VERSION 5.8 ;
BUSBITCHARS "[]" ;
DIVIDERCHAR "/" ;
MANUFACTURINGGRID 0.05 ;

UNITS
    DATABASE MICRONS 1000 ;
END UNITS

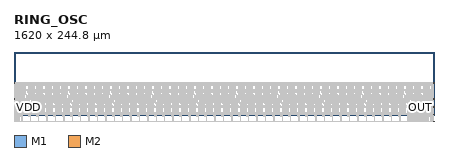
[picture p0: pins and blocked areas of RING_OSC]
MACRO RING_OSC
    CLASS BLOCK ;
    FOREIGN RING_OSC 0.0 0.0 ;
    ORIGIN 0.0 0.0 ;
    SIZE 1620.000 BY 244.800 ;

    PIN OUT
        DIRECTION OUTPUT ;
        USE SIGNAL ;
        PORT
            LAYER M1 ;
                RECT 1616.600 28.000 1620.000 31.400 ;
        END
    END OUT

    PIN OUTD
        DIRECTION OUTPUT ;
        USE SIGNAL ;
        PORT
            LAYER M1 ;
                RECT 1616.600 -26.600 1620.000 -23.200 ;
        END
    END OUTD

    PIN ENB
        DIRECTION INPUT ;
        USE SIGNAL ;
        PORT
            LAYER M2 ;
                RECT 11.800 -118.900 15.200 -115.500 ;
        END
    END ENB

    PIN VDD
        DIRECTION INOUT ;
        USE POWER ;
        PORT
            LAYER M1 ;
                RECT 0.000 -58.900 2.600 -56.300 ;
            LAYER M1 ;
                RECT 1617.400 -58.900 1620.000 -56.300 ;
            LAYER M1 ;
                RECT 0.000 61.100 2.600 63.700 ;
            LAYER M1 ;
                RECT 1617.400 61.100 1620.000 63.700 ;
        END
    END VDD

    PIN VSS
        DIRECTION INOUT ;
        USE GROUND ;
        PORT
            LAYER M1 ;
                RECT 0.000 -118.900 2.600 -116.300 ;
            LAYER M1 ;
                RECT 1617.400 -118.900 1620.000 -116.300 ;
            LAYER M1 ;
                RECT 0.000 1.100 2.600 3.700 ;
            LAYER M1 ;
                RECT 1617.400 1.100 1620.000 3.700 ;
            LAYER M1 ;
                RECT 0.000 121.100 2.600 123.700 ;
            LAYER M1 ;
                RECT 1617.400 121.100 1620.000 123.700 ;
        END
    END VSS

    OBS
        LAYER M1 ;
            POLYGON 2.600 -118.900  2.600 -116.300  1.000 -116.300  1.000 -113.700  4.400 -113.700  4.400 -116.300  11.800 -116.300  11.800 -100.900  14.400 -100.900  14.400 -116.300  18.000 -116.300  18.000 -83.900  20.600 -83.900  20.600 -116.300  49.300 -116.300  49.300 -110.100  51.900 -110.100  51.900 -116.300  81.700 -116.300  81.700 -110.100  84.300 -110.100  84.300 -116.300  114.100 -116.300  114.100 -110.100  116.700 -110.100  116.700 -116.300  146.500 -116.300  146.500 -110.100  149.100 -110.100  149.100 -116.300  178.900 -116.300  178.900 -110.100  181.500 -110.100  181.500 -116.300  211.300 -116.300  211.300 -110.100  213.900 -110.100  213.900 -116.300  243.700 -116.300  243.700 -110.100  246.300 -110.100  246.300 -116.300  276.100 -116.300  276.100 -110.100  278.700 -110.100  278.700 -116.300  308.500 -116.300  308.500 -110.100  311.100 -110.100  311.100 -116.300  340.900 -116.300  340.900 -110.100  343.500 -110.100  343.500 -116.300  373.300 -116.300  373.300 -110.100  375.900 -110.100  375.900 -116.300  405.700 -116.300  405.700 -110.100  408.300 -110.100  408.300 -116.300  438.100 -116.300  438.100 -110.100  440.700 -110.100  440.700 -116.300  470.500 -116.300  470.500 -110.100  473.100 -110.100  473.100 -116.300  502.900 -116.300  502.900 -110.100  505.500 -110.100  505.500 -116.300  535.300 -116.300  535.300 -110.100  537.900 -110.100  537.900 -116.300  567.700 -116.300  567.700 -110.100  570.300 -110.100  570.300 -116.300  600.100 -116.300  600.100 -110.100  602.700 -110.100  602.700 -116.300  632.500 -116.300  632.500 -110.100  635.100 -110.100  635.100 -116.300  664.900 -116.300  664.900 -110.100  667.500 -110.100  667.500 -116.300  697.300 -116.300  697.300 -110.100  699.900 -110.100  699.900 -116.300  729.700 -116.300  729.700 -110.100  732.300 -110.100  732.300 -116.300  762.100 -116.300  762.100 -110.100  764.700 -110.100  764.700 -116.300  794.500 -116.300  794.500 -110.100  797.100 -110.100  797.100 -116.300  826.900 -116.300  826.900 -110.100  829.500 -110.100  829.500 -116.300  859.300 -116.300  859.300 -110.100  861.900 -110.100  861.900 -116.300  891.700 -116.300  891.700 -110.100  894.300 -110.100  894.300 -116.300  924.100 -116.300  924.100 -110.100  926.700 -110.100  926.700 -116.300  956.500 -116.300  956.500 -110.100  959.100 -110.100  959.100 -116.300  988.900 -116.300  988.900 -110.100  991.500 -110.100  991.500 -116.300  1021.300 -116.300  1021.300 -110.100  1023.900 -110.100  1023.900 -116.300  1053.700 -116.300  1053.700 -110.100  1056.300 -110.100  1056.300 -116.300  1086.100 -116.300  1086.100 -110.100  1088.700 -110.100  1088.700 -116.300  1118.500 -116.300  1118.500 -110.100  1121.100 -110.100  1121.100 -116.300  1150.900 -116.300  1150.900 -110.100  1153.500 -110.100  1153.500 -116.300  1183.300 -116.300  1183.300 -110.100  1185.900 -110.100  1185.900 -116.300  1215.700 -116.300  1215.700 -110.100  1218.300 -110.100  1218.300 -116.300  1248.100 -116.300  1248.100 -110.100  1250.700 -110.100  1250.700 -116.300  1280.500 -116.300  1280.500 -110.100  1283.100 -110.100  1283.100 -116.300  1312.900 -116.300  1312.900 -110.100  1315.500 -110.100  1315.500 -116.300  1345.300 -116.300  1345.300 -110.100  1347.900 -110.100  1347.900 -116.300  1377.700 -116.300  1377.700 -110.100  1380.300 -110.100  1380.300 -116.300  1410.100 -116.300  1410.100 -110.100  1412.700 -110.100  1412.700 -116.300  1442.500 -116.300  1442.500 -110.100  1445.100 -110.100  1445.100 -116.300  1474.900 -116.300  1474.900 -110.100  1477.500 -110.100  1477.500 -116.300  1507.300 -116.300  1507.300 -110.100  1509.900 -110.100  1509.900 -116.300  1539.700 -116.300  1539.700 -110.100  1542.300 -110.100  1542.300 -116.300  1572.100 -116.300  1572.100 -110.100  1574.700 -110.100  1574.700 -116.300  1604.500 -116.300  1604.500 -110.100  1607.100 -110.100  1607.100 -116.300  1610.200 -116.300  1610.200 -113.700  1613.600 -113.700  1613.600 -116.300  1617.400 -116.300  1617.400 -118.900 ;
            POLYGON 11.800 -99.300  11.800 -58.900  9.800 -58.900  9.800 -61.500  6.400 -61.500  6.400 -58.900  2.600 -58.900  2.600 -56.300  6.400 -56.300  6.400 -53.700  9.800 -53.700  9.800 -56.300  11.800 -56.300  11.800 -32.900  14.400 -32.900  14.400 -56.300  18.000 -56.300  18.000 -15.900  20.600 -15.900  20.600 -56.300  22.300 -56.300  22.300 -43.300  24.900 -43.300  24.900 -56.300  54.700 -56.300  54.700 -43.300  57.300 -43.300  57.300 -56.300  87.100 -56.300  87.100 -43.300  89.700 -43.300  89.700 -56.300  119.500 -56.300  119.500 -43.300  122.100 -43.300  122.100 -56.300  151.900 -56.300  151.900 -43.300  154.500 -43.300  154.500 -56.300  184.300 -56.300  184.300 -43.300  186.900 -43.300  186.900 -56.300  216.700 -56.300  216.700 -43.300  219.300 -43.300  219.300 -56.300  249.100 -56.300  249.100 -43.300  251.700 -43.300  251.700 -56.300  281.500 -56.300  281.500 -43.300  284.100 -43.300  284.100 -56.300  313.900 -56.300  313.900 -43.300  316.500 -43.300  316.500 -56.300  346.300 -56.300  346.300 -43.300  348.900 -43.300  348.900 -56.300  378.700 -56.300  378.700 -43.300  381.300 -43.300  381.300 -56.300  411.100 -56.300  411.100 -43.300  413.700 -43.300  413.700 -56.300  443.500 -56.300  443.500 -43.300  446.100 -43.300  446.100 -56.300  475.900 -56.300  475.900 -43.300  478.500 -43.300  478.500 -56.300  508.300 -56.300  508.300 -43.300  510.900 -43.300  510.900 -56.300  540.700 -56.300  540.700 -43.300  543.300 -43.300  543.300 -56.300  573.100 -56.300  573.100 -43.300  575.700 -43.300  575.700 -56.300  605.500 -56.300  605.500 -43.300  608.100 -43.300  608.100 -56.300  637.900 -56.300  637.900 -43.300  640.500 -43.300  640.500 -56.300  670.300 -56.300  670.300 -43.300  672.900 -43.300  672.900 -56.300  702.700 -56.300  702.700 -43.300  705.300 -43.300  705.300 -56.300  735.100 -56.300  735.100 -43.300  737.700 -43.300  737.700 -56.300  767.500 -56.300  767.500 -43.300  770.100 -43.300  770.100 -56.300  799.900 -56.300  799.900 -43.300  802.500 -43.300  802.500 -56.300  832.300 -56.300  832.300 -43.300  834.900 -43.300  834.900 -56.300  864.700 -56.300  864.700 -43.300  867.300 -43.300  867.300 -56.300  897.100 -56.300  897.100 -43.300  899.700 -43.300  899.700 -56.300  929.500 -56.300  929.500 -43.300  932.100 -43.300  932.100 -56.300  961.900 -56.300  961.900 -43.300  964.500 -43.300  964.500 -56.300  994.300 -56.300  994.300 -43.300  996.900 -43.300  996.900 -56.300  1026.700 -56.300  1026.700 -43.300  1029.300 -43.300  1029.300 -56.300  1059.100 -56.300  1059.100 -43.300  1061.700 -43.300  1061.700 -56.300  1091.500 -56.300  1091.500 -43.300  1094.100 -43.300  1094.100 -56.300  1123.900 -56.300  1123.900 -43.300  1126.500 -43.300  1126.500 -56.300  1156.300 -56.300  1156.300 -43.300  1158.900 -43.300  1158.900 -56.300  1188.700 -56.300  1188.700 -43.300  1191.300 -43.300  1191.300 -56.300  1221.100 -56.300  1221.100 -43.300  1223.700 -43.300  1223.700 -56.300  1253.500 -56.300  1253.500 -43.300  1256.100 -43.300  1256.100 -56.300  1285.900 -56.300  1285.900 -43.300  1288.500 -43.300  1288.500 -56.300  1318.300 -56.300  1318.300 -43.300  1320.900 -43.300  1320.900 -56.300  1350.700 -56.300  1350.700 -43.300  1353.300 -43.300  1353.300 -56.300  1383.100 -56.300  1383.100 -43.300  1385.700 -43.300  1385.700 -56.300  1415.500 -56.300  1415.500 -43.300  1418.100 -43.300  1418.100 -56.300  1447.900 -56.300  1447.900 -43.300  1450.500 -43.300  1450.500 -56.300  1480.300 -56.300  1480.300 -43.300  1482.900 -43.300  1482.900 -56.300  1512.700 -56.300  1512.700 -43.300  1515.300 -43.300  1515.300 -56.300  1520.700 -56.300  1520.700 -43.300  1523.300 -43.300  1523.300 -56.300  1534.600 -56.300  1534.600 -32.900  1537.200 -32.900  1537.200 -56.300  1540.800 -56.300  1540.800 -15.900  1543.400 -15.900  1543.400 -56.300  1545.400 -56.300  1545.400 -32.900  1548.000 -32.900  1548.000 -56.300  1551.600 -56.300  1551.600 -15.900  1554.200 -15.900  1554.200 -56.300  1556.200 -56.300  1556.200 -32.900  1558.800 -32.900  1558.800 -56.300  1562.400 -56.300  1562.400 -15.900  1565.000 -15.900  1565.000 -56.300  1567.000 -56.300  1567.000 -32.900  1569.600 -32.900  1569.600 -56.300  1573.200 -56.300  1573.200 -15.900  1575.800 -15.900  1575.800 -56.300  1577.800 -56.300  1577.800 -32.900  1580.400 -32.900  1580.400 -56.300  1584.000 -56.300  1584.000 -15.900  1586.600 -15.900  1586.600 -56.300  1588.600 -56.300  1588.600 -32.900  1591.200 -32.900  1591.200 -56.300  1594.800 -56.300  1594.800 -15.900  1597.400 -15.900  1597.400 -56.300  1599.100 -56.300  1599.100 -43.300  1601.700 -43.300  1601.700 -56.300  1615.600 -56.300  1615.600 -53.700  1619.000 -53.700  1619.000 -56.300  1617.400 -56.300  1617.400 -58.900  1619.000 -58.900  1619.000 -61.500  1615.600 -61.500  1615.600 -58.900  1608.500 -58.900  1608.500 -71.900  1605.900 -71.900  1605.900 -58.900  1576.100 -58.900  1576.100 -71.900  1573.500 -71.900  1573.500 -58.900  1543.700 -58.900  1543.700 -71.900  1541.100 -71.900  1541.100 -58.900  1511.300 -58.900  1511.300 -71.900  1508.700 -71.900  1508.700 -58.900  1478.900 -58.900  1478.900 -71.900  1476.300 -71.900  1476.300 -58.900  1446.500 -58.900  1446.500 -71.900  1443.900 -71.900  1443.900 -58.900  1414.100 -58.900  1414.100 -71.900  1411.500 -71.900  1411.500 -58.900  1381.700 -58.900  1381.700 -71.900  1379.100 -71.900  1379.100 -58.900  1349.300 -58.900  1349.300 -71.900  1346.700 -71.900  1346.700 -58.900  1316.900 -58.900  1316.900 -71.900  1314.300 -71.900  1314.300 -58.900  1284.500 -58.900  1284.500 -71.900  1281.900 -71.900  1281.900 -58.900  1252.100 -58.900  1252.100 -71.900  1249.500 -71.900  1249.500 -58.900  1219.700 -58.900  1219.700 -71.900  1217.100 -71.900  1217.100 -58.900  1187.300 -58.900  1187.300 -71.900  1184.700 -71.900  1184.700 -58.900  1154.900 -58.900  1154.900 -71.900  1152.300 -71.900  1152.300 -58.900  1122.500 -58.900  1122.500 -71.900  1119.900 -71.900  1119.900 -58.900  1090.100 -58.900  1090.100 -71.900  1087.500 -71.900  1087.500 -58.900  1057.700 -58.900  1057.700 -71.900  1055.100 -71.900  1055.100 -58.900  1025.300 -58.900  1025.300 -71.900  1022.700 -71.900  1022.700 -58.900  992.900 -58.900  992.900 -71.900  990.300 -71.900  990.300 -58.900  960.500 -58.900  960.500 -71.900  957.900 -71.900  957.900 -58.900  928.100 -58.900  928.100 -71.900  925.500 -71.900  925.500 -58.900  895.700 -58.900  895.700 -71.900  893.100 -71.900  893.100 -58.900  863.300 -58.900  863.300 -71.900  860.700 -71.900  860.700 -58.900  830.900 -58.900  830.900 -71.900  828.300 -71.900  828.300 -58.900  798.500 -58.900  798.500 -71.900  795.900 -71.900  795.900 -58.900  766.100 -58.900  766.100 -71.900  763.500 -71.900  763.500 -58.900  733.700 -58.900  733.700 -71.900  731.100 -71.900  731.100 -58.900  701.300 -58.900  701.300 -71.900  698.700 -71.900  698.700 -58.900  668.900 -58.900  668.900 -71.900  666.300 -71.900  666.300 -58.900  636.500 -58.900  636.500 -71.900  633.900 -71.900  633.900 -58.900  604.100 -58.900  604.100 -71.900  601.500 -71.900  601.500 -58.900  571.700 -58.900  571.700 -71.900  569.100 -71.900  569.100 -58.900  539.300 -58.900  539.300 -71.900  536.700 -71.900  536.700 -58.900  506.900 -58.900  506.900 -71.900  504.300 -71.900  504.300 -58.900  474.500 -58.900  474.500 -71.900  471.900 -71.900  471.900 -58.900  442.100 -58.900  442.100 -71.900  439.500 -71.900  439.500 -58.900  409.700 -58.900  409.700 -71.900  407.100 -71.900  407.100 -58.900  377.300 -58.900  377.300 -71.900  374.700 -71.900  374.700 -58.900  344.900 -58.900  344.900 -71.900  342.300 -71.900  342.300 -58.900  312.500 -58.900  312.500 -71.900  309.900 -71.900  309.900 -58.900  280.100 -58.900  280.100 -71.900  277.500 -71.900  277.500 -58.900  247.700 -58.900  247.700 -71.900  245.100 -71.900  245.100 -58.900  215.300 -58.900  215.300 -71.900  212.700 -71.900  212.700 -58.900  182.900 -58.900  182.900 -71.900  180.300 -71.900  180.300 -58.900  150.500 -58.900  150.500 -71.900  147.900 -71.900  147.900 -58.900  118.100 -58.900  118.100 -71.900  115.500 -71.900  115.500 -58.900  85.700 -58.900  85.700 -71.900  83.100 -71.900  83.100 -58.900  53.300 -58.900  53.300 -71.900  50.700 -71.900  50.700 -58.900  20.600 -58.900  20.600 -82.300  18.000 -82.300  18.000 -58.900  14.400 -58.900  14.400 -99.300 ;
            POLYGON 11.800 -31.300  11.800 1.100  4.400 1.100  4.400 -1.500  1.000 -1.500  1.000 1.100  2.600 1.100  2.600 3.700  1.000 3.700  1.000 6.300  4.400 6.300  4.400 3.700  11.800 3.700  11.800 36.100  14.400 36.100  14.400 3.700  18.000 3.700  18.000 19.100  20.600 19.100  20.600 3.700  23.700 3.700  23.700 9.900  26.300 9.900  26.300 3.700  33.400 3.700  33.400 36.100  36.000 36.100  36.000 3.700  39.600 3.700  39.600 19.100  42.200 19.100  42.200 3.700  44.200 3.700  44.200 36.100  46.800 36.100  46.800 3.700  50.400 3.700  50.400 19.100  53.000 19.100  53.000 3.700  56.100 3.700  56.100 9.900  58.700 9.900  58.700 3.700  65.800 3.700  65.800 36.100  68.400 36.100  68.400 3.700  72.000 3.700  72.000 19.100  74.600 19.100  74.600 3.700  76.600 3.700  76.600 36.100  79.200 36.100  79.200 3.700  82.800 3.700  82.800 19.100  85.400 19.100  85.400 3.700  88.500 3.700  88.500 9.900  91.100 9.900  91.100 3.700  98.200 3.700  98.200 36.100  100.800 36.100  100.800 3.700  104.400 3.700  104.400 19.100  107.000 19.100  107.000 3.700  109.000 3.700  109.000 36.100  111.600 36.100  111.600 3.700  115.200 3.700  115.200 19.100  117.800 19.100  117.800 3.700  120.900 3.700  120.900 9.900  123.500 9.900  123.500 3.700  130.600 3.700  130.600 36.100  133.200 36.100  133.200 3.700  136.800 3.700  136.800 19.100  139.400 19.100  139.400 3.700  141.400 3.700  141.400 36.100  144.000 36.100  144.000 3.700  147.600 3.700  147.600 19.100  150.200 19.100  150.200 3.700  153.300 3.700  153.300 9.900  155.900 9.900  155.900 3.700  163.000 3.700  163.000 36.100  165.600 36.100  165.600 3.700  169.200 3.700  169.200 19.100  171.800 19.100  171.800 3.700  173.800 3.700  173.800 36.100  176.400 36.100  176.400 3.700  180.000 3.700  180.000 19.100  182.600 19.100  182.600 3.700  185.700 3.700  185.700 9.900  188.300 9.900  188.300 3.700  195.400 3.700  195.400 36.100  198.000 36.100  198.000 3.700  201.600 3.700  201.600 19.100  204.200 19.100  204.200 3.700  206.200 3.700  206.200 36.100  208.800 36.100  208.800 3.700  212.400 3.700  212.400 19.100  215.000 19.100  215.000 3.700  218.100 3.700  218.100 9.900  220.700 9.900  220.700 3.700  227.800 3.700  227.800 36.100  230.400 36.100  230.400 3.700  234.000 3.700  234.000 19.100  236.600 19.100  236.600 3.700  238.600 3.700  238.600 36.100  241.200 36.100  241.200 3.700  244.800 3.700  244.800 19.100  247.400 19.100  247.400 3.700  250.500 3.700  250.500 9.900  253.100 9.900  253.100 3.700  260.200 3.700  260.200 36.100  262.800 36.100  262.800 3.700  266.400 3.700  266.400 19.100  269.000 19.100  269.000 3.700  271.000 3.700  271.000 36.100  273.600 36.100  273.600 3.700  277.200 3.700  277.200 19.100  279.800 19.100  279.800 3.700  282.900 3.700  282.900 9.900  285.500 9.900  285.500 3.700  292.600 3.700  292.600 36.100  295.200 36.100  295.200 3.700  298.800 3.700  298.800 19.100  301.400 19.100  301.400 3.700  303.400 3.700  303.400 36.100  306.000 36.100  306.000 3.700  309.600 3.700  309.600 19.100  312.200 19.100  312.200 3.700  315.300 3.700  315.300 9.900  317.900 9.900  317.900 3.700  325.000 3.700  325.000 36.100  327.600 36.100  327.600 3.700  331.200 3.700  331.200 19.100  333.800 19.100  333.800 3.700  335.800 3.700  335.800 36.100  338.400 36.100  338.400 3.700  342.000 3.700  342.000 19.100  344.600 19.100  344.600 3.700  347.700 3.700  347.700 9.900  350.300 9.900  350.300 3.700  357.400 3.700  357.400 36.100  360.000 36.100  360.000 3.700  363.600 3.700  363.600 19.100  366.200 19.100  366.200 3.700  368.200 3.700  368.200 36.100  370.800 36.100  370.800 3.700  374.400 3.700  374.400 19.100  377.000 19.100  377.000 3.700  380.100 3.700  380.100 9.900  382.700 9.900  382.700 3.700  389.800 3.700  389.800 36.100  392.400 36.100  392.400 3.700  396.000 3.700  396.000 19.100  398.600 19.100  398.600 3.700  400.600 3.700  400.600 36.100  403.200 36.100  403.200 3.700  406.800 3.700  406.800 19.100  409.400 19.100  409.400 3.700  412.500 3.700  412.500 9.900  415.100 9.900  415.100 3.700  422.200 3.700  422.200 36.100  424.800 36.100  424.800 3.700  428.400 3.700  428.400 19.100  431.000 19.100  431.000 3.700  433.000 3.700  433.000 36.100  435.600 36.100  435.600 3.700  439.200 3.700  439.200 19.100  441.800 19.100  441.800 3.700  444.900 3.700  444.900 9.900  447.500 9.900  447.500 3.700  454.600 3.700  454.600 36.100  457.200 36.100  457.200 3.700  460.800 3.700  460.800 19.100  463.400 19.100  463.400 3.700  465.400 3.700  465.400 36.100  468.000 36.100  468.000 3.700  471.600 3.700  471.600 19.100  474.200 19.100  474.200 3.700  477.300 3.700  477.300 9.900  479.900 9.900  479.900 3.700  487.000 3.700  487.000 36.100  489.600 36.100  489.600 3.700  493.200 3.700  493.200 19.100  495.800 19.100  495.800 3.700  497.800 3.700  497.800 36.100  500.400 36.100  500.400 3.700  504.000 3.700  504.000 19.100  506.600 19.100  506.600 3.700  509.700 3.700  509.700 9.900  512.300 9.900  512.300 3.700  519.400 3.700  519.400 36.100  522.000 36.100  522.000 3.700  525.600 3.700  525.600 19.100  528.200 19.100  528.200 3.700  530.200 3.700  530.200 36.100  532.800 36.100  532.800 3.700  536.400 3.700  536.400 19.100  539.000 19.100  539.000 3.700  542.100 3.700  542.100 9.900  544.700 9.900  544.700 3.700  551.800 3.700  551.800 36.100  554.400 36.100  554.400 3.700  558.000 3.700  558.000 19.100  560.600 19.100  560.600 3.700  562.600 3.700  562.600 36.100  565.200 36.100  565.200 3.700  568.800 3.700  568.800 19.100  571.400 19.100  571.400 3.700  574.500 3.700  574.500 9.900  577.100 9.900  577.100 3.700  584.200 3.700  584.200 36.100  586.800 36.100  586.800 3.700  590.400 3.700  590.400 19.100  593.000 19.100  593.000 3.700  595.000 3.700  595.000 36.100  597.600 36.100  597.600 3.700  601.200 3.700  601.200 19.100  603.800 19.100  603.800 3.700  606.900 3.700  606.900 9.900  609.500 9.900  609.500 3.700  616.600 3.700  616.600 36.100  619.200 36.100  619.200 3.700  622.800 3.700  622.800 19.100  625.400 19.100  625.400 3.700  627.400 3.700  627.400 36.100  630.000 36.100  630.000 3.700  633.600 3.700  633.600 19.100  636.200 19.100  636.200 3.700  639.300 3.700  639.300 9.900  641.900 9.900  641.900 3.700  649.000 3.700  649.000 36.100  651.600 36.100  651.600 3.700  655.200 3.700  655.200 19.100  657.800 19.100  657.800 3.700  659.800 3.700  659.800 36.100  662.400 36.100  662.400 3.700  666.000 3.700  666.000 19.100  668.600 19.100  668.600 3.700  671.700 3.700  671.700 9.900  674.300 9.900  674.300 3.700  681.400 3.700  681.400 36.100  684.000 36.100  684.000 3.700  687.600 3.700  687.600 19.100  690.200 19.100  690.200 3.700  692.200 3.700  692.200 36.100  694.800 36.100  694.800 3.700  698.400 3.700  698.400 19.100  701.000 19.100  701.000 3.700  704.100 3.700  704.100 9.900  706.700 9.900  706.700 3.700  713.800 3.700  713.800 36.100  716.400 36.100  716.400 3.700  720.000 3.700  720.000 19.100  722.600 19.100  722.600 3.700  724.600 3.700  724.600 36.100  727.200 36.100  727.200 3.700  730.800 3.700  730.800 19.100  733.400 19.100  733.400 3.700  736.500 3.700  736.500 9.900  739.100 9.900  739.100 3.700  746.200 3.700  746.200 36.100  748.800 36.100  748.800 3.700  752.400 3.700  752.400 19.100  755.000 19.100  755.000 3.700  757.000 3.700  757.000 36.100  759.600 36.100  759.600 3.700  763.200 3.700  763.200 19.100  765.800 19.100  765.800 3.700  768.900 3.700  768.900 9.900  771.500 9.900  771.500 3.700  778.600 3.700  778.600 36.100  781.200 36.100  781.200 3.700  784.800 3.700  784.800 19.100  787.400 19.100  787.400 3.700  789.400 3.700  789.400 36.100  792.000 36.100  792.000 3.700  795.600 3.700  795.600 19.100  798.200 19.100  798.200 3.700  801.300 3.700  801.300 9.900  803.900 9.900  803.900 3.700  811.000 3.700  811.000 36.100  813.600 36.100  813.600 3.700  817.200 3.700  817.200 19.100  819.800 19.100  819.800 3.700  821.800 3.700  821.800 36.100  824.400 36.100  824.400 3.700  828.000 3.700  828.000 19.100  830.600 19.100  830.600 3.700  833.700 3.700  833.700 9.900  836.300 9.900  836.300 3.700  843.400 3.700  843.400 36.100  846.000 36.100  846.000 3.700  849.600 3.700  849.600 19.100  852.200 19.100  852.200 3.700  854.200 3.700  854.200 36.100  856.800 36.100  856.800 3.700  860.400 3.700  860.400 19.100  863.000 19.100  863.000 3.700  866.100 3.700  866.100 9.900  868.700 9.900  868.700 3.700  875.800 3.700  875.800 36.100  878.400 36.100  878.400 3.700  882.000 3.700  882.000 19.100  884.600 19.100  884.600 3.700  886.600 3.700  886.600 36.100  889.200 36.100  889.200 3.700  892.800 3.700  892.800 19.100  895.400 19.100  895.400 3.700  898.500 3.700  898.500 9.900  901.100 9.900  901.100 3.700  908.200 3.700  908.200 36.100  910.800 36.100  910.800 3.700  914.400 3.700  914.400 19.100  917.000 19.100  917.000 3.700  919.000 3.700  919.000 36.100  921.600 36.100  921.600 3.700  925.200 3.700  925.200 19.100  927.800 19.100  927.800 3.700  930.900 3.700  930.900 9.900  933.500 9.900  933.500 3.700  940.600 3.700  940.600 36.100  943.200 36.100  943.200 3.700  946.800 3.700  946.800 19.100  949.400 19.100  949.400 3.700  951.400 3.700  951.400 36.100  954.000 36.100  954.000 3.700  957.600 3.700  957.600 19.100  960.200 19.100  960.200 3.700  963.300 3.700  963.300 9.900  965.900 9.900  965.900 3.700  973.000 3.700  973.000 36.100  975.600 36.100  975.600 3.700  979.200 3.700  979.200 19.100  981.800 19.100  981.800 3.700  983.800 3.700  983.800 36.100  986.400 36.100  986.400 3.700  990.000 3.700  990.000 19.100  992.600 19.100  992.600 3.700  995.700 3.700  995.700 9.900  998.300 9.900  998.300 3.700  1005.400 3.700  1005.400 36.100  1008.000 36.100  1008.000 3.700  1011.600 3.700  1011.600 19.100  1014.200 19.100  1014.200 3.700  1016.200 3.700  1016.200 36.100  1018.800 36.100  1018.800 3.700  1022.400 3.700  1022.400 19.100  1025.000 19.100  1025.000 3.700  1028.100 3.700  1028.100 9.900  1030.700 9.900  1030.700 3.700  1037.800 3.700  1037.800 36.100  1040.400 36.100  1040.400 3.700  1044.000 3.700  1044.000 19.100  1046.600 19.100  1046.600 3.700  1048.600 3.700  1048.600 36.100  1051.200 36.100  1051.200 3.700  1054.800 3.700  1054.800 19.100  1057.400 19.100  1057.400 3.700  1060.500 3.700  1060.500 9.900  1063.100 9.900  1063.100 3.700  1070.200 3.700  1070.200 36.100  1072.800 36.100  1072.800 3.700  1076.400 3.700  1076.400 19.100  1079.000 19.100  1079.000 3.700  1081.000 3.700  1081.000 36.100  1083.600 36.100  1083.600 3.700  1087.200 3.700  1087.200 19.100  1089.800 19.100  1089.800 3.700  1092.900 3.700  1092.900 9.900  1095.500 9.900  1095.500 3.700  1102.600 3.700  1102.600 36.100  1105.200 36.100  1105.200 3.700  1108.800 3.700  1108.800 19.100  1111.400 19.100  1111.400 3.700  1113.400 3.700  1113.400 36.100  1116.000 36.100  1116.000 3.700  1119.600 3.700  1119.600 19.100  1122.200 19.100  1122.200 3.700  1125.300 3.700  1125.300 9.900  1127.900 9.900  1127.900 3.700  1135.000 3.700  1135.000 36.100  1137.600 36.100  1137.600 3.700  1141.200 3.700  1141.200 19.100  1143.800 19.100  1143.800 3.700  1145.800 3.700  1145.800 36.100  1148.400 36.100  1148.400 3.700  1152.000 3.700  1152.000 19.100  1154.600 19.100  1154.600 3.700  1157.700 3.700  1157.700 9.900  1160.300 9.900  1160.300 3.700  1167.400 3.700  1167.400 36.100  1170.000 36.100  1170.000 3.700  1173.600 3.700  1173.600 19.100  1176.200 19.100  1176.200 3.700  1178.200 3.700  1178.200 36.100  1180.800 36.100  1180.800 3.700  1184.400 3.700  1184.400 19.100  1187.000 19.100  1187.000 3.700  1190.100 3.700  1190.100 9.900  1192.700 9.900  1192.700 3.700  1199.800 3.700  1199.800 36.100  1202.400 36.100  1202.400 3.700  1206.000 3.700  1206.000 19.100  1208.600 19.100  1208.600 3.700  1210.600 3.700  1210.600 36.100  1213.200 36.100  1213.200 3.700  1216.800 3.700  1216.800 19.100  1219.400 19.100  1219.400 3.700  1222.500 3.700  1222.500 9.900  1225.100 9.900  1225.100 3.700  1232.200 3.700  1232.200 36.100  1234.800 36.100  1234.800 3.700  1238.400 3.700  1238.400 19.100  1241.000 19.100  1241.000 3.700  1243.000 3.700  1243.000 36.100  1245.600 36.100  1245.600 3.700  1249.200 3.700  1249.200 19.100  1251.800 19.100  1251.800 3.700  1254.900 3.700  1254.900 9.900  1257.500 9.900  1257.500 3.700  1264.600 3.700  1264.600 36.100  1267.200 36.100  1267.200 3.700  1270.800 3.700  1270.800 19.100  1273.400 19.100  1273.400 3.700  1275.400 3.700  1275.400 36.100  1278.000 36.100  1278.000 3.700  1281.600 3.700  1281.600 19.100  1284.200 19.100  1284.200 3.700  1287.300 3.700  1287.300 9.900  1289.900 9.900  1289.900 3.700  1297.000 3.700  1297.000 36.100  1299.600 36.100  1299.600 3.700  1303.200 3.700  1303.200 19.100  1305.800 19.100  1305.800 3.700  1307.800 3.700  1307.800 36.100  1310.400 36.100  1310.400 3.700  1314.000 3.700  1314.000 19.100  1316.600 19.100  1316.600 3.700  1319.700 3.700  1319.700 9.900  1322.300 9.900  1322.300 3.700  1329.400 3.700  1329.400 36.100  1332.000 36.100  1332.000 3.700  1335.600 3.700  1335.600 19.100  1338.200 19.100  1338.200 3.700  1340.200 3.700  1340.200 36.100  1342.800 36.100  1342.800 3.700  1346.400 3.700  1346.400 19.100  1349.000 19.100  1349.000 3.700  1352.100 3.700  1352.100 9.900  1354.700 9.900  1354.700 3.700  1361.800 3.700  1361.800 36.100  1364.400 36.100  1364.400 3.700  1368.000 3.700  1368.000 19.100  1370.600 19.100  1370.600 3.700  1372.600 3.700  1372.600 36.100  1375.200 36.100  1375.200 3.700  1378.800 3.700  1378.800 19.100  1381.400 19.100  1381.400 3.700  1384.500 3.700  1384.500 9.900  1387.100 9.900  1387.100 3.700  1394.200 3.700  1394.200 36.100  1396.800 36.100  1396.800 3.700  1400.400 3.700  1400.400 19.100  1403.000 19.100  1403.000 3.700  1405.000 3.700  1405.000 36.100  1407.600 36.100  1407.600 3.700  1411.200 3.700  1411.200 19.100  1413.800 19.100  1413.800 3.700  1416.900 3.700  1416.900 9.900  1419.500 9.900  1419.500 3.700  1426.600 3.700  1426.600 36.100  1429.200 36.100  1429.200 3.700  1432.800 3.700  1432.800 19.100  1435.400 19.100  1435.400 3.700  1437.400 3.700  1437.400 36.100  1440.000 36.100  1440.000 3.700  1443.600 3.700  1443.600 19.100  1446.200 19.100  1446.200 3.700  1449.300 3.700  1449.300 9.900  1451.900 9.900  1451.900 3.700  1459.000 3.700  1459.000 36.100  1461.600 36.100  1461.600 3.700  1465.200 3.700  1465.200 19.100  1467.800 19.100  1467.800 3.700  1469.800 3.700  1469.800 36.100  1472.400 36.100  1472.400 3.700  1476.000 3.700  1476.000 19.100  1478.600 19.100  1478.600 3.700  1481.700 3.700  1481.700 9.900  1484.300 9.900  1484.300 3.700  1491.400 3.700  1491.400 36.100  1494.000 36.100  1494.000 3.700  1497.600 3.700  1497.600 19.100  1500.200 19.100  1500.200 3.700  1502.200 3.700  1502.200 36.100  1504.800 36.100  1504.800 3.700  1508.400 3.700  1508.400 19.100  1511.000 19.100  1511.000 3.700  1517.300 3.700  1517.300 19.600  1519.900 19.600  1519.900 11.100  1527.500 11.100  1527.500 7.700  1519.900 7.700  1519.900 3.700  1534.600 3.700  1534.600 36.100  1537.200 36.100  1537.200 3.700  1540.800 3.700  1540.800 19.100  1543.400 19.100  1543.400 3.700  1545.400 3.700  1545.400 36.100  1548.000 36.100  1548.000 3.700  1551.600 3.700  1551.600 19.100  1554.200 19.100  1554.200 3.700  1556.200 3.700  1556.200 36.100  1558.800 36.100  1558.800 3.700  1562.400 3.700  1562.400 19.100  1565.000 19.100  1565.000 3.700  1567.000 3.700  1567.000 36.100  1569.600 36.100  1569.600 3.700  1573.200 3.700  1573.200 19.100  1575.800 19.100  1575.800 3.700  1577.800 3.700  1577.800 36.100  1580.400 36.100  1580.400 3.700  1584.000 3.700  1584.000 19.100  1586.600 19.100  1586.600 3.700  1588.600 3.700  1588.600 36.100  1591.200 36.100  1591.200 3.700  1594.800 3.700  1594.800 19.100  1597.400 19.100  1597.400 3.700  1600.500 3.700  1600.500 9.900  1603.100 9.900  1603.100 3.700  1610.200 3.700  1610.200 6.300  1613.600 6.300  1613.600 3.700  1617.400 3.700  1617.400 1.100  1613.600 1.100  1613.600 -1.500  1610.200 -1.500  1610.200 1.100  1603.100 1.100  1603.100 -5.100  1600.500 -5.100  1600.500 1.100  1597.400 1.100  1597.400 -14.300  1594.800 -14.300  1594.800 1.100  1591.200 1.100  1591.200 -31.300  1588.600 -31.300  1588.600 1.100  1586.600 1.100  1586.600 -14.300  1584.000 -14.300  1584.000 1.100  1580.400 1.100  1580.400 -31.300  1577.800 -31.300  1577.800 1.100  1575.800 1.100  1575.800 -14.300  1573.200 -14.300  1573.200 1.100  1569.600 1.100  1569.600 -31.300  1567.000 -31.300  1567.000 1.100  1565.000 1.100  1565.000 -14.300  1562.400 -14.300  1562.400 1.100  1558.800 1.100  1558.800 -31.300  1556.200 -31.300  1556.200 1.100  1554.200 1.100  1554.200 -14.300  1551.600 -14.300  1551.600 1.100  1548.000 1.100  1548.000 -31.300  1545.400 -31.300  1545.400 1.100  1543.400 1.100  1543.400 -14.300  1540.800 -14.300  1540.800 1.100  1537.200 1.100  1537.200 -31.300  1534.600 -31.300  1534.600 1.100  1519.900 1.100  1519.900 -2.900  1527.500 -2.900  1527.500 -6.300  1519.900 -6.300  1519.900 -14.800  1517.300 -14.800  1517.300 1.100  1484.300 1.100  1484.300 -5.100  1481.700 -5.100  1481.700 1.100  1451.900 1.100  1451.900 -5.100  1449.300 -5.100  1449.300 1.100  1419.500 1.100  1419.500 -5.100  1416.900 -5.100  1416.900 1.100  1387.100 1.100  1387.100 -5.100  1384.500 -5.100  1384.500 1.100  1354.700 1.100  1354.700 -5.100  1352.100 -5.100  1352.100 1.100  1322.300 1.100  1322.300 -5.100  1319.700 -5.100  1319.700 1.100  1289.900 1.100  1289.900 -5.100  1287.300 -5.100  1287.300 1.100  1257.500 1.100  1257.500 -5.100  1254.900 -5.100  1254.900 1.100  1225.100 1.100  1225.100 -5.100  1222.500 -5.100  1222.500 1.100  1192.700 1.100  1192.700 -5.100  1190.100 -5.100  1190.100 1.100  1160.300 1.100  1160.300 -5.100  1157.700 -5.100  1157.700 1.100  1127.900 1.100  1127.900 -5.100  1125.300 -5.100  1125.300 1.100  1095.500 1.100  1095.500 -5.100  1092.900 -5.100  1092.900 1.100  1063.100 1.100  1063.100 -5.100  1060.500 -5.100  1060.500 1.100  1030.700 1.100  1030.700 -5.100  1028.100 -5.100  1028.100 1.100  998.300 1.100  998.300 -5.100  995.700 -5.100  995.700 1.100  965.900 1.100  965.900 -5.100  963.300 -5.100  963.300 1.100  933.500 1.100  933.500 -5.100  930.900 -5.100  930.900 1.100  901.100 1.100  901.100 -5.100  898.500 -5.100  898.500 1.100  868.700 1.100  868.700 -5.100  866.100 -5.100  866.100 1.100  836.300 1.100  836.300 -5.100  833.700 -5.100  833.700 1.100  803.900 1.100  803.900 -5.100  801.300 -5.100  801.300 1.100  771.500 1.100  771.500 -5.100  768.900 -5.100  768.900 1.100  739.100 1.100  739.100 -5.100  736.500 -5.100  736.500 1.100  706.700 1.100  706.700 -5.100  704.100 -5.100  704.100 1.100  674.300 1.100  674.300 -5.100  671.700 -5.100  671.700 1.100  641.900 1.100  641.900 -5.100  639.300 -5.100  639.300 1.100  609.500 1.100  609.500 -5.100  606.900 -5.100  606.900 1.100  577.100 1.100  577.100 -5.100  574.500 -5.100  574.500 1.100  544.700 1.100  544.700 -5.100  542.100 -5.100  542.100 1.100  512.300 1.100  512.300 -5.100  509.700 -5.100  509.700 1.100  479.900 1.100  479.900 -5.100  477.300 -5.100  477.300 1.100  447.500 1.100  447.500 -5.100  444.900 -5.100  444.900 1.100  415.100 1.100  415.100 -5.100  412.500 -5.100  412.500 1.100  382.700 1.100  382.700 -5.100  380.100 -5.100  380.100 1.100  350.300 1.100  350.300 -5.100  347.700 -5.100  347.700 1.100  317.900 1.100  317.900 -5.100  315.300 -5.100  315.300 1.100  285.500 1.100  285.500 -5.100  282.900 -5.100  282.900 1.100  253.100 1.100  253.100 -5.100  250.500 -5.100  250.500 1.100  220.700 1.100  220.700 -5.100  218.100 -5.100  218.100 1.100  188.300 1.100  188.300 -5.100  185.700 -5.100  185.700 1.100  155.900 1.100  155.900 -5.100  153.300 -5.100  153.300 1.100  123.500 1.100  123.500 -5.100  120.900 -5.100  120.900 1.100  91.100 1.100  91.100 -5.100  88.500 -5.100  88.500 1.100  58.700 1.100  58.700 -5.100  56.100 -5.100  56.100 1.100  26.300 1.100  26.300 -5.100  23.700 -5.100  23.700 1.100  20.600 1.100  20.600 -14.300  18.000 -14.300  18.000 1.100  14.400 1.100  14.400 -31.300 ;
            POLYGON 18.000 20.700  18.000 61.100  14.400 61.100  14.400 37.700  11.800 37.700  11.800 61.100  9.800 61.100  9.800 58.500  6.400 58.500  6.400 61.100  2.600 61.100  2.600 63.700  6.400 63.700  6.400 66.300  9.800 66.300  9.800 63.700  11.800 63.700  11.800 104.100  14.400 104.100  14.400 63.700  18.000 63.700  18.000 87.100  20.600 87.100  20.600 63.700  22.600 63.700  22.600 104.100  25.200 104.100  25.200 63.700  28.800 63.700  28.800 87.100  31.400 87.100  31.400 63.700  33.400 63.700  33.400 104.100  36.000 104.100  36.000 63.700  39.600 63.700  39.600 87.100  42.200 87.100  42.200 63.700  50.700 63.700  50.700 76.700  53.300 76.700  53.300 63.700  55.000 63.700  55.000 104.100  57.600 104.100  57.600 63.700  61.200 63.700  61.200 87.100  63.800 87.100  63.800 63.700  65.800 63.700  65.800 104.100  68.400 104.100  68.400 63.700  72.000 63.700  72.000 87.100  74.600 87.100  74.600 63.700  83.100 63.700  83.100 76.700  85.700 76.700  85.700 63.700  87.400 63.700  87.400 104.100  90.000 104.100  90.000 63.700  93.600 63.700  93.600 87.100  96.200 87.100  96.200 63.700  98.200 63.700  98.200 104.100  100.800 104.100  100.800 63.700  104.400 63.700  104.400 87.100  107.000 87.100  107.000 63.700  115.500 63.700  115.500 76.700  118.100 76.700  118.100 63.700  119.800 63.700  119.800 104.100  122.400 104.100  122.400 63.700  126.000 63.700  126.000 87.100  128.600 87.100  128.600 63.700  130.600 63.700  130.600 104.100  133.200 104.100  133.200 63.700  136.800 63.700  136.800 87.100  139.400 87.100  139.400 63.700  147.900 63.700  147.900 76.700  150.500 76.700  150.500 63.700  152.200 63.700  152.200 104.100  154.800 104.100  154.800 63.700  158.400 63.700  158.400 87.100  161.000 87.100  161.000 63.700  163.000 63.700  163.000 104.100  165.600 104.100  165.600 63.700  169.200 63.700  169.200 87.100  171.800 87.100  171.800 63.700  180.300 63.700  180.300 76.700  182.900 76.700  182.900 63.700  184.600 63.700  184.600 104.100  187.200 104.100  187.200 63.700  190.800 63.700  190.800 87.100  193.400 87.100  193.400 63.700  195.400 63.700  195.400 104.100  198.000 104.100  198.000 63.700  201.600 63.700  201.600 87.100  204.200 87.100  204.200 63.700  212.700 63.700  212.700 76.700  215.300 76.700  215.300 63.700  217.000 63.700  217.000 104.100  219.600 104.100  219.600 63.700  223.200 63.700  223.200 87.100  225.800 87.100  225.800 63.700  227.800 63.700  227.800 104.100  230.400 104.100  230.400 63.700  234.000 63.700  234.000 87.100  236.600 87.100  236.600 63.700  245.100 63.700  245.100 76.700  247.700 76.700  247.700 63.700  249.400 63.700  249.400 104.100  252.000 104.100  252.000 63.700  255.600 63.700  255.600 87.100  258.200 87.100  258.200 63.700  260.200 63.700  260.200 104.100  262.800 104.100  262.800 63.700  266.400 63.700  266.400 87.100  269.000 87.100  269.000 63.700  277.500 63.700  277.500 76.700  280.100 76.700  280.100 63.700  281.800 63.700  281.800 104.100  284.400 104.100  284.400 63.700  288.000 63.700  288.000 87.100  290.600 87.100  290.600 63.700  292.600 63.700  292.600 104.100  295.200 104.100  295.200 63.700  298.800 63.700  298.800 87.100  301.400 87.100  301.400 63.700  309.900 63.700  309.900 76.700  312.500 76.700  312.500 63.700  314.200 63.700  314.200 104.100  316.800 104.100  316.800 63.700  320.400 63.700  320.400 87.100  323.000 87.100  323.000 63.700  325.000 63.700  325.000 104.100  327.600 104.100  327.600 63.700  331.200 63.700  331.200 87.100  333.800 87.100  333.800 63.700  342.300 63.700  342.300 76.700  344.900 76.700  344.900 63.700  346.600 63.700  346.600 104.100  349.200 104.100  349.200 63.700  352.800 63.700  352.800 87.100  355.400 87.100  355.400 63.700  357.400 63.700  357.400 104.100  360.000 104.100  360.000 63.700  363.600 63.700  363.600 87.100  366.200 87.100  366.200 63.700  374.700 63.700  374.700 76.700  377.300 76.700  377.300 63.700  379.000 63.700  379.000 104.100  381.600 104.100  381.600 63.700  385.200 63.700  385.200 87.100  387.800 87.100  387.800 63.700  389.800 63.700  389.800 104.100  392.400 104.100  392.400 63.700  396.000 63.700  396.000 87.100  398.600 87.100  398.600 63.700  407.100 63.700  407.100 76.700  409.700 76.700  409.700 63.700  411.400 63.700  411.400 104.100  414.000 104.100  414.000 63.700  417.600 63.700  417.600 87.100  420.200 87.100  420.200 63.700  422.200 63.700  422.200 104.100  424.800 104.100  424.800 63.700  428.400 63.700  428.400 87.100  431.000 87.100  431.000 63.700  439.500 63.700  439.500 76.700  442.100 76.700  442.100 63.700  443.800 63.700  443.800 104.100  446.400 104.100  446.400 63.700  450.000 63.700  450.000 87.100  452.600 87.100  452.600 63.700  454.600 63.700  454.600 104.100  457.200 104.100  457.200 63.700  460.800 63.700  460.800 87.100  463.400 87.100  463.400 63.700  471.900 63.700  471.900 76.700  474.500 76.700  474.500 63.700  476.200 63.700  476.200 104.100  478.800 104.100  478.800 63.700  482.400 63.700  482.400 87.100  485.000 87.100  485.000 63.700  487.000 63.700  487.000 104.100  489.600 104.100  489.600 63.700  493.200 63.700  493.200 87.100  495.800 87.100  495.800 63.700  504.300 63.700  504.300 76.700  506.900 76.700  506.900 63.700  508.600 63.700  508.600 104.100  511.200 104.100  511.200 63.700  514.800 63.700  514.800 87.100  517.400 87.100  517.400 63.700  519.400 63.700  519.400 104.100  522.000 104.100  522.000 63.700  525.600 63.700  525.600 87.100  528.200 87.100  528.200 63.700  536.700 63.700  536.700 76.700  539.300 76.700  539.300 63.700  541.000 63.700  541.000 104.100  543.600 104.100  543.600 63.700  547.200 63.700  547.200 87.100  549.800 87.100  549.800 63.700  551.800 63.700  551.800 104.100  554.400 104.100  554.400 63.700  558.000 63.700  558.000 87.100  560.600 87.100  560.600 63.700  569.100 63.700  569.100 76.700  571.700 76.700  571.700 63.700  573.400 63.700  573.400 104.100  576.000 104.100  576.000 63.700  579.600 63.700  579.600 87.100  582.200 87.100  582.200 63.700  584.200 63.700  584.200 104.100  586.800 104.100  586.800 63.700  590.400 63.700  590.400 87.100  593.000 87.100  593.000 63.700  601.500 63.700  601.500 76.700  604.100 76.700  604.100 63.700  605.800 63.700  605.800 104.100  608.400 104.100  608.400 63.700  612.000 63.700  612.000 87.100  614.600 87.100  614.600 63.700  616.600 63.700  616.600 104.100  619.200 104.100  619.200 63.700  622.800 63.700  622.800 87.100  625.400 87.100  625.400 63.700  633.900 63.700  633.900 76.700  636.500 76.700  636.500 63.700  638.200 63.700  638.200 104.100  640.800 104.100  640.800 63.700  644.400 63.700  644.400 87.100  647.000 87.100  647.000 63.700  649.000 63.700  649.000 104.100  651.600 104.100  651.600 63.700  655.200 63.700  655.200 87.100  657.800 87.100  657.800 63.700  666.300 63.700  666.300 76.700  668.900 76.700  668.900 63.700  670.600 63.700  670.600 104.100  673.200 104.100  673.200 63.700  676.800 63.700  676.800 87.100  679.400 87.100  679.400 63.700  681.400 63.700  681.400 104.100  684.000 104.100  684.000 63.700  687.600 63.700  687.600 87.100  690.200 87.100  690.200 63.700  698.700 63.700  698.700 76.700  701.300 76.700  701.300 63.700  703.000 63.700  703.000 104.100  705.600 104.100  705.600 63.700  709.200 63.700  709.200 87.100  711.800 87.100  711.800 63.700  713.800 63.700  713.800 104.100  716.400 104.100  716.400 63.700  720.000 63.700  720.000 87.100  722.600 87.100  722.600 63.700  731.100 63.700  731.100 76.700  733.700 76.700  733.700 63.700  735.400 63.700  735.400 104.100  738.000 104.100  738.000 63.700  741.600 63.700  741.600 87.100  744.200 87.100  744.200 63.700  746.200 63.700  746.200 104.100  748.800 104.100  748.800 63.700  752.400 63.700  752.400 87.100  755.000 87.100  755.000 63.700  763.500 63.700  763.500 76.700  766.100 76.700  766.100 63.700  767.800 63.700  767.800 104.100  770.400 104.100  770.400 63.700  774.000 63.700  774.000 87.100  776.600 87.100  776.600 63.700  778.600 63.700  778.600 104.100  781.200 104.100  781.200 63.700  784.800 63.700  784.800 87.100  787.400 87.100  787.400 63.700  795.900 63.700  795.900 76.700  798.500 76.700  798.500 63.700  800.200 63.700  800.200 104.100  802.800 104.100  802.800 63.700  806.400 63.700  806.400 87.100  809.000 87.100  809.000 63.700  811.000 63.700  811.000 104.100  813.600 104.100  813.600 63.700  817.200 63.700  817.200 87.100  819.800 87.100  819.800 63.700  828.300 63.700  828.300 76.700  830.900 76.700  830.900 63.700  832.600 63.700  832.600 104.100  835.200 104.100  835.200 63.700  838.800 63.700  838.800 87.100  841.400 87.100  841.400 63.700  843.400 63.700  843.400 104.100  846.000 104.100  846.000 63.700  849.600 63.700  849.600 87.100  852.200 87.100  852.200 63.700  860.700 63.700  860.700 76.700  863.300 76.700  863.300 63.700  865.000 63.700  865.000 104.100  867.600 104.100  867.600 63.700  871.200 63.700  871.200 87.100  873.800 87.100  873.800 63.700  875.800 63.700  875.800 104.100  878.400 104.100  878.400 63.700  882.000 63.700  882.000 87.100  884.600 87.100  884.600 63.700  893.100 63.700  893.100 76.700  895.700 76.700  895.700 63.700  897.400 63.700  897.400 104.100  900.000 104.100  900.000 63.700  903.600 63.700  903.600 87.100  906.200 87.100  906.200 63.700  908.200 63.700  908.200 104.100  910.800 104.100  910.800 63.700  914.400 63.700  914.400 87.100  917.000 87.100  917.000 63.700  925.500 63.700  925.500 76.700  928.100 76.700  928.100 63.700  929.800 63.700  929.800 104.100  932.400 104.100  932.400 63.700  936.000 63.700  936.000 87.100  938.600 87.100  938.600 63.700  940.600 63.700  940.600 104.100  943.200 104.100  943.200 63.700  946.800 63.700  946.800 87.100  949.400 87.100  949.400 63.700  957.900 63.700  957.900 76.700  960.500 76.700  960.500 63.700  962.200 63.700  962.200 104.100  964.800 104.100  964.800 63.700  968.400 63.700  968.400 87.100  971.000 87.100  971.000 63.700  973.000 63.700  973.000 104.100  975.600 104.100  975.600 63.700  979.200 63.700  979.200 87.100  981.800 87.100  981.800 63.700  990.300 63.700  990.300 76.700  992.900 76.700  992.900 63.700  994.600 63.700  994.600 104.100  997.200 104.100  997.200 63.700  1000.800 63.700  1000.800 87.100  1003.400 87.100  1003.400 63.700  1005.400 63.700  1005.400 104.100  1008.000 104.100  1008.000 63.700  1011.600 63.700  1011.600 87.100  1014.200 87.100  1014.200 63.700  1022.700 63.700  1022.700 76.700  1025.300 76.700  1025.300 63.700  1027.000 63.700  1027.000 104.100  1029.600 104.100  1029.600 63.700  1033.200 63.700  1033.200 87.100  1035.800 87.100  1035.800 63.700  1037.800 63.700  1037.800 104.100  1040.400 104.100  1040.400 63.700  1044.000 63.700  1044.000 87.100  1046.600 87.100  1046.600 63.700  1055.100 63.700  1055.100 76.700  1057.700 76.700  1057.700 63.700  1059.400 63.700  1059.400 104.100  1062.000 104.100  1062.000 63.700  1065.600 63.700  1065.600 87.100  1068.200 87.100  1068.200 63.700  1070.200 63.700  1070.200 104.100  1072.800 104.100  1072.800 63.700  1076.400 63.700  1076.400 87.100  1079.000 87.100  1079.000 63.700  1087.500 63.700  1087.500 76.700  1090.100 76.700  1090.100 63.700  1091.800 63.700  1091.800 104.100  1094.400 104.100  1094.400 63.700  1098.000 63.700  1098.000 87.100  1100.600 87.100  1100.600 63.700  1102.600 63.700  1102.600 104.100  1105.200 104.100  1105.200 63.700  1108.800 63.700  1108.800 87.100  1111.400 87.100  1111.400 63.700  1119.900 63.700  1119.900 76.700  1122.500 76.700  1122.500 63.700  1124.200 63.700  1124.200 104.100  1126.800 104.100  1126.800 63.700  1130.400 63.700  1130.400 87.100  1133.000 87.100  1133.000 63.700  1135.000 63.700  1135.000 104.100  1137.600 104.100  1137.600 63.700  1141.200 63.700  1141.200 87.100  1143.800 87.100  1143.800 63.700  1152.300 63.700  1152.300 76.700  1154.900 76.700  1154.900 63.700  1156.600 63.700  1156.600 104.100  1159.200 104.100  1159.200 63.700  1162.800 63.700  1162.800 87.100  1165.400 87.100  1165.400 63.700  1167.400 63.700  1167.400 104.100  1170.000 104.100  1170.000 63.700  1173.600 63.700  1173.600 87.100  1176.200 87.100  1176.200 63.700  1184.700 63.700  1184.700 76.700  1187.300 76.700  1187.300 63.700  1189.000 63.700  1189.000 104.100  1191.600 104.100  1191.600 63.700  1195.200 63.700  1195.200 87.100  1197.800 87.100  1197.800 63.700  1199.800 63.700  1199.800 104.100  1202.400 104.100  1202.400 63.700  1206.000 63.700  1206.000 87.100  1208.600 87.100  1208.600 63.700  1217.100 63.700  1217.100 76.700  1219.700 76.700  1219.700 63.700  1221.400 63.700  1221.400 104.100  1224.000 104.100  1224.000 63.700  1227.600 63.700  1227.600 87.100  1230.200 87.100  1230.200 63.700  1232.200 63.700  1232.200 104.100  1234.800 104.100  1234.800 63.700  1238.400 63.700  1238.400 87.100  1241.000 87.100  1241.000 63.700  1249.500 63.700  1249.500 76.700  1252.100 76.700  1252.100 63.700  1253.800 63.700  1253.800 104.100  1256.400 104.100  1256.400 63.700  1260.000 63.700  1260.000 87.100  1262.600 87.100  1262.600 63.700  1264.600 63.700  1264.600 104.100  1267.200 104.100  1267.200 63.700  1270.800 63.700  1270.800 87.100  1273.400 87.100  1273.400 63.700  1281.900 63.700  1281.900 76.700  1284.500 76.700  1284.500 63.700  1286.200 63.700  1286.200 104.100  1288.800 104.100  1288.800 63.700  1292.400 63.700  1292.400 87.100  1295.000 87.100  1295.000 63.700  1297.000 63.700  1297.000 104.100  1299.600 104.100  1299.600 63.700  1303.200 63.700  1303.200 87.100  1305.800 87.100  1305.800 63.700  1314.300 63.700  1314.300 76.700  1316.900 76.700  1316.900 63.700  1318.600 63.700  1318.600 104.100  1321.200 104.100  1321.200 63.700  1324.800 63.700  1324.800 87.100  1327.400 87.100  1327.400 63.700  1329.400 63.700  1329.400 104.100  1332.000 104.100  1332.000 63.700  1335.600 63.700  1335.600 87.100  1338.200 87.100  1338.200 63.700  1346.700 63.700  1346.700 76.700  1349.300 76.700  1349.300 63.700  1351.000 63.700  1351.000 104.100  1353.600 104.100  1353.600 63.700  1357.200 63.700  1357.200 87.100  1359.800 87.100  1359.800 63.700  1361.800 63.700  1361.800 104.100  1364.400 104.100  1364.400 63.700  1368.000 63.700  1368.000 87.100  1370.600 87.100  1370.600 63.700  1379.100 63.700  1379.100 76.700  1381.700 76.700  1381.700 63.700  1383.400 63.700  1383.400 104.100  1386.000 104.100  1386.000 63.700  1389.600 63.700  1389.600 87.100  1392.200 87.100  1392.200 63.700  1394.200 63.700  1394.200 104.100  1396.800 104.100  1396.800 63.700  1400.400 63.700  1400.400 87.100  1403.000 87.100  1403.000 63.700  1411.500 63.700  1411.500 76.700  1414.100 76.700  1414.100 63.700  1415.800 63.700  1415.800 104.100  1418.400 104.100  1418.400 63.700  1422.000 63.700  1422.000 87.100  1424.600 87.100  1424.600 63.700  1426.600 63.700  1426.600 104.100  1429.200 104.100  1429.200 63.700  1432.800 63.700  1432.800 87.100  1435.400 87.100  1435.400 63.700  1443.900 63.700  1443.900 76.700  1446.500 76.700  1446.500 63.700  1448.200 63.700  1448.200 104.100  1450.800 104.100  1450.800 63.700  1454.400 63.700  1454.400 87.100  1457.000 87.100  1457.000 63.700  1459.000 63.700  1459.000 104.100  1461.600 104.100  1461.600 63.700  1465.200 63.700  1465.200 87.100  1467.800 87.100  1467.800 63.700  1476.300 63.700  1476.300 76.700  1478.900 76.700  1478.900 63.700  1480.600 63.700  1480.600 104.100  1483.200 104.100  1483.200 63.700  1486.800 63.700  1486.800 87.100  1489.400 87.100  1489.400 63.700  1491.400 63.700  1491.400 104.100  1494.000 104.100  1494.000 63.700  1497.600 63.700  1497.600 87.100  1500.200 87.100  1500.200 63.700  1508.700 63.700  1508.700 76.700  1511.300 76.700  1511.300 63.700  1513.000 63.700  1513.000 104.100  1515.600 104.100  1515.600 63.700  1519.200 63.700  1519.200 87.100  1521.800 87.100  1521.800 63.700  1523.800 63.700  1523.800 104.100  1526.400 104.100  1526.400 63.700  1530.000 63.700  1530.000 87.100  1532.600 87.100  1532.600 63.700  1541.100 63.700  1541.100 76.700  1543.700 76.700  1543.700 63.700  1545.400 63.700  1545.400 104.100  1548.000 104.100  1548.000 63.700  1551.600 63.700  1551.600 87.100  1554.200 87.100  1554.200 63.700  1556.200 63.700  1556.200 104.100  1558.800 104.100  1558.800 63.700  1562.400 63.700  1562.400 87.100  1565.000 87.100  1565.000 63.700  1573.500 63.700  1573.500 76.700  1576.100 76.700  1576.100 63.700  1577.800 63.700  1577.800 104.100  1580.400 104.100  1580.400 63.700  1584.000 63.700  1584.000 87.100  1586.600 87.100  1586.600 63.700  1588.600 63.700  1588.600 104.100  1591.200 104.100  1591.200 63.700  1594.800 63.700  1594.800 87.100  1597.400 87.100  1597.400 63.700  1605.900 63.700  1605.900 76.700  1608.500 76.700  1608.500 63.700  1615.600 63.700  1615.600 66.300  1619.000 66.300  1619.000 63.700  1617.400 63.700  1617.400 61.100  1619.000 61.100  1619.000 58.500  1615.600 58.500  1615.600 61.100  1601.700 61.100  1601.700 48.100  1599.100 48.100  1599.100 61.100  1597.400 61.100  1597.400 20.700  1594.800 20.700  1594.800 61.100  1591.200 61.100  1591.200 37.700  1588.600 37.700  1588.600 61.100  1586.600 61.100  1586.600 20.700  1584.000 20.700  1584.000 61.100  1580.400 61.100  1580.400 37.700  1577.800 37.700  1577.800 61.100  1575.800 61.100  1575.800 20.700  1573.200 20.700  1573.200 61.100  1569.600 61.100  1569.600 37.700  1567.000 37.700  1567.000 61.100  1565.000 61.100  1565.000 20.700  1562.400 20.700  1562.400 61.100  1558.800 61.100  1558.800 37.700  1556.200 37.700  1556.200 61.100  1554.200 61.100  1554.200 20.700  1551.600 20.700  1551.600 61.100  1548.000 61.100  1548.000 37.700  1545.400 37.700  1545.400 61.100  1543.400 61.100  1543.400 20.700  1540.800 20.700  1540.800 61.100  1537.200 61.100  1537.200 37.700  1534.600 37.700  1534.600 61.100  1523.300 61.100  1523.300 48.100  1520.700 48.100  1520.700 61.100  1515.300 61.100  1515.300 48.100  1512.700 48.100  1512.700 61.100  1511.000 61.100  1511.000 20.700  1508.400 20.700  1508.400 61.100  1504.800 61.100  1504.800 37.700  1502.200 37.700  1502.200 61.100  1500.200 61.100  1500.200 20.700  1497.600 20.700  1497.600 61.100  1494.000 61.100  1494.000 37.700  1491.400 37.700  1491.400 61.100  1482.900 61.100  1482.900 48.100  1480.300 48.100  1480.300 61.100  1478.600 61.100  1478.600 20.700  1476.000 20.700  1476.000 61.100  1472.400 61.100  1472.400 37.700  1469.800 37.700  1469.800 61.100  1467.800 61.100  1467.800 20.700  1465.200 20.700  1465.200 61.100  1461.600 61.100  1461.600 37.700  1459.000 37.700  1459.000 61.100  1450.500 61.100  1450.500 48.100  1447.900 48.100  1447.900 61.100  1446.200 61.100  1446.200 20.700  1443.600 20.700  1443.600 61.100  1440.000 61.100  1440.000 37.700  1437.400 37.700  1437.400 61.100  1435.400 61.100  1435.400 20.700  1432.800 20.700  1432.800 61.100  1429.200 61.100  1429.200 37.700  1426.600 37.700  1426.600 61.100  1418.100 61.100  1418.100 48.100  1415.500 48.100  1415.500 61.100  1413.800 61.100  1413.800 20.700  1411.200 20.700  1411.200 61.100  1407.600 61.100  1407.600 37.700  1405.000 37.700  1405.000 61.100  1403.000 61.100  1403.000 20.700  1400.400 20.700  1400.400 61.100  1396.800 61.100  1396.800 37.700  1394.200 37.700  1394.200 61.100  1385.700 61.100  1385.700 48.100  1383.100 48.100  1383.100 61.100  1381.400 61.100  1381.400 20.700  1378.800 20.700  1378.800 61.100  1375.200 61.100  1375.200 37.700  1372.600 37.700  1372.600 61.100  1370.600 61.100  1370.600 20.700  1368.000 20.700  1368.000 61.100  1364.400 61.100  1364.400 37.700  1361.800 37.700  1361.800 61.100  1353.300 61.100  1353.300 48.100  1350.700 48.100  1350.700 61.100  1349.000 61.100  1349.000 20.700  1346.400 20.700  1346.400 61.100  1342.800 61.100  1342.800 37.700  1340.200 37.700  1340.200 61.100  1338.200 61.100  1338.200 20.700  1335.600 20.700  1335.600 61.100  1332.000 61.100  1332.000 37.700  1329.400 37.700  1329.400 61.100  1320.900 61.100  1320.900 48.100  1318.300 48.100  1318.300 61.100  1316.600 61.100  1316.600 20.700  1314.000 20.700  1314.000 61.100  1310.400 61.100  1310.400 37.700  1307.800 37.700  1307.800 61.100  1305.800 61.100  1305.800 20.700  1303.200 20.700  1303.200 61.100  1299.600 61.100  1299.600 37.700  1297.000 37.700  1297.000 61.100  1288.500 61.100  1288.500 48.100  1285.900 48.100  1285.900 61.100  1284.200 61.100  1284.200 20.700  1281.600 20.700  1281.600 61.100  1278.000 61.100  1278.000 37.700  1275.400 37.700  1275.400 61.100  1273.400 61.100  1273.400 20.700  1270.800 20.700  1270.800 61.100  1267.200 61.100  1267.200 37.700  1264.600 37.700  1264.600 61.100  1256.100 61.100  1256.100 48.100  1253.500 48.100  1253.500 61.100  1251.800 61.100  1251.800 20.700  1249.200 20.700  1249.200 61.100  1245.600 61.100  1245.600 37.700  1243.000 37.700  1243.000 61.100  1241.000 61.100  1241.000 20.700  1238.400 20.700  1238.400 61.100  1234.800 61.100  1234.800 37.700  1232.200 37.700  1232.200 61.100  1223.700 61.100  1223.700 48.100  1221.100 48.100  1221.100 61.100  1219.400 61.100  1219.400 20.700  1216.800 20.700  1216.800 61.100  1213.200 61.100  1213.200 37.700  1210.600 37.700  1210.600 61.100  1208.600 61.100  1208.600 20.700  1206.000 20.700  1206.000 61.100  1202.400 61.100  1202.400 37.700  1199.800 37.700  1199.800 61.100  1191.300 61.100  1191.300 48.100  1188.700 48.100  1188.700 61.100  1187.000 61.100  1187.000 20.700  1184.400 20.700  1184.400 61.100  1180.800 61.100  1180.800 37.700  1178.200 37.700  1178.200 61.100  1176.200 61.100  1176.200 20.700  1173.600 20.700  1173.600 61.100  1170.000 61.100  1170.000 37.700  1167.400 37.700  1167.400 61.100  1158.900 61.100  1158.900 48.100  1156.300 48.100  1156.300 61.100  1154.600 61.100  1154.600 20.700  1152.000 20.700  1152.000 61.100  1148.400 61.100  1148.400 37.700  1145.800 37.700  1145.800 61.100  1143.800 61.100  1143.800 20.700  1141.200 20.700  1141.200 61.100  1137.600 61.100  1137.600 37.700  1135.000 37.700  1135.000 61.100  1126.500 61.100  1126.500 48.100  1123.900 48.100  1123.900 61.100  1122.200 61.100  1122.200 20.700  1119.600 20.700  1119.600 61.100  1116.000 61.100  1116.000 37.700  1113.400 37.700  1113.400 61.100  1111.400 61.100  1111.400 20.700  1108.800 20.700  1108.800 61.100  1105.200 61.100  1105.200 37.700  1102.600 37.700  1102.600 61.100  1094.100 61.100  1094.100 48.100  1091.500 48.100  1091.500 61.100  1089.800 61.100  1089.800 20.700  1087.200 20.700  1087.200 61.100  1083.600 61.100  1083.600 37.700  1081.000 37.700  1081.000 61.100  1079.000 61.100  1079.000 20.700  1076.400 20.700  1076.400 61.100  1072.800 61.100  1072.800 37.700  1070.200 37.700  1070.200 61.100  1061.700 61.100  1061.700 48.100  1059.100 48.100  1059.100 61.100  1057.400 61.100  1057.400 20.700  1054.800 20.700  1054.800 61.100  1051.200 61.100  1051.200 37.700  1048.600 37.700  1048.600 61.100  1046.600 61.100  1046.600 20.700  1044.000 20.700  1044.000 61.100  1040.400 61.100  1040.400 37.700  1037.800 37.700  1037.800 61.100  1029.300 61.100  1029.300 48.100  1026.700 48.100  1026.700 61.100  1025.000 61.100  1025.000 20.700  1022.400 20.700  1022.400 61.100  1018.800 61.100  1018.800 37.700  1016.200 37.700  1016.200 61.100  1014.200 61.100  1014.200 20.700  1011.600 20.700  1011.600 61.100  1008.000 61.100  1008.000 37.700  1005.400 37.700  1005.400 61.100  996.900 61.100  996.900 48.100  994.300 48.100  994.300 61.100  992.600 61.100  992.600 20.700  990.000 20.700  990.000 61.100  986.400 61.100  986.400 37.700  983.800 37.700  983.800 61.100  981.800 61.100  981.800 20.700  979.200 20.700  979.200 61.100  975.600 61.100  975.600 37.700  973.000 37.700  973.000 61.100  964.500 61.100  964.500 48.100  961.900 48.100  961.900 61.100  960.200 61.100  960.200 20.700  957.600 20.700  957.600 61.100  954.000 61.100  954.000 37.700  951.400 37.700  951.400 61.100  949.400 61.100  949.400 20.700  946.800 20.700  946.800 61.100  943.200 61.100  943.200 37.700  940.600 37.700  940.600 61.100  932.100 61.100  932.100 48.100  929.500 48.100  929.500 61.100  927.800 61.100  927.800 20.700  925.200 20.700  925.200 61.100  921.600 61.100  921.600 37.700  919.000 37.700  919.000 61.100  917.000 61.100  917.000 20.700  914.400 20.700  914.400 61.100  910.800 61.100  910.800 37.700  908.200 37.700  908.200 61.100  899.700 61.100  899.700 48.100  897.100 48.100  897.100 61.100  895.400 61.100  895.400 20.700  892.800 20.700  892.800 61.100  889.200 61.100  889.200 37.700  886.600 37.700  886.600 61.100  884.600 61.100  884.600 20.700  882.000 20.700  882.000 61.100  878.400 61.100  878.400 37.700  875.800 37.700  875.800 61.100  867.300 61.100  867.300 48.100  864.700 48.100  864.700 61.100  863.000 61.100  863.000 20.700  860.400 20.700  860.400 61.100  856.800 61.100  856.800 37.700  854.200 37.700  854.200 61.100  852.200 61.100  852.200 20.700  849.600 20.700  849.600 61.100  846.000 61.100  846.000 37.700  843.400 37.700  843.400 61.100  834.900 61.100  834.900 48.100  832.300 48.100  832.300 61.100  830.600 61.100  830.600 20.700  828.000 20.700  828.000 61.100  824.400 61.100  824.400 37.700  821.800 37.700  821.800 61.100  819.800 61.100  819.800 20.700  817.200 20.700  817.200 61.100  813.600 61.100  813.600 37.700  811.000 37.700  811.000 61.100  802.500 61.100  802.500 48.100  799.900 48.100  799.900 61.100  798.200 61.100  798.200 20.700  795.600 20.700  795.600 61.100  792.000 61.100  792.000 37.700  789.400 37.700  789.400 61.100  787.400 61.100  787.400 20.700  784.800 20.700  784.800 61.100  781.200 61.100  781.200 37.700  778.600 37.700  778.600 61.100  770.100 61.100  770.100 48.100  767.500 48.100  767.500 61.100  765.800 61.100  765.800 20.700  763.200 20.700  763.200 61.100  759.600 61.100  759.600 37.700  757.000 37.700  757.000 61.100  755.000 61.100  755.000 20.700  752.400 20.700  752.400 61.100  748.800 61.100  748.800 37.700  746.200 37.700  746.200 61.100  737.700 61.100  737.700 48.100  735.100 48.100  735.100 61.100  733.400 61.100  733.400 20.700  730.800 20.700  730.800 61.100  727.200 61.100  727.200 37.700  724.600 37.700  724.600 61.100  722.600 61.100  722.600 20.700  720.000 20.700  720.000 61.100  716.400 61.100  716.400 37.700  713.800 37.700  713.800 61.100  705.300 61.100  705.300 48.100  702.700 48.100  702.700 61.100  701.000 61.100  701.000 20.700  698.400 20.700  698.400 61.100  694.800 61.100  694.800 37.700  692.200 37.700  692.200 61.100  690.200 61.100  690.200 20.700  687.600 20.700  687.600 61.100  684.000 61.100  684.000 37.700  681.400 37.700  681.400 61.100  672.900 61.100  672.900 48.100  670.300 48.100  670.300 61.100  668.600 61.100  668.600 20.700  666.000 20.700  666.000 61.100  662.400 61.100  662.400 37.700  659.800 37.700  659.800 61.100  657.800 61.100  657.800 20.700  655.200 20.700  655.200 61.100  651.600 61.100  651.600 37.700  649.000 37.700  649.000 61.100  640.500 61.100  640.500 48.100  637.900 48.100  637.900 61.100  636.200 61.100  636.200 20.700  633.600 20.700  633.600 61.100  630.000 61.100  630.000 37.700  627.400 37.700  627.400 61.100  625.400 61.100  625.400 20.700  622.800 20.700  622.800 61.100  619.200 61.100  619.200 37.700  616.600 37.700  616.600 61.100  608.100 61.100  608.100 48.100  605.500 48.100  605.500 61.100  603.800 61.100  603.800 20.700  601.200 20.700  601.200 61.100  597.600 61.100  597.600 37.700  595.000 37.700  595.000 61.100  593.000 61.100  593.000 20.700  590.400 20.700  590.400 61.100  586.800 61.100  586.800 37.700  584.200 37.700  584.200 61.100  575.700 61.100  575.700 48.100  573.100 48.100  573.100 61.100  571.400 61.100  571.400 20.700  568.800 20.700  568.800 61.100  565.200 61.100  565.200 37.700  562.600 37.700  562.600 61.100  560.600 61.100  560.600 20.700  558.000 20.700  558.000 61.100  554.400 61.100  554.400 37.700  551.800 37.700  551.800 61.100  543.300 61.100  543.300 48.100  540.700 48.100  540.700 61.100  539.000 61.100  539.000 20.700  536.400 20.700  536.400 61.100  532.800 61.100  532.800 37.700  530.200 37.700  530.200 61.100  528.200 61.100  528.200 20.700  525.600 20.700  525.600 61.100  522.000 61.100  522.000 37.700  519.400 37.700  519.400 61.100  510.900 61.100  510.900 48.100  508.300 48.100  508.300 61.100  506.600 61.100  506.600 20.700  504.000 20.700  504.000 61.100  500.400 61.100  500.400 37.700  497.800 37.700  497.800 61.100  495.800 61.100  495.800 20.700  493.200 20.700  493.200 61.100  489.600 61.100  489.600 37.700  487.000 37.700  487.000 61.100  478.500 61.100  478.500 48.100  475.900 48.100  475.900 61.100  474.200 61.100  474.200 20.700  471.600 20.700  471.600 61.100  468.000 61.100  468.000 37.700  465.400 37.700  465.400 61.100  463.400 61.100  463.400 20.700  460.800 20.700  460.800 61.100  457.200 61.100  457.200 37.700  454.600 37.700  454.600 61.100  446.100 61.100  446.100 48.100  443.500 48.100  443.500 61.100  441.800 61.100  441.800 20.700  439.200 20.700  439.200 61.100  435.600 61.100  435.600 37.700  433.000 37.700  433.000 61.100  431.000 61.100  431.000 20.700  428.400 20.700  428.400 61.100  424.800 61.100  424.800 37.700  422.200 37.700  422.200 61.100  413.700 61.100  413.700 48.100  411.100 48.100  411.100 61.100  409.400 61.100  409.400 20.700  406.800 20.700  406.800 61.100  403.200 61.100  403.200 37.700  400.600 37.700  400.600 61.100  398.600 61.100  398.600 20.700  396.000 20.700  396.000 61.100  392.400 61.100  392.400 37.700  389.800 37.700  389.800 61.100  381.300 61.100  381.300 48.100  378.700 48.100  378.700 61.100  377.000 61.100  377.000 20.700  374.400 20.700  374.400 61.100  370.800 61.100  370.800 37.700  368.200 37.700  368.200 61.100  366.200 61.100  366.200 20.700  363.600 20.700  363.600 61.100  360.000 61.100  360.000 37.700  357.400 37.700  357.400 61.100  348.900 61.100  348.900 48.100  346.300 48.100  346.300 61.100  344.600 61.100  344.600 20.700  342.000 20.700  342.000 61.100  338.400 61.100  338.400 37.700  335.800 37.700  335.800 61.100  333.800 61.100  333.800 20.700  331.200 20.700  331.200 61.100  327.600 61.100  327.600 37.700  325.000 37.700  325.000 61.100  316.500 61.100  316.500 48.100  313.900 48.100  313.900 61.100  312.200 61.100  312.200 20.700  309.600 20.700  309.600 61.100  306.000 61.100  306.000 37.700  303.400 37.700  303.400 61.100  301.400 61.100  301.400 20.700  298.800 20.700  298.800 61.100  295.200 61.100  295.200 37.700  292.600 37.700  292.600 61.100  284.100 61.100  284.100 48.100  281.500 48.100  281.500 61.100  279.800 61.100  279.800 20.700  277.200 20.700  277.200 61.100  273.600 61.100  273.600 37.700  271.000 37.700  271.000 61.100  269.000 61.100  269.000 20.700  266.400 20.700  266.400 61.100  262.800 61.100  262.800 37.700  260.200 37.700  260.200 61.100  251.700 61.100  251.700 48.100  249.100 48.100  249.100 61.100  247.400 61.100  247.400 20.700  244.800 20.700  244.800 61.100  241.200 61.100  241.200 37.700  238.600 37.700  238.600 61.100  236.600 61.100  236.600 20.700  234.000 20.700  234.000 61.100  230.400 61.100  230.400 37.700  227.800 37.700  227.800 61.100  219.300 61.100  219.300 48.100  216.700 48.100  216.700 61.100  215.000 61.100  215.000 20.700  212.400 20.700  212.400 61.100  208.800 61.100  208.800 37.700  206.200 37.700  206.200 61.100  204.200 61.100  204.200 20.700  201.600 20.700  201.600 61.100  198.000 61.100  198.000 37.700  195.400 37.700  195.400 61.100  186.900 61.100  186.900 48.100  184.300 48.100  184.300 61.100  182.600 61.100  182.600 20.700  180.000 20.700  180.000 61.100  176.400 61.100  176.400 37.700  173.800 37.700  173.800 61.100  171.800 61.100  171.800 20.700  169.200 20.700  169.200 61.100  165.600 61.100  165.600 37.700  163.000 37.700  163.000 61.100  154.500 61.100  154.500 48.100  151.900 48.100  151.900 61.100  150.200 61.100  150.200 20.700  147.600 20.700  147.600 61.100  144.000 61.100  144.000 37.700  141.400 37.700  141.400 61.100  139.400 61.100  139.400 20.700  136.800 20.700  136.800 61.100  133.200 61.100  133.200 37.700  130.600 37.700  130.600 61.100  122.100 61.100  122.100 48.100  119.500 48.100  119.500 61.100  117.800 61.100  117.800 20.700  115.200 20.700  115.200 61.100  111.600 61.100  111.600 37.700  109.000 37.700  109.000 61.100  107.000 61.100  107.000 20.700  104.400 20.700  104.400 61.100  100.800 61.100  100.800 37.700  98.200 37.700  98.200 61.100  89.700 61.100  89.700 48.100  87.100 48.100  87.100 61.100  85.400 61.100  85.400 20.700  82.800 20.700  82.800 61.100  79.200 61.100  79.200 37.700  76.600 37.700  76.600 61.100  74.600 61.100  74.600 20.700  72.000 20.700  72.000 61.100  68.400 61.100  68.400 37.700  65.800 37.700  65.800 61.100  57.300 61.100  57.300 48.100  54.700 48.100  54.700 61.100  53.000 61.100  53.000 20.700  50.400 20.700  50.400 61.100  46.800 61.100  46.800 37.700  44.200 37.700  44.200 61.100  42.200 61.100  42.200 20.700  39.600 20.700  39.600 61.100  36.000 61.100  36.000 37.700  33.400 37.700  33.400 61.100  24.900 61.100  24.900 48.100  22.300 48.100  22.300 61.100  20.600 61.100  20.600 20.700 ;
            POLYGON 18.000 88.700  18.000 121.100  14.400 121.100  14.400 105.700  11.800 105.700  11.800 121.100  4.400 121.100  4.400 118.500  1.000 118.500  1.000 121.100  2.600 121.100  2.600 123.700  1617.400 123.700  1617.400 121.100  1613.600 121.100  1613.600 118.500  1610.200 118.500  1610.200 121.100  1607.100 121.100  1607.100 114.900  1604.500 114.900  1604.500 121.100  1597.400 121.100  1597.400 88.700  1594.800 88.700  1594.800 121.100  1591.200 121.100  1591.200 105.700  1588.600 105.700  1588.600 121.100  1586.600 121.100  1586.600 88.700  1584.000 88.700  1584.000 121.100  1580.400 121.100  1580.400 105.700  1577.800 105.700  1577.800 121.100  1574.700 121.100  1574.700 114.900  1572.100 114.900  1572.100 121.100  1565.000 121.100  1565.000 88.700  1562.400 88.700  1562.400 121.100  1558.800 121.100  1558.800 105.700  1556.200 105.700  1556.200 121.100  1554.200 121.100  1554.200 88.700  1551.600 88.700  1551.600 121.100  1548.000 121.100  1548.000 105.700  1545.400 105.700  1545.400 121.100  1542.300 121.100  1542.300 114.900  1539.700 114.900  1539.700 121.100  1532.600 121.100  1532.600 88.700  1530.000 88.700  1530.000 121.100  1526.400 121.100  1526.400 105.700  1523.800 105.700  1523.800 121.100  1521.800 121.100  1521.800 88.700  1519.200 88.700  1519.200 121.100  1515.600 121.100  1515.600 105.700  1513.000 105.700  1513.000 121.100  1509.900 121.100  1509.900 114.900  1507.300 114.900  1507.300 121.100  1500.200 121.100  1500.200 88.700  1497.600 88.700  1497.600 121.100  1494.000 121.100  1494.000 105.700  1491.400 105.700  1491.400 121.100  1489.400 121.100  1489.400 88.700  1486.800 88.700  1486.800 121.100  1483.200 121.100  1483.200 105.700  1480.600 105.700  1480.600 121.100  1477.500 121.100  1477.500 114.900  1474.900 114.900  1474.900 121.100  1467.800 121.100  1467.800 88.700  1465.200 88.700  1465.200 121.100  1461.600 121.100  1461.600 105.700  1459.000 105.700  1459.000 121.100  1457.000 121.100  1457.000 88.700  1454.400 88.700  1454.400 121.100  1450.800 121.100  1450.800 105.700  1448.200 105.700  1448.200 121.100  1445.100 121.100  1445.100 114.900  1442.500 114.900  1442.500 121.100  1435.400 121.100  1435.400 88.700  1432.800 88.700  1432.800 121.100  1429.200 121.100  1429.200 105.700  1426.600 105.700  1426.600 121.100  1424.600 121.100  1424.600 88.700  1422.000 88.700  1422.000 121.100  1418.400 121.100  1418.400 105.700  1415.800 105.700  1415.800 121.100  1412.700 121.100  1412.700 114.900  1410.100 114.900  1410.100 121.100  1403.000 121.100  1403.000 88.700  1400.400 88.700  1400.400 121.100  1396.800 121.100  1396.800 105.700  1394.200 105.700  1394.200 121.100  1392.200 121.100  1392.200 88.700  1389.600 88.700  1389.600 121.100  1386.000 121.100  1386.000 105.700  1383.400 105.700  1383.400 121.100  1380.300 121.100  1380.300 114.900  1377.700 114.900  1377.700 121.100  1370.600 121.100  1370.600 88.700  1368.000 88.700  1368.000 121.100  1364.400 121.100  1364.400 105.700  1361.800 105.700  1361.800 121.100  1359.800 121.100  1359.800 88.700  1357.200 88.700  1357.200 121.100  1353.600 121.100  1353.600 105.700  1351.000 105.700  1351.000 121.100  1347.900 121.100  1347.900 114.900  1345.300 114.900  1345.300 121.100  1338.200 121.100  1338.200 88.700  1335.600 88.700  1335.600 121.100  1332.000 121.100  1332.000 105.700  1329.400 105.700  1329.400 121.100  1327.400 121.100  1327.400 88.700  1324.800 88.700  1324.800 121.100  1321.200 121.100  1321.200 105.700  1318.600 105.700  1318.600 121.100  1315.500 121.100  1315.500 114.900  1312.900 114.900  1312.900 121.100  1305.800 121.100  1305.800 88.700  1303.200 88.700  1303.200 121.100  1299.600 121.100  1299.600 105.700  1297.000 105.700  1297.000 121.100  1295.000 121.100  1295.000 88.700  1292.400 88.700  1292.400 121.100  1288.800 121.100  1288.800 105.700  1286.200 105.700  1286.200 121.100  1283.100 121.100  1283.100 114.900  1280.500 114.900  1280.500 121.100  1273.400 121.100  1273.400 88.700  1270.800 88.700  1270.800 121.100  1267.200 121.100  1267.200 105.700  1264.600 105.700  1264.600 121.100  1262.600 121.100  1262.600 88.700  1260.000 88.700  1260.000 121.100  1256.400 121.100  1256.400 105.700  1253.800 105.700  1253.800 121.100  1250.700 121.100  1250.700 114.900  1248.100 114.900  1248.100 121.100  1241.000 121.100  1241.000 88.700  1238.400 88.700  1238.400 121.100  1234.800 121.100  1234.800 105.700  1232.200 105.700  1232.200 121.100  1230.200 121.100  1230.200 88.700  1227.600 88.700  1227.600 121.100  1224.000 121.100  1224.000 105.700  1221.400 105.700  1221.400 121.100  1218.300 121.100  1218.300 114.900  1215.700 114.900  1215.700 121.100  1208.600 121.100  1208.600 88.700  1206.000 88.700  1206.000 121.100  1202.400 121.100  1202.400 105.700  1199.800 105.700  1199.800 121.100  1197.800 121.100  1197.800 88.700  1195.200 88.700  1195.200 121.100  1191.600 121.100  1191.600 105.700  1189.000 105.700  1189.000 121.100  1185.900 121.100  1185.900 114.900  1183.300 114.900  1183.300 121.100  1176.200 121.100  1176.200 88.700  1173.600 88.700  1173.600 121.100  1170.000 121.100  1170.000 105.700  1167.400 105.700  1167.400 121.100  1165.400 121.100  1165.400 88.700  1162.800 88.700  1162.800 121.100  1159.200 121.100  1159.200 105.700  1156.600 105.700  1156.600 121.100  1153.500 121.100  1153.500 114.900  1150.900 114.900  1150.900 121.100  1143.800 121.100  1143.800 88.700  1141.200 88.700  1141.200 121.100  1137.600 121.100  1137.600 105.700  1135.000 105.700  1135.000 121.100  1133.000 121.100  1133.000 88.700  1130.400 88.700  1130.400 121.100  1126.800 121.100  1126.800 105.700  1124.200 105.700  1124.200 121.100  1121.100 121.100  1121.100 114.900  1118.500 114.900  1118.500 121.100  1111.400 121.100  1111.400 88.700  1108.800 88.700  1108.800 121.100  1105.200 121.100  1105.200 105.700  1102.600 105.700  1102.600 121.100  1100.600 121.100  1100.600 88.700  1098.000 88.700  1098.000 121.100  1094.400 121.100  1094.400 105.700  1091.800 105.700  1091.800 121.100  1088.700 121.100  1088.700 114.900  1086.100 114.900  1086.100 121.100  1079.000 121.100  1079.000 88.700  1076.400 88.700  1076.400 121.100  1072.800 121.100  1072.800 105.700  1070.200 105.700  1070.200 121.100  1068.200 121.100  1068.200 88.700  1065.600 88.700  1065.600 121.100  1062.000 121.100  1062.000 105.700  1059.400 105.700  1059.400 121.100  1056.300 121.100  1056.300 114.900  1053.700 114.900  1053.700 121.100  1046.600 121.100  1046.600 88.700  1044.000 88.700  1044.000 121.100  1040.400 121.100  1040.400 105.700  1037.800 105.700  1037.800 121.100  1035.800 121.100  1035.800 88.700  1033.200 88.700  1033.200 121.100  1029.600 121.100  1029.600 105.700  1027.000 105.700  1027.000 121.100  1023.900 121.100  1023.900 114.900  1021.300 114.900  1021.300 121.100  1014.200 121.100  1014.200 88.700  1011.600 88.700  1011.600 121.100  1008.000 121.100  1008.000 105.700  1005.400 105.700  1005.400 121.100  1003.400 121.100  1003.400 88.700  1000.800 88.700  1000.800 121.100  997.200 121.100  997.200 105.700  994.600 105.700  994.600 121.100  991.500 121.100  991.500 114.900  988.900 114.900  988.900 121.100  981.800 121.100  981.800 88.700  979.200 88.700  979.200 121.100  975.600 121.100  975.600 105.700  973.000 105.700  973.000 121.100  971.000 121.100  971.000 88.700  968.400 88.700  968.400 121.100  964.800 121.100  964.800 105.700  962.200 105.700  962.200 121.100  959.100 121.100  959.100 114.900  956.500 114.900  956.500 121.100  949.400 121.100  949.400 88.700  946.800 88.700  946.800 121.100  943.200 121.100  943.200 105.700  940.600 105.700  940.600 121.100  938.600 121.100  938.600 88.700  936.000 88.700  936.000 121.100  932.400 121.100  932.400 105.700  929.800 105.700  929.800 121.100  926.700 121.100  926.700 114.900  924.100 114.900  924.100 121.100  917.000 121.100  917.000 88.700  914.400 88.700  914.400 121.100  910.800 121.100  910.800 105.700  908.200 105.700  908.200 121.100  906.200 121.100  906.200 88.700  903.600 88.700  903.600 121.100  900.000 121.100  900.000 105.700  897.400 105.700  897.400 121.100  894.300 121.100  894.300 114.900  891.700 114.900  891.700 121.100  884.600 121.100  884.600 88.700  882.000 88.700  882.000 121.100  878.400 121.100  878.400 105.700  875.800 105.700  875.800 121.100  873.800 121.100  873.800 88.700  871.200 88.700  871.200 121.100  867.600 121.100  867.600 105.700  865.000 105.700  865.000 121.100  861.900 121.100  861.900 114.900  859.300 114.900  859.300 121.100  852.200 121.100  852.200 88.700  849.600 88.700  849.600 121.100  846.000 121.100  846.000 105.700  843.400 105.700  843.400 121.100  841.400 121.100  841.400 88.700  838.800 88.700  838.800 121.100  835.200 121.100  835.200 105.700  832.600 105.700  832.600 121.100  829.500 121.100  829.500 114.900  826.900 114.900  826.900 121.100  819.800 121.100  819.800 88.700  817.200 88.700  817.200 121.100  813.600 121.100  813.600 105.700  811.000 105.700  811.000 121.100  809.000 121.100  809.000 88.700  806.400 88.700  806.400 121.100  802.800 121.100  802.800 105.700  800.200 105.700  800.200 121.100  797.100 121.100  797.100 114.900  794.500 114.900  794.500 121.100  787.400 121.100  787.400 88.700  784.800 88.700  784.800 121.100  781.200 121.100  781.200 105.700  778.600 105.700  778.600 121.100  776.600 121.100  776.600 88.700  774.000 88.700  774.000 121.100  770.400 121.100  770.400 105.700  767.800 105.700  767.800 121.100  764.700 121.100  764.700 114.900  762.100 114.900  762.100 121.100  755.000 121.100  755.000 88.700  752.400 88.700  752.400 121.100  748.800 121.100  748.800 105.700  746.200 105.700  746.200 121.100  744.200 121.100  744.200 88.700  741.600 88.700  741.600 121.100  738.000 121.100  738.000 105.700  735.400 105.700  735.400 121.100  732.300 121.100  732.300 114.900  729.700 114.900  729.700 121.100  722.600 121.100  722.600 88.700  720.000 88.700  720.000 121.100  716.400 121.100  716.400 105.700  713.800 105.700  713.800 121.100  711.800 121.100  711.800 88.700  709.200 88.700  709.200 121.100  705.600 121.100  705.600 105.700  703.000 105.700  703.000 121.100  699.900 121.100  699.900 114.900  697.300 114.900  697.300 121.100  690.200 121.100  690.200 88.700  687.600 88.700  687.600 121.100  684.000 121.100  684.000 105.700  681.400 105.700  681.400 121.100  679.400 121.100  679.400 88.700  676.800 88.700  676.800 121.100  673.200 121.100  673.200 105.700  670.600 105.700  670.600 121.100  667.500 121.100  667.500 114.900  664.900 114.900  664.900 121.100  657.800 121.100  657.800 88.700  655.200 88.700  655.200 121.100  651.600 121.100  651.600 105.700  649.000 105.700  649.000 121.100  647.000 121.100  647.000 88.700  644.400 88.700  644.400 121.100  640.800 121.100  640.800 105.700  638.200 105.700  638.200 121.100  635.100 121.100  635.100 114.900  632.500 114.900  632.500 121.100  625.400 121.100  625.400 88.700  622.800 88.700  622.800 121.100  619.200 121.100  619.200 105.700  616.600 105.700  616.600 121.100  614.600 121.100  614.600 88.700  612.000 88.700  612.000 121.100  608.400 121.100  608.400 105.700  605.800 105.700  605.800 121.100  602.700 121.100  602.700 114.900  600.100 114.900  600.100 121.100  593.000 121.100  593.000 88.700  590.400 88.700  590.400 121.100  586.800 121.100  586.800 105.700  584.200 105.700  584.200 121.100  582.200 121.100  582.200 88.700  579.600 88.700  579.600 121.100  576.000 121.100  576.000 105.700  573.400 105.700  573.400 121.100  570.300 121.100  570.300 114.900  567.700 114.900  567.700 121.100  560.600 121.100  560.600 88.700  558.000 88.700  558.000 121.100  554.400 121.100  554.400 105.700  551.800 105.700  551.800 121.100  549.800 121.100  549.800 88.700  547.200 88.700  547.200 121.100  543.600 121.100  543.600 105.700  541.000 105.700  541.000 121.100  537.900 121.100  537.900 114.900  535.300 114.900  535.300 121.100  528.200 121.100  528.200 88.700  525.600 88.700  525.600 121.100  522.000 121.100  522.000 105.700  519.400 105.700  519.400 121.100  517.400 121.100  517.400 88.700  514.800 88.700  514.800 121.100  511.200 121.100  511.200 105.700  508.600 105.700  508.600 121.100  505.500 121.100  505.500 114.900  502.900 114.900  502.900 121.100  495.800 121.100  495.800 88.700  493.200 88.700  493.200 121.100  489.600 121.100  489.600 105.700  487.000 105.700  487.000 121.100  485.000 121.100  485.000 88.700  482.400 88.700  482.400 121.100  478.800 121.100  478.800 105.700  476.200 105.700  476.200 121.100  473.100 121.100  473.100 114.900  470.500 114.900  470.500 121.100  463.400 121.100  463.400 88.700  460.800 88.700  460.800 121.100  457.200 121.100  457.200 105.700  454.600 105.700  454.600 121.100  452.600 121.100  452.600 88.700  450.000 88.700  450.000 121.100  446.400 121.100  446.400 105.700  443.800 105.700  443.800 121.100  440.700 121.100  440.700 114.900  438.100 114.900  438.100 121.100  431.000 121.100  431.000 88.700  428.400 88.700  428.400 121.100  424.800 121.100  424.800 105.700  422.200 105.700  422.200 121.100  420.200 121.100  420.200 88.700  417.600 88.700  417.600 121.100  414.000 121.100  414.000 105.700  411.400 105.700  411.400 121.100  408.300 121.100  408.300 114.900  405.700 114.900  405.700 121.100  398.600 121.100  398.600 88.700  396.000 88.700  396.000 121.100  392.400 121.100  392.400 105.700  389.800 105.700  389.800 121.100  387.800 121.100  387.800 88.700  385.200 88.700  385.200 121.100  381.600 121.100  381.600 105.700  379.000 105.700  379.000 121.100  375.900 121.100  375.900 114.900  373.300 114.900  373.300 121.100  366.200 121.100  366.200 88.700  363.600 88.700  363.600 121.100  360.000 121.100  360.000 105.700  357.400 105.700  357.400 121.100  355.400 121.100  355.400 88.700  352.800 88.700  352.800 121.100  349.200 121.100  349.200 105.700  346.600 105.700  346.600 121.100  343.500 121.100  343.500 114.900  340.900 114.900  340.900 121.100  333.800 121.100  333.800 88.700  331.200 88.700  331.200 121.100  327.600 121.100  327.600 105.700  325.000 105.700  325.000 121.100  323.000 121.100  323.000 88.700  320.400 88.700  320.400 121.100  316.800 121.100  316.800 105.700  314.200 105.700  314.200 121.100  311.100 121.100  311.100 114.900  308.500 114.900  308.500 121.100  301.400 121.100  301.400 88.700  298.800 88.700  298.800 121.100  295.200 121.100  295.200 105.700  292.600 105.700  292.600 121.100  290.600 121.100  290.600 88.700  288.000 88.700  288.000 121.100  284.400 121.100  284.400 105.700  281.800 105.700  281.800 121.100  278.700 121.100  278.700 114.900  276.100 114.900  276.100 121.100  269.000 121.100  269.000 88.700  266.400 88.700  266.400 121.100  262.800 121.100  262.800 105.700  260.200 105.700  260.200 121.100  258.200 121.100  258.200 88.700  255.600 88.700  255.600 121.100  252.000 121.100  252.000 105.700  249.400 105.700  249.400 121.100  246.300 121.100  246.300 114.900  243.700 114.900  243.700 121.100  236.600 121.100  236.600 88.700  234.000 88.700  234.000 121.100  230.400 121.100  230.400 105.700  227.800 105.700  227.800 121.100  225.800 121.100  225.800 88.700  223.200 88.700  223.200 121.100  219.600 121.100  219.600 105.700  217.000 105.700  217.000 121.100  213.900 121.100  213.900 114.900  211.300 114.900  211.300 121.100  204.200 121.100  204.200 88.700  201.600 88.700  201.600 121.100  198.000 121.100  198.000 105.700  195.400 105.700  195.400 121.100  193.400 121.100  193.400 88.700  190.800 88.700  190.800 121.100  187.200 121.100  187.200 105.700  184.600 105.700  184.600 121.100  181.500 121.100  181.500 114.900  178.900 114.900  178.900 121.100  171.800 121.100  171.800 88.700  169.200 88.700  169.200 121.100  165.600 121.100  165.600 105.700  163.000 105.700  163.000 121.100  161.000 121.100  161.000 88.700  158.400 88.700  158.400 121.100  154.800 121.100  154.800 105.700  152.200 105.700  152.200 121.100  149.100 121.100  149.100 114.900  146.500 114.900  146.500 121.100  139.400 121.100  139.400 88.700  136.800 88.700  136.800 121.100  133.200 121.100  133.200 105.700  130.600 105.700  130.600 121.100  128.600 121.100  128.600 88.700  126.000 88.700  126.000 121.100  122.400 121.100  122.400 105.700  119.800 105.700  119.800 121.100  116.700 121.100  116.700 114.900  114.100 114.900  114.100 121.100  107.000 121.100  107.000 88.700  104.400 88.700  104.400 121.100  100.800 121.100  100.800 105.700  98.200 105.700  98.200 121.100  96.200 121.100  96.200 88.700  93.600 88.700  93.600 121.100  90.000 121.100  90.000 105.700  87.400 105.700  87.400 121.100  84.300 121.100  84.300 114.900  81.700 114.900  81.700 121.100  74.600 121.100  74.600 88.700  72.000 88.700  72.000 121.100  68.400 121.100  68.400 105.700  65.800 105.700  65.800 121.100  63.800 121.100  63.800 88.700  61.200 88.700  61.200 121.100  57.600 121.100  57.600 105.700  55.000 105.700  55.000 121.100  51.900 121.100  51.900 114.900  49.300 114.900  49.300 121.100  42.200 121.100  42.200 88.700  39.600 88.700  39.600 121.100  36.000 121.100  36.000 105.700  33.400 105.700  33.400 121.100  31.400 121.100  31.400 88.700  28.800 88.700  28.800 121.100  25.200 121.100  25.200 105.700  22.600 105.700  22.600 121.100  20.600 121.100  20.600 88.700 ;
            POLYGON 1210.600 -113.500  1210.600 -61.700  1215.700 -61.700  1215.700 -75.100  1212.400 -75.100  1212.400 -88.600  1214.000 -88.600  1214.000 -92.000  1212.400 -92.000  1212.400 -110.100  1214.300 -110.100  1214.300 -113.500 ;
            POLYGON 1213.100 66.500  1213.100 78.100  1210.600 78.100  1210.600 118.300  1214.300 118.300  1214.300 114.900  1212.400 114.900  1212.400 96.800  1214.000 96.800  1214.000 93.400  1212.400 93.400  1212.400 79.900  1215.700 79.900  1215.700 66.500 ;
            POLYGON 1253.800 28.000  1253.800 36.500  1256.400 36.500  1256.400 31.400  1257.200 31.400  1257.200 28.000 ;
            POLYGON 1286.200 28.000  1286.200 36.500  1288.800 36.500  1288.800 31.400  1289.600 31.400  1289.600 28.000 ;
            POLYGON 1318.600 28.000  1318.600 36.500  1321.200 36.500  1321.200 31.400  1322.000 31.400  1322.000 28.000 ;
            POLYGON 1351.000 28.000  1351.000 36.500  1353.600 36.500  1353.600 31.400  1354.400 31.400  1354.400 28.000 ;
            POLYGON 1383.400 28.000  1383.400 36.500  1386.000 36.500  1386.000 31.400  1386.800 31.400  1386.800 28.000 ;
            POLYGON 1415.800 28.000  1415.800 36.500  1418.400 36.500  1418.400 31.400  1419.200 31.400  1419.200 28.000 ;
            POLYGON 1448.200 28.000  1448.200 36.500  1450.800 36.500  1450.800 31.400  1451.600 31.400  1451.600 28.000 ;
            POLYGON 1480.600 28.000  1480.600 36.500  1483.200 36.500  1483.200 31.400  1484.000 31.400  1484.000 28.000 ;
            POLYGON 1513.000 28.000  1513.000 36.500  1515.600 36.500  1515.600 31.400  1516.400 31.400  1516.400 28.000 ;
            POLYGON 1518.400 28.000  1518.400 31.400  1519.500 31.400  1519.500 36.500  1522.100 36.500  1522.100 33.900  1521.800 33.900  1521.800 28.000 ;
            POLYGON 1599.400 28.000  1599.400 36.500  1602.000 36.500  1602.000 31.400  1602.800 31.400  1602.800 28.000 ;
            POLYGON 1226.500 6.500  1226.500 9.900  1228.400 9.900  1228.400 28.000  1226.800 28.000  1226.800 31.400  1228.400 31.400  1228.400 44.900  1225.100 44.900  1225.100 58.300  1227.700 58.300  1227.700 46.700  1230.200 46.700  1230.200 6.500 ;
            POLYGON 1258.900 6.500  1258.900 9.900  1260.800 9.900  1260.800 28.000  1259.200 28.000  1259.200 31.400  1260.800 31.400  1260.800 44.900  1257.500 44.900  1257.500 58.300  1260.100 58.300  1260.100 46.700  1262.600 46.700  1262.600 6.500 ;
            POLYGON 1291.300 6.500  1291.300 9.900  1293.200 9.900  1293.200 28.000  1291.600 28.000  1291.600 31.400  1293.200 31.400  1293.200 44.900  1289.900 44.900  1289.900 58.300  1292.500 58.300  1292.500 46.700  1295.000 46.700  1295.000 6.500 ;
            POLYGON 1323.700 6.500  1323.700 9.900  1325.600 9.900  1325.600 28.000  1324.000 28.000  1324.000 31.400  1325.600 31.400  1325.600 44.900  1322.300 44.900  1322.300 58.300  1324.900 58.300  1324.900 46.700  1327.400 46.700  1327.400 6.500 ;
            POLYGON 1356.100 6.500  1356.100 9.900  1358.000 9.900  1358.000 28.000  1356.400 28.000  1356.400 31.400  1358.000 31.400  1358.000 44.900  1354.700 44.900  1354.700 58.300  1357.300 58.300  1357.300 46.700  1359.800 46.700  1359.800 6.500 ;
            POLYGON 1388.500 6.500  1388.500 9.900  1390.400 9.900  1390.400 28.000  1388.800 28.000  1388.800 31.400  1390.400 31.400  1390.400 44.900  1387.100 44.900  1387.100 58.300  1389.700 58.300  1389.700 46.700  1392.200 46.700  1392.200 6.500 ;
            POLYGON 1420.900 6.500  1420.900 9.900  1422.800 9.900  1422.800 28.000  1421.200 28.000  1421.200 31.400  1422.800 31.400  1422.800 44.900  1419.500 44.900  1419.500 58.300  1422.100 58.300  1422.100 46.700  1424.600 46.700  1424.600 6.500 ;
            POLYGON 1453.300 6.500  1453.300 9.900  1455.200 9.900  1455.200 28.000  1453.600 28.000  1453.600 31.400  1455.200 31.400  1455.200 44.900  1451.900 44.900  1451.900 58.300  1454.500 58.300  1454.500 46.700  1457.000 46.700  1457.000 6.500 ;
            POLYGON 1485.700 6.500  1485.700 9.900  1487.600 9.900  1487.600 28.000  1486.000 28.000  1486.000 31.400  1487.600 31.400  1487.600 44.900  1484.300 44.900  1484.300 58.300  1486.900 58.300  1486.900 46.700  1489.400 46.700  1489.400 6.500 ;
            POLYGON 1523.500 16.200  1523.500 19.600  1525.400 19.600  1525.400 40.400  1524.600 40.400  1524.600 43.000  1525.400 43.000  1525.400 44.900  1516.700 44.900  1516.700 58.300  1519.300 58.300  1519.300 46.700  1527.200 46.700  1527.200 16.200 ;
            POLYGON 1528.900 7.700  1528.900 11.100  1530.800 11.100  1530.800 28.000  1529.200 28.000  1529.200 31.400  1530.800 31.400  1530.800 48.100  1524.700 48.100  1524.700 58.300  1527.300 58.300  1527.300 50.000  1532.600 50.000  1532.600 7.700 ;
            POLYGON 1604.500 6.500  1604.500 9.900  1606.400 9.900  1606.400 28.000  1604.800 28.000  1604.800 31.400  1606.400 31.400  1606.400 44.900  1603.100 44.900  1603.100 58.300  1605.700 58.300  1605.700 46.700  1608.200 46.700  1608.200 31.400  1616.600 31.400  1616.600 28.000  1608.200 28.000  1608.200 6.500 ;
            POLYGON 1216.800 88.300  1216.800 93.400  1216.000 93.400  1216.000 96.800  1219.400 96.800  1219.400 88.300 ;
            POLYGON 1249.200 88.300  1249.200 93.400  1248.400 93.400  1248.400 96.800  1251.800 96.800  1251.800 88.300 ;
            POLYGON 1281.600 88.300  1281.600 93.400  1280.800 93.400  1280.800 96.800  1284.200 96.800  1284.200 88.300 ;
            POLYGON 1314.000 88.300  1314.000 93.400  1313.200 93.400  1313.200 96.800  1316.600 96.800  1316.600 88.300 ;
            POLYGON 1346.400 88.300  1346.400 93.400  1345.600 93.400  1345.600 96.800  1349.000 96.800  1349.000 88.300 ;
            POLYGON 1378.800 88.300  1378.800 93.400  1378.000 93.400  1378.000 96.800  1381.400 96.800  1381.400 88.300 ;
            POLYGON 1411.200 88.300  1411.200 93.400  1410.400 93.400  1410.400 96.800  1413.800 96.800  1413.800 88.300 ;
            POLYGON 1443.600 88.300  1443.600 93.400  1442.800 93.400  1442.800 96.800  1446.200 96.800  1446.200 88.300 ;
            POLYGON 1476.000 88.300  1476.000 93.400  1475.200 93.400  1475.200 96.800  1478.600 96.800  1478.600 88.300 ;
            POLYGON 1508.400 88.300  1508.400 93.400  1507.600 93.400  1507.600 96.800  1511.000 96.800  1511.000 88.300 ;
            POLYGON 1540.800 88.300  1540.800 93.400  1540.000 93.400  1540.000 96.800  1543.400 96.800  1543.400 88.300 ;
            POLYGON 1573.200 88.300  1573.200 93.400  1572.400 93.400  1572.400 96.800  1575.800 96.800  1575.800 88.300 ;
            POLYGON 1605.600 88.300  1605.600 93.400  1604.800 93.400  1604.800 96.800  1608.200 96.800  1608.200 88.300 ;
            POLYGON 1221.400 28.000  1221.400 36.500  1224.000 36.500  1224.000 31.400  1224.800 31.400  1224.800 28.000 ;
            POLYGON 1245.500 66.500  1245.500 78.100  1243.000 78.100  1243.000 118.300  1246.700 118.300  1246.700 114.900  1244.800 114.900  1244.800 96.800  1246.400 96.800  1246.400 93.400  1244.800 93.400  1244.800 79.900  1248.100 79.900  1248.100 66.500 ;
            POLYGON 1277.900 66.500  1277.900 78.100  1275.400 78.100  1275.400 118.300  1279.100 118.300  1279.100 114.900  1277.200 114.900  1277.200 96.800  1278.800 96.800  1278.800 93.400  1277.200 93.400  1277.200 79.900  1280.500 79.900  1280.500 66.500 ;
            POLYGON 1310.300 66.500  1310.300 78.100  1307.800 78.100  1307.800 118.300  1311.500 118.300  1311.500 114.900  1309.600 114.900  1309.600 96.800  1311.200 96.800  1311.200 93.400  1309.600 93.400  1309.600 79.900  1312.900 79.900  1312.900 66.500 ;
            POLYGON 1342.700 66.500  1342.700 78.100  1340.200 78.100  1340.200 118.300  1343.900 118.300  1343.900 114.900  1342.000 114.900  1342.000 96.800  1343.600 96.800  1343.600 93.400  1342.000 93.400  1342.000 79.900  1345.300 79.900  1345.300 66.500 ;
            POLYGON 1375.100 66.500  1375.100 78.100  1372.600 78.100  1372.600 118.300  1376.300 118.300  1376.300 114.900  1374.400 114.900  1374.400 96.800  1376.000 96.800  1376.000 93.400  1374.400 93.400  1374.400 79.900  1377.700 79.900  1377.700 66.500 ;
            POLYGON 1407.500 66.500  1407.500 78.100  1405.000 78.100  1405.000 118.300  1408.700 118.300  1408.700 114.900  1406.800 114.900  1406.800 96.800  1408.400 96.800  1408.400 93.400  1406.800 93.400  1406.800 79.900  1410.100 79.900  1410.100 66.500 ;
            POLYGON 1439.900 66.500  1439.900 78.100  1437.400 78.100  1437.400 118.300  1441.100 118.300  1441.100 114.900  1439.200 114.900  1439.200 96.800  1440.800 96.800  1440.800 93.400  1439.200 93.400  1439.200 79.900  1442.500 79.900  1442.500 66.500 ;
            POLYGON 1472.300 66.500  1472.300 78.100  1469.800 78.100  1469.800 118.300  1473.500 118.300  1473.500 114.900  1471.600 114.900  1471.600 96.800  1473.200 96.800  1473.200 93.400  1471.600 93.400  1471.600 79.900  1474.900 79.900  1474.900 66.500 ;
            POLYGON 1504.700 66.500  1504.700 78.100  1502.200 78.100  1502.200 118.300  1505.900 118.300  1505.900 114.900  1504.000 114.900  1504.000 96.800  1505.600 96.800  1505.600 93.400  1504.000 93.400  1504.000 79.900  1507.300 79.900  1507.300 66.500 ;
            POLYGON 1537.100 66.500  1537.100 78.100  1534.600 78.100  1534.600 118.300  1538.300 118.300  1538.300 114.900  1536.400 114.900  1536.400 96.800  1538.000 96.800  1538.000 93.400  1536.400 93.400  1536.400 79.900  1539.700 79.900  1539.700 66.500 ;
            POLYGON 1569.500 66.500  1569.500 78.100  1567.000 78.100  1567.000 118.300  1570.700 118.300  1570.700 114.900  1568.800 114.900  1568.800 96.800  1570.400 96.800  1570.400 93.400  1568.800 93.400  1568.800 79.900  1572.100 79.900  1572.100 66.500 ;
            POLYGON 1601.900 66.500  1601.900 78.100  1599.400 78.100  1599.400 118.300  1603.100 118.300  1603.100 114.900  1601.200 114.900  1601.200 96.800  1602.800 96.800  1602.800 93.400  1601.200 93.400  1601.200 79.900  1604.500 79.900  1604.500 66.500 ;
            POLYGON 892.800 88.300  892.800 93.400  892.000 93.400  892.000 96.800  895.400 96.800  895.400 88.300 ;
            POLYGON 925.200 88.300  925.200 93.400  924.400 93.400  924.400 96.800  927.800 96.800  927.800 88.300 ;
            POLYGON 957.600 88.300  957.600 93.400  956.800 93.400  956.800 96.800  960.200 96.800  960.200 88.300 ;
            POLYGON 990.000 88.300  990.000 93.400  989.200 93.400  989.200 96.800  992.600 96.800  992.600 88.300 ;
            POLYGON 1022.400 88.300  1022.400 93.400  1021.600 93.400  1021.600 96.800  1025.000 96.800  1025.000 88.300 ;
            POLYGON 1054.800 88.300  1054.800 93.400  1054.000 93.400  1054.000 96.800  1057.400 96.800  1057.400 88.300 ;
            POLYGON 1087.200 88.300  1087.200 93.400  1086.400 93.400  1086.400 96.800  1089.800 96.800  1089.800 88.300 ;
            POLYGON 1119.600 88.300  1119.600 93.400  1118.800 93.400  1118.800 96.800  1122.200 96.800  1122.200 88.300 ;
            POLYGON 1152.000 88.300  1152.000 93.400  1151.200 93.400  1151.200 96.800  1154.600 96.800  1154.600 88.300 ;
            POLYGON 1184.400 88.300  1184.400 93.400  1183.600 93.400  1183.600 96.800  1187.000 96.800  1187.000 88.300 ;
            POLYGON 837.700 6.500  837.700 9.900  839.600 9.900  839.600 28.000  838.000 28.000  838.000 31.400  839.600 31.400  839.600 44.900  836.300 44.900  836.300 58.300  838.900 58.300  838.900 46.700  841.400 46.700  841.400 6.500 ;
            POLYGON 870.100 6.500  870.100 9.900  872.000 9.900  872.000 28.000  870.400 28.000  870.400 31.400  872.000 31.400  872.000 44.900  868.700 44.900  868.700 58.300  871.300 58.300  871.300 46.700  873.800 46.700  873.800 6.500 ;
            POLYGON 902.500 6.500  902.500 9.900  904.400 9.900  904.400 28.000  902.800 28.000  902.800 31.400  904.400 31.400  904.400 44.900  901.100 44.900  901.100 58.300  903.700 58.300  903.700 46.700  906.200 46.700  906.200 6.500 ;
            POLYGON 934.900 6.500  934.900 9.900  936.800 9.900  936.800 28.000  935.200 28.000  935.200 31.400  936.800 31.400  936.800 44.900  933.500 44.900  933.500 58.300  936.100 58.300  936.100 46.700  938.600 46.700  938.600 6.500 ;
            POLYGON 967.300 6.500  967.300 9.900  969.200 9.900  969.200 28.000  967.600 28.000  967.600 31.400  969.200 31.400  969.200 44.900  965.900 44.900  965.900 58.300  968.500 58.300  968.500 46.700  971.000 46.700  971.000 6.500 ;
            POLYGON 999.700 6.500  999.700 9.900  1001.600 9.900  1001.600 28.000  1000.000 28.000  1000.000 31.400  1001.600 31.400  1001.600 44.900  998.300 44.900  998.300 58.300  1000.900 58.300  1000.900 46.700  1003.400 46.700  1003.400 6.500 ;
            POLYGON 1032.100 6.500  1032.100 9.900  1034.000 9.900  1034.000 28.000  1032.400 28.000  1032.400 31.400  1034.000 31.400  1034.000 44.900  1030.700 44.900  1030.700 58.300  1033.300 58.300  1033.300 46.700  1035.800 46.700  1035.800 6.500 ;
            POLYGON 1064.500 6.500  1064.500 9.900  1066.400 9.900  1066.400 28.000  1064.800 28.000  1064.800 31.400  1066.400 31.400  1066.400 44.900  1063.100 44.900  1063.100 58.300  1065.700 58.300  1065.700 46.700  1068.200 46.700  1068.200 6.500 ;
            POLYGON 1096.900 6.500  1096.900 9.900  1098.800 9.900  1098.800 28.000  1097.200 28.000  1097.200 31.400  1098.800 31.400  1098.800 44.900  1095.500 44.900  1095.500 58.300  1098.100 58.300  1098.100 46.700  1100.600 46.700  1100.600 6.500 ;
            POLYGON 1129.300 6.500  1129.300 9.900  1131.200 9.900  1131.200 28.000  1129.600 28.000  1129.600 31.400  1131.200 31.400  1131.200 44.900  1127.900 44.900  1127.900 58.300  1130.500 58.300  1130.500 46.700  1133.000 46.700  1133.000 6.500 ;
            POLYGON 1161.700 6.500  1161.700 9.900  1163.600 9.900  1163.600 28.000  1162.000 28.000  1162.000 31.400  1163.600 31.400  1163.600 44.900  1160.300 44.900  1160.300 58.300  1162.900 58.300  1162.900 46.700  1165.400 46.700  1165.400 6.500 ;
            POLYGON 1194.100 6.500  1194.100 9.900  1196.000 9.900  1196.000 28.000  1194.400 28.000  1194.400 31.400  1196.000 31.400  1196.000 44.900  1192.700 44.900  1192.700 58.300  1195.300 58.300  1195.300 46.700  1197.800 46.700  1197.800 6.500 ;
            POLYGON 832.600 28.000  832.600 36.500  835.200 36.500  835.200 31.400  836.000 31.400  836.000 28.000 ;
            POLYGON 824.300 66.500  824.300 78.100  821.800 78.100  821.800 118.300  825.500 118.300  825.500 114.900  823.600 114.900  823.600 96.800  825.200 96.800  825.200 93.400  823.600 93.400  823.600 79.900  826.900 79.900  826.900 66.500 ;
            POLYGON 856.700 66.500  856.700 78.100  854.200 78.100  854.200 118.300  857.900 118.300  857.900 114.900  856.000 114.900  856.000 96.800  857.600 96.800  857.600 93.400  856.000 93.400  856.000 79.900  859.300 79.900  859.300 66.500 ;
            POLYGON 889.100 66.500  889.100 78.100  886.600 78.100  886.600 118.300  890.300 118.300  890.300 114.900  888.400 114.900  888.400 96.800  890.000 96.800  890.000 93.400  888.400 93.400  888.400 79.900  891.700 79.900  891.700 66.500 ;
            POLYGON 921.500 66.500  921.500 78.100  919.000 78.100  919.000 118.300  922.700 118.300  922.700 114.900  920.800 114.900  920.800 96.800  922.400 96.800  922.400 93.400  920.800 93.400  920.800 79.900  924.100 79.900  924.100 66.500 ;
            POLYGON 953.900 66.500  953.900 78.100  951.400 78.100  951.400 118.300  955.100 118.300  955.100 114.900  953.200 114.900  953.200 96.800  954.800 96.800  954.800 93.400  953.200 93.400  953.200 79.900  956.500 79.900  956.500 66.500 ;
            POLYGON 986.300 66.500  986.300 78.100  983.800 78.100  983.800 118.300  987.500 118.300  987.500 114.900  985.600 114.900  985.600 96.800  987.200 96.800  987.200 93.400  985.600 93.400  985.600 79.900  988.900 79.900  988.900 66.500 ;
            POLYGON 1018.700 66.500  1018.700 78.100  1016.200 78.100  1016.200 118.300  1019.900 118.300  1019.900 114.900  1018.000 114.900  1018.000 96.800  1019.600 96.800  1019.600 93.400  1018.000 93.400  1018.000 79.900  1021.300 79.900  1021.300 66.500 ;
            POLYGON 1051.100 66.500  1051.100 78.100  1048.600 78.100  1048.600 118.300  1052.300 118.300  1052.300 114.900  1050.400 114.900  1050.400 96.800  1052.000 96.800  1052.000 93.400  1050.400 93.400  1050.400 79.900  1053.700 79.900  1053.700 66.500 ;
            POLYGON 1083.500 66.500  1083.500 78.100  1081.000 78.100  1081.000 118.300  1084.700 118.300  1084.700 114.900  1082.800 114.900  1082.800 96.800  1084.400 96.800  1084.400 93.400  1082.800 93.400  1082.800 79.900  1086.100 79.900  1086.100 66.500 ;
            POLYGON 1115.900 66.500  1115.900 78.100  1113.400 78.100  1113.400 118.300  1117.100 118.300  1117.100 114.900  1115.200 114.900  1115.200 96.800  1116.800 96.800  1116.800 93.400  1115.200 93.400  1115.200 79.900  1118.500 79.900  1118.500 66.500 ;
            POLYGON 1148.300 66.500  1148.300 78.100  1145.800 78.100  1145.800 118.300  1149.500 118.300  1149.500 114.900  1147.600 114.900  1147.600 96.800  1149.200 96.800  1149.200 93.400  1147.600 93.400  1147.600 79.900  1150.900 79.900  1150.900 66.500 ;
            POLYGON 1180.700 66.500  1180.700 78.100  1178.200 78.100  1178.200 118.300  1181.900 118.300  1181.900 114.900  1180.000 114.900  1180.000 96.800  1181.600 96.800  1181.600 93.400  1180.000 93.400  1180.000 79.900  1183.300 79.900  1183.300 66.500 ;
            POLYGON 865.000 28.000  865.000 36.500  867.600 36.500  867.600 31.400  868.400 31.400  868.400 28.000 ;
            POLYGON 897.400 28.000  897.400 36.500  900.000 36.500  900.000 31.400  900.800 31.400  900.800 28.000 ;
            POLYGON 929.800 28.000  929.800 36.500  932.400 36.500  932.400 31.400  933.200 31.400  933.200 28.000 ;
            POLYGON 962.200 28.000  962.200 36.500  964.800 36.500  964.800 31.400  965.600 31.400  965.600 28.000 ;
            POLYGON 994.600 28.000  994.600 36.500  997.200 36.500  997.200 31.400  998.000 31.400  998.000 28.000 ;
            POLYGON 1027.000 28.000  1027.000 36.500  1029.600 36.500  1029.600 31.400  1030.400 31.400  1030.400 28.000 ;
            POLYGON 1059.400 28.000  1059.400 36.500  1062.000 36.500  1062.000 31.400  1062.800 31.400  1062.800 28.000 ;
            POLYGON 1091.800 28.000  1091.800 36.500  1094.400 36.500  1094.400 31.400  1095.200 31.400  1095.200 28.000 ;
            POLYGON 1124.200 28.000  1124.200 36.500  1126.800 36.500  1126.800 31.400  1127.600 31.400  1127.600 28.000 ;
            POLYGON 1156.600 28.000  1156.600 36.500  1159.200 36.500  1159.200 31.400  1160.000 31.400  1160.000 28.000 ;
            POLYGON 1189.000 28.000  1189.000 36.500  1191.600 36.500  1191.600 31.400  1192.400 31.400  1192.400 28.000 ;
            POLYGON 828.000 88.300  828.000 93.400  827.200 93.400  827.200 96.800  830.600 96.800  830.600 88.300 ;
            POLYGON 860.400 88.300  860.400 93.400  859.600 93.400  859.600 96.800  863.000 96.800  863.000 88.300 ;
            POLYGON 1183.600 -92.000  1183.600 -88.600  1184.400 -88.600  1184.400 -83.500  1187.000 -83.500  1187.000 -92.000 ;
            POLYGON 821.800 -113.500  821.800 -61.700  826.900 -61.700  826.900 -75.100  823.600 -75.100  823.600 -88.600  825.200 -88.600  825.200 -92.000  823.600 -92.000  823.600 -110.100  825.500 -110.100  825.500 -113.500 ;
            POLYGON 854.200 -113.500  854.200 -61.700  859.300 -61.700  859.300 -75.100  856.000 -75.100  856.000 -88.600  857.600 -88.600  857.600 -92.000  856.000 -92.000  856.000 -110.100  857.900 -110.100  857.900 -113.500 ;
            POLYGON 886.600 -113.500  886.600 -61.700  891.700 -61.700  891.700 -75.100  888.400 -75.100  888.400 -88.600  890.000 -88.600  890.000 -92.000  888.400 -92.000  888.400 -110.100  890.300 -110.100  890.300 -113.500 ;
            POLYGON 919.000 -113.500  919.000 -61.700  924.100 -61.700  924.100 -75.100  920.800 -75.100  920.800 -88.600  922.400 -88.600  922.400 -92.000  920.800 -92.000  920.800 -110.100  922.700 -110.100  922.700 -113.500 ;
            POLYGON 951.400 -113.500  951.400 -61.700  956.500 -61.700  956.500 -75.100  953.200 -75.100  953.200 -88.600  954.800 -88.600  954.800 -92.000  953.200 -92.000  953.200 -110.100  955.100 -110.100  955.100 -113.500 ;
            POLYGON 983.800 -113.500  983.800 -61.700  988.900 -61.700  988.900 -75.100  985.600 -75.100  985.600 -88.600  987.200 -88.600  987.200 -92.000  985.600 -92.000  985.600 -110.100  987.500 -110.100  987.500 -113.500 ;
            POLYGON 1016.200 -113.500  1016.200 -61.700  1021.300 -61.700  1021.300 -75.100  1018.000 -75.100  1018.000 -88.600  1019.600 -88.600  1019.600 -92.000  1018.000 -92.000  1018.000 -110.100  1019.900 -110.100  1019.900 -113.500 ;
            POLYGON 1048.600 -113.500  1048.600 -61.700  1053.700 -61.700  1053.700 -75.100  1050.400 -75.100  1050.400 -88.600  1052.000 -88.600  1052.000 -92.000  1050.400 -92.000  1050.400 -110.100  1052.300 -110.100  1052.300 -113.500 ;
            POLYGON 1081.000 -113.500  1081.000 -61.700  1086.100 -61.700  1086.100 -75.100  1082.800 -75.100  1082.800 -88.600  1084.400 -88.600  1084.400 -92.000  1082.800 -92.000  1082.800 -110.100  1084.700 -110.100  1084.700 -113.500 ;
            POLYGON 1113.400 -113.500  1113.400 -61.700  1118.500 -61.700  1118.500 -75.100  1115.200 -75.100  1115.200 -88.600  1116.800 -88.600  1116.800 -92.000  1115.200 -92.000  1115.200 -110.100  1117.100 -110.100  1117.100 -113.500 ;
            POLYGON 1145.800 -113.500  1145.800 -61.700  1150.900 -61.700  1150.900 -75.100  1147.600 -75.100  1147.600 -88.600  1149.200 -88.600  1149.200 -92.000  1147.600 -92.000  1147.600 -110.100  1149.500 -110.100  1149.500 -113.500 ;
            POLYGON 1178.200 -113.500  1178.200 -61.700  1183.300 -61.700  1183.300 -75.100  1180.000 -75.100  1180.000 -88.600  1181.600 -88.600  1181.600 -92.000  1180.000 -92.000  1180.000 -110.100  1181.900 -110.100  1181.900 -113.500 ;
            POLYGON 956.800 -92.000  956.800 -88.600  957.600 -88.600  957.600 -83.500  960.200 -83.500  960.200 -92.000 ;
            POLYGON 832.600 -31.700  832.600 -23.200  836.000 -23.200  836.000 -26.600  835.200 -26.600  835.200 -31.700 ;
            POLYGON 865.000 -31.700  865.000 -23.200  868.400 -23.200  868.400 -26.600  867.600 -26.600  867.600 -31.700 ;
            POLYGON 897.400 -31.700  897.400 -23.200  900.800 -23.200  900.800 -26.600  900.000 -26.600  900.000 -31.700 ;
            POLYGON 929.800 -31.700  929.800 -23.200  933.200 -23.200  933.200 -26.600  932.400 -26.600  932.400 -31.700 ;
            POLYGON 962.200 -31.700  962.200 -23.200  965.600 -23.200  965.600 -26.600  964.800 -26.600  964.800 -31.700 ;
            POLYGON 994.600 -31.700  994.600 -23.200  998.000 -23.200  998.000 -26.600  997.200 -26.600  997.200 -31.700 ;
            POLYGON 1027.000 -31.700  1027.000 -23.200  1030.400 -23.200  1030.400 -26.600  1029.600 -26.600  1029.600 -31.700 ;
            POLYGON 892.000 -92.000  892.000 -88.600  892.800 -88.600  892.800 -83.500  895.400 -83.500  895.400 -92.000 ;
            POLYGON 1059.400 -31.700  1059.400 -23.200  1062.800 -23.200  1062.800 -26.600  1062.000 -26.600  1062.000 -31.700 ;
            POLYGON 1091.800 -31.700  1091.800 -23.200  1095.200 -23.200  1095.200 -26.600  1094.400 -26.600  1094.400 -31.700 ;
            POLYGON 1124.200 -31.700  1124.200 -23.200  1127.600 -23.200  1127.600 -26.600  1126.800 -26.600  1126.800 -31.700 ;
            POLYGON 1156.600 -31.700  1156.600 -23.200  1160.000 -23.200  1160.000 -26.600  1159.200 -26.600  1159.200 -31.700 ;
            POLYGON 1189.000 -31.700  1189.000 -23.200  1192.400 -23.200  1192.400 -26.600  1191.600 -26.600  1191.600 -31.700 ;
            POLYGON 827.200 -92.000  827.200 -88.600  828.000 -88.600  828.000 -83.500  830.600 -83.500  830.600 -92.000 ;
            POLYGON 836.300 -53.500  836.300 -40.100  839.600 -40.100  839.600 -26.600  838.000 -26.600  838.000 -23.200  839.600 -23.200  839.600 -5.100  837.700 -5.100  837.700 -1.700  841.400 -1.700  841.400 -53.500 ;
            POLYGON 868.700 -53.500  868.700 -40.100  872.000 -40.100  872.000 -26.600  870.400 -26.600  870.400 -23.200  872.000 -23.200  872.000 -5.100  870.100 -5.100  870.100 -1.700  873.800 -1.700  873.800 -53.500 ;
            POLYGON 901.100 -53.500  901.100 -40.100  904.400 -40.100  904.400 -26.600  902.800 -26.600  902.800 -23.200  904.400 -23.200  904.400 -5.100  902.500 -5.100  902.500 -1.700  906.200 -1.700  906.200 -53.500 ;
            POLYGON 933.500 -53.500  933.500 -40.100  936.800 -40.100  936.800 -26.600  935.200 -26.600  935.200 -23.200  936.800 -23.200  936.800 -5.100  934.900 -5.100  934.900 -1.700  938.600 -1.700  938.600 -53.500 ;
            POLYGON 965.900 -53.500  965.900 -40.100  969.200 -40.100  969.200 -26.600  967.600 -26.600  967.600 -23.200  969.200 -23.200  969.200 -5.100  967.300 -5.100  967.300 -1.700  971.000 -1.700  971.000 -53.500 ;
            POLYGON 998.300 -53.500  998.300 -40.100  1001.600 -40.100  1001.600 -26.600  1000.000 -26.600  1000.000 -23.200  1001.600 -23.200  1001.600 -5.100  999.700 -5.100  999.700 -1.700  1003.400 -1.700  1003.400 -53.500 ;
            POLYGON 1030.700 -53.500  1030.700 -40.100  1034.000 -40.100  1034.000 -26.600  1032.400 -26.600  1032.400 -23.200  1034.000 -23.200  1034.000 -5.100  1032.100 -5.100  1032.100 -1.700  1035.800 -1.700  1035.800 -53.500 ;
            POLYGON 1063.100 -53.500  1063.100 -40.100  1066.400 -40.100  1066.400 -26.600  1064.800 -26.600  1064.800 -23.200  1066.400 -23.200  1066.400 -5.100  1064.500 -5.100  1064.500 -1.700  1068.200 -1.700  1068.200 -53.500 ;
            POLYGON 1095.500 -53.500  1095.500 -40.100  1098.800 -40.100  1098.800 -26.600  1097.200 -26.600  1097.200 -23.200  1098.800 -23.200  1098.800 -5.100  1096.900 -5.100  1096.900 -1.700  1100.600 -1.700  1100.600 -53.500 ;
            POLYGON 1127.900 -53.500  1127.900 -40.100  1131.200 -40.100  1131.200 -26.600  1129.600 -26.600  1129.600 -23.200  1131.200 -23.200  1131.200 -5.100  1129.300 -5.100  1129.300 -1.700  1133.000 -1.700  1133.000 -53.500 ;
            POLYGON 1160.300 -53.500  1160.300 -40.100  1163.600 -40.100  1163.600 -26.600  1162.000 -26.600  1162.000 -23.200  1163.600 -23.200  1163.600 -5.100  1161.700 -5.100  1161.700 -1.700  1165.400 -1.700  1165.400 -53.500 ;
            POLYGON 1192.700 -53.500  1192.700 -40.100  1196.000 -40.100  1196.000 -26.600  1194.400 -26.600  1194.400 -23.200  1196.000 -23.200  1196.000 -5.100  1194.100 -5.100  1194.100 -1.700  1197.800 -1.700  1197.800 -53.500 ;
            POLYGON 859.600 -92.000  859.600 -88.600  860.400 -88.600  860.400 -83.500  863.000 -83.500  863.000 -92.000 ;
            POLYGON 989.200 -92.000  989.200 -88.600  990.000 -88.600  990.000 -83.500  992.600 -83.500  992.600 -92.000 ;
            POLYGON 1021.600 -92.000  1021.600 -88.600  1022.400 -88.600  1022.400 -83.500  1025.000 -83.500  1025.000 -92.000 ;
            POLYGON 1054.000 -92.000  1054.000 -88.600  1054.800 -88.600  1054.800 -83.500  1057.400 -83.500  1057.400 -92.000 ;
            POLYGON 1086.400 -92.000  1086.400 -88.600  1087.200 -88.600  1087.200 -83.500  1089.800 -83.500  1089.800 -92.000 ;
            POLYGON 1118.800 -92.000  1118.800 -88.600  1119.600 -88.600  1119.600 -83.500  1122.200 -83.500  1122.200 -92.000 ;
            POLYGON 1151.200 -92.000  1151.200 -88.600  1152.000 -88.600  1152.000 -83.500  1154.600 -83.500  1154.600 -92.000 ;
            POLYGON 924.400 -92.000  924.400 -88.600  925.200 -88.600  925.200 -83.500  927.800 -83.500  927.800 -92.000 ;
            POLYGON 1313.200 -92.000  1313.200 -88.600  1314.000 -88.600  1314.000 -83.500  1316.600 -83.500  1316.600 -92.000 ;
            POLYGON 1345.600 -92.000  1345.600 -88.600  1346.400 -88.600  1346.400 -83.500  1349.000 -83.500  1349.000 -92.000 ;
            POLYGON 1378.000 -92.000  1378.000 -88.600  1378.800 -88.600  1378.800 -83.500  1381.400 -83.500  1381.400 -92.000 ;
            POLYGON 1410.400 -92.000  1410.400 -88.600  1411.200 -88.600  1411.200 -83.500  1413.800 -83.500  1413.800 -92.000 ;
            POLYGON 1442.800 -92.000  1442.800 -88.600  1443.600 -88.600  1443.600 -83.500  1446.200 -83.500  1446.200 -92.000 ;
            POLYGON 1475.200 -92.000  1475.200 -88.600  1476.000 -88.600  1476.000 -83.500  1478.600 -83.500  1478.600 -92.000 ;
            POLYGON 1507.600 -92.000  1507.600 -88.600  1508.400 -88.600  1508.400 -83.500  1511.000 -83.500  1511.000 -92.000 ;
            POLYGON 1540.000 -92.000  1540.000 -88.600  1540.800 -88.600  1540.800 -83.500  1543.400 -83.500  1543.400 -92.000 ;
            POLYGON 1572.400 -92.000  1572.400 -88.600  1573.200 -88.600  1573.200 -83.500  1575.800 -83.500  1575.800 -92.000 ;
            POLYGON 1221.400 -31.700  1221.400 -23.200  1224.800 -23.200  1224.800 -26.600  1224.000 -26.600  1224.000 -31.700 ;
            POLYGON 1253.800 -31.700  1253.800 -23.200  1257.200 -23.200  1257.200 -26.600  1256.400 -26.600  1256.400 -31.700 ;
            POLYGON 1286.200 -31.700  1286.200 -23.200  1289.600 -23.200  1289.600 -26.600  1288.800 -26.600  1288.800 -31.700 ;
            POLYGON 1318.600 -31.700  1318.600 -23.200  1322.000 -23.200  1322.000 -26.600  1321.200 -26.600  1321.200 -31.700 ;
            POLYGON 1351.000 -31.700  1351.000 -23.200  1354.400 -23.200  1354.400 -26.600  1353.600 -26.600  1353.600 -31.700 ;
            POLYGON 1383.400 -31.700  1383.400 -23.200  1386.800 -23.200  1386.800 -26.600  1386.000 -26.600  1386.000 -31.700 ;
            POLYGON 1415.800 -31.700  1415.800 -23.200  1419.200 -23.200  1419.200 -26.600  1418.400 -26.600  1418.400 -31.700 ;
            POLYGON 1448.200 -31.700  1448.200 -23.200  1451.600 -23.200  1451.600 -26.600  1450.800 -26.600  1450.800 -31.700 ;
            POLYGON 1480.600 -31.700  1480.600 -23.200  1484.000 -23.200  1484.000 -26.600  1483.200 -26.600  1483.200 -31.700 ;
            POLYGON 1513.000 -31.700  1513.000 -23.200  1516.400 -23.200  1516.400 -26.600  1515.600 -26.600  1515.600 -31.700 ;
            POLYGON 1519.500 -31.700  1519.500 -26.600  1518.400 -26.600  1518.400 -23.200  1521.800 -23.200  1521.800 -29.100  1522.100 -29.100  1522.100 -31.700 ;
            POLYGON 1599.400 -31.700  1599.400 -23.200  1602.800 -23.200  1602.800 -26.600  1602.000 -26.600  1602.000 -31.700 ;
            POLYGON 1604.800 -92.000  1604.800 -88.600  1605.600 -88.600  1605.600 -83.500  1608.200 -83.500  1608.200 -92.000 ;
            POLYGON 1516.700 -53.500  1516.700 -40.100  1525.400 -40.100  1525.400 -38.200  1524.600 -38.200  1524.600 -35.600  1525.400 -35.600  1525.400 -14.800  1523.500 -14.800  1523.500 -11.400  1527.200 -11.400  1527.200 -41.900  1519.300 -41.900  1519.300 -53.500 ;
            POLYGON 1524.700 -53.500  1524.700 -43.300  1530.800 -43.300  1530.800 -26.600  1529.200 -26.600  1529.200 -23.200  1530.800 -23.200  1530.800 -6.300  1528.900 -6.300  1528.900 -2.900  1532.600 -2.900  1532.600 -45.200  1527.300 -45.200  1527.300 -53.500 ;
            POLYGON 1243.000 -113.500  1243.000 -61.700  1248.100 -61.700  1248.100 -75.100  1244.800 -75.100  1244.800 -88.600  1246.400 -88.600  1246.400 -92.000  1244.800 -92.000  1244.800 -110.100  1246.700 -110.100  1246.700 -113.500 ;
            POLYGON 1275.400 -113.500  1275.400 -61.700  1280.500 -61.700  1280.500 -75.100  1277.200 -75.100  1277.200 -88.600  1278.800 -88.600  1278.800 -92.000  1277.200 -92.000  1277.200 -110.100  1279.100 -110.100  1279.100 -113.500 ;
            POLYGON 1307.800 -113.500  1307.800 -61.700  1312.900 -61.700  1312.900 -75.100  1309.600 -75.100  1309.600 -88.600  1311.200 -88.600  1311.200 -92.000  1309.600 -92.000  1309.600 -110.100  1311.500 -110.100  1311.500 -113.500 ;
            POLYGON 1340.200 -113.500  1340.200 -61.700  1345.300 -61.700  1345.300 -75.100  1342.000 -75.100  1342.000 -88.600  1343.600 -88.600  1343.600 -92.000  1342.000 -92.000  1342.000 -110.100  1343.900 -110.100  1343.900 -113.500 ;
            POLYGON 1372.600 -113.500  1372.600 -61.700  1377.700 -61.700  1377.700 -75.100  1374.400 -75.100  1374.400 -88.600  1376.000 -88.600  1376.000 -92.000  1374.400 -92.000  1374.400 -110.100  1376.300 -110.100  1376.300 -113.500 ;
            POLYGON 1405.000 -113.500  1405.000 -61.700  1410.100 -61.700  1410.100 -75.100  1406.800 -75.100  1406.800 -88.600  1408.400 -88.600  1408.400 -92.000  1406.800 -92.000  1406.800 -110.100  1408.700 -110.100  1408.700 -113.500 ;
            POLYGON 1437.400 -113.500  1437.400 -61.700  1442.500 -61.700  1442.500 -75.100  1439.200 -75.100  1439.200 -88.600  1440.800 -88.600  1440.800 -92.000  1439.200 -92.000  1439.200 -110.100  1441.100 -110.100  1441.100 -113.500 ;
            POLYGON 1469.800 -113.500  1469.800 -61.700  1474.900 -61.700  1474.900 -75.100  1471.600 -75.100  1471.600 -88.600  1473.200 -88.600  1473.200 -92.000  1471.600 -92.000  1471.600 -110.100  1473.500 -110.100  1473.500 -113.500 ;
            POLYGON 1502.200 -113.500  1502.200 -61.700  1507.300 -61.700  1507.300 -75.100  1504.000 -75.100  1504.000 -88.600  1505.600 -88.600  1505.600 -92.000  1504.000 -92.000  1504.000 -110.100  1505.900 -110.100  1505.900 -113.500 ;
            POLYGON 1534.600 -113.500  1534.600 -61.700  1539.700 -61.700  1539.700 -75.100  1536.400 -75.100  1536.400 -88.600  1538.000 -88.600  1538.000 -92.000  1536.400 -92.000  1536.400 -110.100  1538.300 -110.100  1538.300 -113.500 ;
            POLYGON 1567.000 -113.500  1567.000 -61.700  1572.100 -61.700  1572.100 -75.100  1568.800 -75.100  1568.800 -88.600  1570.400 -88.600  1570.400 -92.000  1568.800 -92.000  1568.800 -110.100  1570.700 -110.100  1570.700 -113.500 ;
            POLYGON 1599.400 -113.500  1599.400 -61.700  1604.500 -61.700  1604.500 -75.100  1601.200 -75.100  1601.200 -88.600  1602.800 -88.600  1602.800 -92.000  1601.200 -92.000  1601.200 -110.100  1603.100 -110.100  1603.100 -113.500 ;
            POLYGON 1225.100 -53.500  1225.100 -40.100  1228.400 -40.100  1228.400 -26.600  1226.800 -26.600  1226.800 -23.200  1228.400 -23.200  1228.400 -5.100  1226.500 -5.100  1226.500 -1.700  1230.200 -1.700  1230.200 -53.500 ;
            POLYGON 1257.500 -53.500  1257.500 -40.100  1260.800 -40.100  1260.800 -26.600  1259.200 -26.600  1259.200 -23.200  1260.800 -23.200  1260.800 -5.100  1258.900 -5.100  1258.900 -1.700  1262.600 -1.700  1262.600 -53.500 ;
            POLYGON 1289.900 -53.500  1289.900 -40.100  1293.200 -40.100  1293.200 -26.600  1291.600 -26.600  1291.600 -23.200  1293.200 -23.200  1293.200 -5.100  1291.300 -5.100  1291.300 -1.700  1295.000 -1.700  1295.000 -53.500 ;
            POLYGON 1322.300 -53.500  1322.300 -40.100  1325.600 -40.100  1325.600 -26.600  1324.000 -26.600  1324.000 -23.200  1325.600 -23.200  1325.600 -5.100  1323.700 -5.100  1323.700 -1.700  1327.400 -1.700  1327.400 -53.500 ;
            POLYGON 1354.700 -53.500  1354.700 -40.100  1358.000 -40.100  1358.000 -26.600  1356.400 -26.600  1356.400 -23.200  1358.000 -23.200  1358.000 -5.100  1356.100 -5.100  1356.100 -1.700  1359.800 -1.700  1359.800 -53.500 ;
            POLYGON 1387.100 -53.500  1387.100 -40.100  1390.400 -40.100  1390.400 -26.600  1388.800 -26.600  1388.800 -23.200  1390.400 -23.200  1390.400 -5.100  1388.500 -5.100  1388.500 -1.700  1392.200 -1.700  1392.200 -53.500 ;
            POLYGON 1419.500 -53.500  1419.500 -40.100  1422.800 -40.100  1422.800 -26.600  1421.200 -26.600  1421.200 -23.200  1422.800 -23.200  1422.800 -5.100  1420.900 -5.100  1420.900 -1.700  1424.600 -1.700  1424.600 -53.500 ;
            POLYGON 1451.900 -53.500  1451.900 -40.100  1455.200 -40.100  1455.200 -26.600  1453.600 -26.600  1453.600 -23.200  1455.200 -23.200  1455.200 -5.100  1453.300 -5.100  1453.300 -1.700  1457.000 -1.700  1457.000 -53.500 ;
            POLYGON 1484.300 -53.500  1484.300 -40.100  1487.600 -40.100  1487.600 -26.600  1486.000 -26.600  1486.000 -23.200  1487.600 -23.200  1487.600 -5.100  1485.700 -5.100  1485.700 -1.700  1489.400 -1.700  1489.400 -53.500 ;
            POLYGON 1603.100 -53.500  1603.100 -40.100  1606.400 -40.100  1606.400 -26.600  1604.800 -26.600  1604.800 -23.200  1606.400 -23.200  1606.400 -5.100  1604.500 -5.100  1604.500 -1.700  1608.200 -1.700  1608.200 -23.200  1616.600 -23.200  1616.600 -26.600  1608.200 -26.600  1608.200 -41.900  1605.700 -41.900  1605.700 -53.500 ;
            POLYGON 1216.000 -92.000  1216.000 -88.600  1216.800 -88.600  1216.800 -83.500  1219.400 -83.500  1219.400 -92.000 ;
            POLYGON 1248.400 -92.000  1248.400 -88.600  1249.200 -88.600  1249.200 -83.500  1251.800 -83.500  1251.800 -92.000 ;
            POLYGON 1280.800 -92.000  1280.800 -88.600  1281.600 -88.600  1281.600 -83.500  1284.200 -83.500  1284.200 -92.000 ;
            POLYGON 400.600 -113.500  400.600 -61.700  405.700 -61.700  405.700 -75.100  402.400 -75.100  402.400 -88.600  404.000 -88.600  404.000 -92.000  402.400 -92.000  402.400 -110.100  404.300 -110.100  404.300 -113.500 ;
            POLYGON 403.100 66.500  403.100 78.100  400.600 78.100  400.600 118.300  404.300 118.300  404.300 114.900  402.400 114.900  402.400 96.800  404.000 96.800  404.000 93.400  402.400 93.400  402.400 79.900  405.700 79.900  405.700 66.500 ;
            POLYGON 476.200 28.000  476.200 36.500  478.800 36.500  478.800 31.400  479.600 31.400  479.600 28.000 ;
            POLYGON 508.600 28.000  508.600 36.500  511.200 36.500  511.200 31.400  512.000 31.400  512.000 28.000 ;
            POLYGON 541.000 28.000  541.000 36.500  543.600 36.500  543.600 31.400  544.400 31.400  544.400 28.000 ;
            POLYGON 573.400 28.000  573.400 36.500  576.000 36.500  576.000 31.400  576.800 31.400  576.800 28.000 ;
            POLYGON 605.800 28.000  605.800 36.500  608.400 36.500  608.400 31.400  609.200 31.400  609.200 28.000 ;
            POLYGON 638.200 28.000  638.200 36.500  640.800 36.500  640.800 31.400  641.600 31.400  641.600 28.000 ;
            POLYGON 670.600 28.000  670.600 36.500  673.200 36.500  673.200 31.400  674.000 31.400  674.000 28.000 ;
            POLYGON 703.000 28.000  703.000 36.500  705.600 36.500  705.600 31.400  706.400 31.400  706.400 28.000 ;
            POLYGON 735.400 28.000  735.400 36.500  738.000 36.500  738.000 31.400  738.800 31.400  738.800 28.000 ;
            POLYGON 767.800 28.000  767.800 36.500  770.400 36.500  770.400 31.400  771.200 31.400  771.200 28.000 ;
            POLYGON 800.200 28.000  800.200 36.500  802.800 36.500  802.800 31.400  803.600 31.400  803.600 28.000 ;
            POLYGON 416.500 6.500  416.500 9.900  418.400 9.900  418.400 28.000  416.800 28.000  416.800 31.400  418.400 31.400  418.400 44.900  415.100 44.900  415.100 58.300  417.700 58.300  417.700 46.700  420.200 46.700  420.200 6.500 ;
            POLYGON 448.900 6.500  448.900 9.900  450.800 9.900  450.800 28.000  449.200 28.000  449.200 31.400  450.800 31.400  450.800 44.900  447.500 44.900  447.500 58.300  450.100 58.300  450.100 46.700  452.600 46.700  452.600 6.500 ;
            POLYGON 481.300 6.500  481.300 9.900  483.200 9.900  483.200 28.000  481.600 28.000  481.600 31.400  483.200 31.400  483.200 44.900  479.900 44.900  479.900 58.300  482.500 58.300  482.500 46.700  485.000 46.700  485.000 6.500 ;
            POLYGON 513.700 6.500  513.700 9.900  515.600 9.900  515.600 28.000  514.000 28.000  514.000 31.400  515.600 31.400  515.600 44.900  512.300 44.900  512.300 58.300  514.900 58.300  514.900 46.700  517.400 46.700  517.400 6.500 ;
            POLYGON 546.100 6.500  546.100 9.900  548.000 9.900  548.000 28.000  546.400 28.000  546.400 31.400  548.000 31.400  548.000 44.900  544.700 44.900  544.700 58.300  547.300 58.300  547.300 46.700  549.800 46.700  549.800 6.500 ;
            POLYGON 578.500 6.500  578.500 9.900  580.400 9.900  580.400 28.000  578.800 28.000  578.800 31.400  580.400 31.400  580.400 44.900  577.100 44.900  577.100 58.300  579.700 58.300  579.700 46.700  582.200 46.700  582.200 6.500 ;
            POLYGON 610.900 6.500  610.900 9.900  612.800 9.900  612.800 28.000  611.200 28.000  611.200 31.400  612.800 31.400  612.800 44.900  609.500 44.900  609.500 58.300  612.100 58.300  612.100 46.700  614.600 46.700  614.600 6.500 ;
            POLYGON 643.300 6.500  643.300 9.900  645.200 9.900  645.200 28.000  643.600 28.000  643.600 31.400  645.200 31.400  645.200 44.900  641.900 44.900  641.900 58.300  644.500 58.300  644.500 46.700  647.000 46.700  647.000 6.500 ;
            POLYGON 675.700 6.500  675.700 9.900  677.600 9.900  677.600 28.000  676.000 28.000  676.000 31.400  677.600 31.400  677.600 44.900  674.300 44.900  674.300 58.300  676.900 58.300  676.900 46.700  679.400 46.700  679.400 6.500 ;
            POLYGON 708.100 6.500  708.100 9.900  710.000 9.900  710.000 28.000  708.400 28.000  708.400 31.400  710.000 31.400  710.000 44.900  706.700 44.900  706.700 58.300  709.300 58.300  709.300 46.700  711.800 46.700  711.800 6.500 ;
            POLYGON 740.500 6.500  740.500 9.900  742.400 9.900  742.400 28.000  740.800 28.000  740.800 31.400  742.400 31.400  742.400 44.900  739.100 44.900  739.100 58.300  741.700 58.300  741.700 46.700  744.200 46.700  744.200 6.500 ;
            POLYGON 772.900 6.500  772.900 9.900  774.800 9.900  774.800 28.000  773.200 28.000  773.200 31.400  774.800 31.400  774.800 44.900  771.500 44.900  771.500 58.300  774.100 58.300  774.100 46.700  776.600 46.700  776.600 6.500 ;
            POLYGON 805.300 6.500  805.300 9.900  807.200 9.900  807.200 28.000  805.600 28.000  805.600 31.400  807.200 31.400  807.200 44.900  803.900 44.900  803.900 58.300  806.500 58.300  806.500 46.700  809.000 46.700  809.000 6.500 ;
            POLYGON 411.400 28.000  411.400 36.500  414.000 36.500  414.000 31.400  414.800 31.400  414.800 28.000 ;
            POLYGON 406.800 88.300  406.800 93.400  406.000 93.400  406.000 96.800  409.400 96.800  409.400 88.300 ;
            POLYGON 439.200 88.300  439.200 93.400  438.400 93.400  438.400 96.800  441.800 96.800  441.800 88.300 ;
            POLYGON 471.600 88.300  471.600 93.400  470.800 93.400  470.800 96.800  474.200 96.800  474.200 88.300 ;
            POLYGON 504.000 88.300  504.000 93.400  503.200 93.400  503.200 96.800  506.600 96.800  506.600 88.300 ;
            POLYGON 536.400 88.300  536.400 93.400  535.600 93.400  535.600 96.800  539.000 96.800  539.000 88.300 ;
            POLYGON 568.800 88.300  568.800 93.400  568.000 93.400  568.000 96.800  571.400 96.800  571.400 88.300 ;
            POLYGON 601.200 88.300  601.200 93.400  600.400 93.400  600.400 96.800  603.800 96.800  603.800 88.300 ;
            POLYGON 633.600 88.300  633.600 93.400  632.800 93.400  632.800 96.800  636.200 96.800  636.200 88.300 ;
            POLYGON 666.000 88.300  666.000 93.400  665.200 93.400  665.200 96.800  668.600 96.800  668.600 88.300 ;
            POLYGON 698.400 88.300  698.400 93.400  697.600 93.400  697.600 96.800  701.000 96.800  701.000 88.300 ;
            POLYGON 730.800 88.300  730.800 93.400  730.000 93.400  730.000 96.800  733.400 96.800  733.400 88.300 ;
            POLYGON 763.200 88.300  763.200 93.400  762.400 93.400  762.400 96.800  765.800 96.800  765.800 88.300 ;
            POLYGON 795.600 88.300  795.600 93.400  794.800 93.400  794.800 96.800  798.200 96.800  798.200 88.300 ;
            POLYGON 443.800 28.000  443.800 36.500  446.400 36.500  446.400 31.400  447.200 31.400  447.200 28.000 ;
            POLYGON 435.500 66.500  435.500 78.100  433.000 78.100  433.000 118.300  436.700 118.300  436.700 114.900  434.800 114.900  434.800 96.800  436.400 96.800  436.400 93.400  434.800 93.400  434.800 79.900  438.100 79.900  438.100 66.500 ;
            POLYGON 467.900 66.500  467.900 78.100  465.400 78.100  465.400 118.300  469.100 118.300  469.100 114.900  467.200 114.900  467.200 96.800  468.800 96.800  468.800 93.400  467.200 93.400  467.200 79.900  470.500 79.900  470.500 66.500 ;
            POLYGON 500.300 66.500  500.300 78.100  497.800 78.100  497.800 118.300  501.500 118.300  501.500 114.900  499.600 114.900  499.600 96.800  501.200 96.800  501.200 93.400  499.600 93.400  499.600 79.900  502.900 79.900  502.900 66.500 ;
            POLYGON 532.700 66.500  532.700 78.100  530.200 78.100  530.200 118.300  533.900 118.300  533.900 114.900  532.000 114.900  532.000 96.800  533.600 96.800  533.600 93.400  532.000 93.400  532.000 79.900  535.300 79.900  535.300 66.500 ;
            POLYGON 565.100 66.500  565.100 78.100  562.600 78.100  562.600 118.300  566.300 118.300  566.300 114.900  564.400 114.900  564.400 96.800  566.000 96.800  566.000 93.400  564.400 93.400  564.400 79.900  567.700 79.900  567.700 66.500 ;
            POLYGON 597.500 66.500  597.500 78.100  595.000 78.100  595.000 118.300  598.700 118.300  598.700 114.900  596.800 114.900  596.800 96.800  598.400 96.800  598.400 93.400  596.800 93.400  596.800 79.900  600.100 79.900  600.100 66.500 ;
            POLYGON 629.900 66.500  629.900 78.100  627.400 78.100  627.400 118.300  631.100 118.300  631.100 114.900  629.200 114.900  629.200 96.800  630.800 96.800  630.800 93.400  629.200 93.400  629.200 79.900  632.500 79.900  632.500 66.500 ;
            POLYGON 662.300 66.500  662.300 78.100  659.800 78.100  659.800 118.300  663.500 118.300  663.500 114.900  661.600 114.900  661.600 96.800  663.200 96.800  663.200 93.400  661.600 93.400  661.600 79.900  664.900 79.900  664.900 66.500 ;
            POLYGON 694.700 66.500  694.700 78.100  692.200 78.100  692.200 118.300  695.900 118.300  695.900 114.900  694.000 114.900  694.000 96.800  695.600 96.800  695.600 93.400  694.000 93.400  694.000 79.900  697.300 79.900  697.300 66.500 ;
            POLYGON 727.100 66.500  727.100 78.100  724.600 78.100  724.600 118.300  728.300 118.300  728.300 114.900  726.400 114.900  726.400 96.800  728.000 96.800  728.000 93.400  726.400 93.400  726.400 79.900  729.700 79.900  729.700 66.500 ;
            POLYGON 759.500 66.500  759.500 78.100  757.000 78.100  757.000 118.300  760.700 118.300  760.700 114.900  758.800 114.900  758.800 96.800  760.400 96.800  760.400 93.400  758.800 93.400  758.800 79.900  762.100 79.900  762.100 66.500 ;
            POLYGON 791.900 66.500  791.900 78.100  789.400 78.100  789.400 118.300  793.100 118.300  793.100 114.900  791.200 114.900  791.200 96.800  792.800 96.800  792.800 93.400  791.200 93.400  791.200 79.900  794.500 79.900  794.500 66.500 ;
            POLYGON 180.000 88.300  180.000 93.400  179.200 93.400  179.200 96.800  182.600 96.800  182.600 88.300 ;
            POLYGON 212.400 88.300  212.400 93.400  211.600 93.400  211.600 96.800  215.000 96.800  215.000 88.300 ;
            POLYGON 244.800 88.300  244.800 93.400  244.000 93.400  244.000 96.800  247.400 96.800  247.400 88.300 ;
            POLYGON 277.200 88.300  277.200 93.400  276.400 93.400  276.400 96.800  279.800 96.800  279.800 88.300 ;
            POLYGON 309.600 88.300  309.600 93.400  308.800 93.400  308.800 96.800  312.200 96.800  312.200 88.300 ;
            POLYGON 342.000 88.300  342.000 93.400  341.200 93.400  341.200 96.800  344.600 96.800  344.600 88.300 ;
            POLYGON 374.400 88.300  374.400 93.400  373.600 93.400  373.600 96.800  377.000 96.800  377.000 88.300 ;
            POLYGON 157.300 6.500  157.300 9.900  159.200 9.900  159.200 28.000  157.600 28.000  157.600 31.400  159.200 31.400  159.200 44.900  155.900 44.900  155.900 58.300  158.500 58.300  158.500 46.700  161.000 46.700  161.000 6.500 ;
            POLYGON 189.700 6.500  189.700 9.900  191.600 9.900  191.600 28.000  190.000 28.000  190.000 31.400  191.600 31.400  191.600 44.900  188.300 44.900  188.300 58.300  190.900 58.300  190.900 46.700  193.400 46.700  193.400 6.500 ;
            POLYGON 222.100 6.500  222.100 9.900  224.000 9.900  224.000 28.000  222.400 28.000  222.400 31.400  224.000 31.400  224.000 44.900  220.700 44.900  220.700 58.300  223.300 58.300  223.300 46.700  225.800 46.700  225.800 6.500 ;
            POLYGON 254.500 6.500  254.500 9.900  256.400 9.900  256.400 28.000  254.800 28.000  254.800 31.400  256.400 31.400  256.400 44.900  253.100 44.900  253.100 58.300  255.700 58.300  255.700 46.700  258.200 46.700  258.200 6.500 ;
            POLYGON 286.900 6.500  286.900 9.900  288.800 9.900  288.800 28.000  287.200 28.000  287.200 31.400  288.800 31.400  288.800 44.900  285.500 44.900  285.500 58.300  288.100 58.300  288.100 46.700  290.600 46.700  290.600 6.500 ;
            POLYGON 319.300 6.500  319.300 9.900  321.200 9.900  321.200 28.000  319.600 28.000  319.600 31.400  321.200 31.400  321.200 44.900  317.900 44.900  317.900 58.300  320.500 58.300  320.500 46.700  323.000 46.700  323.000 6.500 ;
            POLYGON 351.700 6.500  351.700 9.900  353.600 9.900  353.600 28.000  352.000 28.000  352.000 31.400  353.600 31.400  353.600 44.900  350.300 44.900  350.300 58.300  352.900 58.300  352.900 46.700  355.400 46.700  355.400 6.500 ;
            POLYGON 384.100 6.500  384.100 9.900  386.000 9.900  386.000 28.000  384.400 28.000  384.400 31.400  386.000 31.400  386.000 44.900  382.700 44.900  382.700 58.300  385.300 58.300  385.300 46.700  387.800 46.700  387.800 6.500 ;
            POLYGON 184.600 28.000  184.600 36.500  187.200 36.500  187.200 31.400  188.000 31.400  188.000 28.000 ;
            POLYGON 217.000 28.000  217.000 36.500  219.600 36.500  219.600 31.400  220.400 31.400  220.400 28.000 ;
            POLYGON 249.400 28.000  249.400 36.500  252.000 36.500  252.000 31.400  252.800 31.400  252.800 28.000 ;
            POLYGON 281.800 28.000  281.800 36.500  284.400 36.500  284.400 31.400  285.200 31.400  285.200 28.000 ;
            POLYGON 314.200 28.000  314.200 36.500  316.800 36.500  316.800 31.400  317.600 31.400  317.600 28.000 ;
            POLYGON 46.700 66.500  46.700 78.100  44.200 78.100  44.200 118.300  47.900 118.300  47.900 114.900  46.000 114.900  46.000 96.800  47.600 96.800  47.600 93.400  46.000 93.400  46.000 79.900  49.300 79.900  49.300 66.500 ;
            POLYGON 79.100 66.500  79.100 78.100  76.600 78.100  76.600 118.300  80.300 118.300  80.300 114.900  78.400 114.900  78.400 96.800  80.000 96.800  80.000 93.400  78.400 93.400  78.400 79.900  81.700 79.900  81.700 66.500 ;
            POLYGON 111.500 66.500  111.500 78.100  109.000 78.100  109.000 118.300  112.700 118.300  112.700 114.900  110.800 114.900  110.800 96.800  112.400 96.800  112.400 93.400  110.800 93.400  110.800 79.900  114.100 79.900  114.100 66.500 ;
            POLYGON 143.900 66.500  143.900 78.100  141.400 78.100  141.400 118.300  145.100 118.300  145.100 114.900  143.200 114.900  143.200 96.800  144.800 96.800  144.800 93.400  143.200 93.400  143.200 79.900  146.500 79.900  146.500 66.500 ;
            POLYGON 176.300 66.500  176.300 78.100  173.800 78.100  173.800 118.300  177.500 118.300  177.500 114.900  175.600 114.900  175.600 96.800  177.200 96.800  177.200 93.400  175.600 93.400  175.600 79.900  178.900 79.900  178.900 66.500 ;
            POLYGON 208.700 66.500  208.700 78.100  206.200 78.100  206.200 118.300  209.900 118.300  209.900 114.900  208.000 114.900  208.000 96.800  209.600 96.800  209.600 93.400  208.000 93.400  208.000 79.900  211.300 79.900  211.300 66.500 ;
            POLYGON 241.100 66.500  241.100 78.100  238.600 78.100  238.600 118.300  242.300 118.300  242.300 114.900  240.400 114.900  240.400 96.800  242.000 96.800  242.000 93.400  240.400 93.400  240.400 79.900  243.700 79.900  243.700 66.500 ;
            POLYGON 273.500 66.500  273.500 78.100  271.000 78.100  271.000 118.300  274.700 118.300  274.700 114.900  272.800 114.900  272.800 96.800  274.400 96.800  274.400 93.400  272.800 93.400  272.800 79.900  276.100 79.900  276.100 66.500 ;
            POLYGON 305.900 66.500  305.900 78.100  303.400 78.100  303.400 118.300  307.100 118.300  307.100 114.900  305.200 114.900  305.200 96.800  306.800 96.800  306.800 93.400  305.200 93.400  305.200 79.900  308.500 79.900  308.500 66.500 ;
            POLYGON 338.300 66.500  338.300 78.100  335.800 78.100  335.800 118.300  339.500 118.300  339.500 114.900  337.600 114.900  337.600 96.800  339.200 96.800  339.200 93.400  337.600 93.400  337.600 79.900  340.900 79.900  340.900 66.500 ;
            POLYGON 370.700 66.500  370.700 78.100  368.200 78.100  368.200 118.300  371.900 118.300  371.900 114.900  370.000 114.900  370.000 96.800  371.600 96.800  371.600 93.400  370.000 93.400  370.000 79.900  373.300 79.900  373.300 66.500 ;
            POLYGON 346.600 28.000  346.600 36.500  349.200 36.500  349.200 31.400  350.000 31.400  350.000 28.000 ;
            POLYGON 379.000 28.000  379.000 36.500  381.600 36.500  381.600 31.400  382.400 31.400  382.400 28.000 ;
            POLYGON 87.400 28.000  87.400 36.500  90.000 36.500  90.000 31.400  90.800 31.400  90.800 28.000 ;
            POLYGON 119.800 28.000  119.800 36.500  122.400 36.500  122.400 31.400  123.200 31.400  123.200 28.000 ;
            POLYGON 152.200 28.000  152.200 36.500  154.800 36.500  154.800 31.400  155.600 31.400  155.600 28.000 ;
            POLYGON 27.700 6.500  27.700 9.900  29.600 9.900  29.600 28.000  28.000 28.000  28.000 31.400  29.600 31.400  29.600 44.900  26.300 44.900  26.300 58.300  28.900 58.300  28.900 46.700  31.400 46.700  31.400 6.500 ;
            POLYGON 60.100 6.500  60.100 9.900  62.000 9.900  62.000 28.000  60.400 28.000  60.400 31.400  62.000 31.400  62.000 44.900  58.700 44.900  58.700 58.300  61.300 58.300  61.300 46.700  63.800 46.700  63.800 6.500 ;
            POLYGON 92.500 6.500  92.500 9.900  94.400 9.900  94.400 28.000  92.800 28.000  92.800 31.400  94.400 31.400  94.400 44.900  91.100 44.900  91.100 58.300  93.700 58.300  93.700 46.700  96.200 46.700  96.200 6.500 ;
            POLYGON 124.900 6.500  124.900 9.900  126.800 9.900  126.800 28.000  125.200 28.000  125.200 31.400  126.800 31.400  126.800 44.900  123.500 44.900  123.500 58.300  126.100 58.300  126.100 46.700  128.600 46.700  128.600 6.500 ;
            POLYGON 50.400 88.300  50.400 93.400  49.600 93.400  49.600 96.800  53.000 96.800  53.000 88.300 ;
            POLYGON 82.800 88.300  82.800 93.400  82.000 93.400  82.000 96.800  85.400 96.800  85.400 88.300 ;
            POLYGON 115.200 88.300  115.200 93.400  114.400 93.400  114.400 96.800  117.800 96.800  117.800 88.300 ;
            POLYGON 147.600 88.300  147.600 93.400  146.800 93.400  146.800 96.800  150.200 96.800  150.200 88.300 ;
            POLYGON 22.600 28.000  22.600 36.500  25.200 36.500  25.200 31.400  26.000 31.400  26.000 28.000 ;
            POLYGON 55.000 28.000  55.000 36.500  57.600 36.500  57.600 31.400  58.400 31.400  58.400 28.000 ;
            POLYGON 91.100 -53.500  91.100 -40.100  94.400 -40.100  94.400 -26.600  92.800 -26.600  92.800 -23.200  94.400 -23.200  94.400 -5.100  92.500 -5.100  92.500 -1.700  96.200 -1.700  96.200 -53.500 ;
            POLYGON 123.500 -53.500  123.500 -40.100  126.800 -40.100  126.800 -26.600  125.200 -26.600  125.200 -23.200  126.800 -23.200  126.800 -5.100  124.900 -5.100  124.900 -1.700  128.600 -1.700  128.600 -53.500 ;
            POLYGON 155.900 -53.500  155.900 -40.100  159.200 -40.100  159.200 -26.600  157.600 -26.600  157.600 -23.200  159.200 -23.200  159.200 -5.100  157.300 -5.100  157.300 -1.700  161.000 -1.700  161.000 -53.500 ;
            POLYGON 188.300 -53.500  188.300 -40.100  191.600 -40.100  191.600 -26.600  190.000 -26.600  190.000 -23.200  191.600 -23.200  191.600 -5.100  189.700 -5.100  189.700 -1.700  193.400 -1.700  193.400 -53.500 ;
            POLYGON 220.700 -53.500  220.700 -40.100  224.000 -40.100  224.000 -26.600  222.400 -26.600  222.400 -23.200  224.000 -23.200  224.000 -5.100  222.100 -5.100  222.100 -1.700  225.800 -1.700  225.800 -53.500 ;
            POLYGON 253.100 -53.500  253.100 -40.100  256.400 -40.100  256.400 -26.600  254.800 -26.600  254.800 -23.200  256.400 -23.200  256.400 -5.100  254.500 -5.100  254.500 -1.700  258.200 -1.700  258.200 -53.500 ;
            POLYGON 285.500 -53.500  285.500 -40.100  288.800 -40.100  288.800 -26.600  287.200 -26.600  287.200 -23.200  288.800 -23.200  288.800 -5.100  286.900 -5.100  286.900 -1.700  290.600 -1.700  290.600 -53.500 ;
            POLYGON 317.900 -53.500  317.900 -40.100  321.200 -40.100  321.200 -26.600  319.600 -26.600  319.600 -23.200  321.200 -23.200  321.200 -5.100  319.300 -5.100  319.300 -1.700  323.000 -1.700  323.000 -53.500 ;
            POLYGON 350.300 -53.500  350.300 -40.100  353.600 -40.100  353.600 -26.600  352.000 -26.600  352.000 -23.200  353.600 -23.200  353.600 -5.100  351.700 -5.100  351.700 -1.700  355.400 -1.700  355.400 -53.500 ;
            POLYGON 382.700 -53.500  382.700 -40.100  386.000 -40.100  386.000 -26.600  384.400 -26.600  384.400 -23.200  386.000 -23.200  386.000 -5.100  384.100 -5.100  384.100 -1.700  387.800 -1.700  387.800 -53.500 ;
            POLYGON 281.800 -31.700  281.800 -23.200  285.200 -23.200  285.200 -26.600  284.400 -26.600  284.400 -31.700 ;
            POLYGON 314.200 -31.700  314.200 -23.200  317.600 -23.200  317.600 -26.600  316.800 -26.600  316.800 -31.700 ;
            POLYGON 346.600 -31.700  346.600 -23.200  350.000 -23.200  350.000 -26.600  349.200 -26.600  349.200 -31.700 ;
            POLYGON 379.000 -31.700  379.000 -23.200  382.400 -23.200  382.400 -26.600  381.600 -26.600  381.600 -31.700 ;
            POLYGON 76.600 -113.500  76.600 -61.700  81.700 -61.700  81.700 -75.100  78.400 -75.100  78.400 -88.600  80.000 -88.600  80.000 -92.000  78.400 -92.000  78.400 -110.100  80.300 -110.100  80.300 -113.500 ;
            POLYGON 87.400 -31.700  87.400 -23.200  90.800 -23.200  90.800 -26.600  90.000 -26.600  90.000 -31.700 ;
            POLYGON 119.800 -31.700  119.800 -23.200  123.200 -23.200  123.200 -26.600  122.400 -26.600  122.400 -31.700 ;
            POLYGON 152.200 -31.700  152.200 -23.200  155.600 -23.200  155.600 -26.600  154.800 -26.600  154.800 -31.700 ;
            POLYGON 109.000 -113.500  109.000 -61.700  114.100 -61.700  114.100 -75.100  110.800 -75.100  110.800 -88.600  112.400 -88.600  112.400 -92.000  110.800 -92.000  110.800 -110.100  112.700 -110.100  112.700 -113.500 ;
            POLYGON 141.400 -113.500  141.400 -61.700  146.500 -61.700  146.500 -75.100  143.200 -75.100  143.200 -88.600  144.800 -88.600  144.800 -92.000  143.200 -92.000  143.200 -110.100  145.100 -110.100  145.100 -113.500 ;
            POLYGON 173.800 -113.500  173.800 -61.700  178.900 -61.700  178.900 -75.100  175.600 -75.100  175.600 -88.600  177.200 -88.600  177.200 -92.000  175.600 -92.000  175.600 -110.100  177.500 -110.100  177.500 -113.500 ;
            POLYGON 206.200 -113.500  206.200 -61.700  211.300 -61.700  211.300 -75.100  208.000 -75.100  208.000 -88.600  209.600 -88.600  209.600 -92.000  208.000 -92.000  208.000 -110.100  209.900 -110.100  209.900 -113.500 ;
            POLYGON 238.600 -113.500  238.600 -61.700  243.700 -61.700  243.700 -75.100  240.400 -75.100  240.400 -88.600  242.000 -88.600  242.000 -92.000  240.400 -92.000  240.400 -110.100  242.300 -110.100  242.300 -113.500 ;
            POLYGON 271.000 -113.500  271.000 -61.700  276.100 -61.700  276.100 -75.100  272.800 -75.100  272.800 -88.600  274.400 -88.600  274.400 -92.000  272.800 -92.000  272.800 -110.100  274.700 -110.100  274.700 -113.500 ;
            POLYGON 303.400 -113.500  303.400 -61.700  308.500 -61.700  308.500 -75.100  305.200 -75.100  305.200 -88.600  306.800 -88.600  306.800 -92.000  305.200 -92.000  305.200 -110.100  307.100 -110.100  307.100 -113.500 ;
            POLYGON 335.800 -113.500  335.800 -61.700  340.900 -61.700  340.900 -75.100  337.600 -75.100  337.600 -88.600  339.200 -88.600  339.200 -92.000  337.600 -92.000  337.600 -110.100  339.500 -110.100  339.500 -113.500 ;
            POLYGON 368.200 -113.500  368.200 -61.700  373.300 -61.700  373.300 -75.100  370.000 -75.100  370.000 -88.600  371.600 -88.600  371.600 -92.000  370.000 -92.000  370.000 -110.100  371.900 -110.100  371.900 -113.500 ;
            POLYGON 184.600 -31.700  184.600 -23.200  188.000 -23.200  188.000 -26.600  187.200 -26.600  187.200 -31.700 ;
            POLYGON 82.000 -92.000  82.000 -88.600  82.800 -88.600  82.800 -83.500  85.400 -83.500  85.400 -92.000 ;
            POLYGON 114.400 -92.000  114.400 -88.600  115.200 -88.600  115.200 -83.500  117.800 -83.500  117.800 -92.000 ;
            POLYGON 217.000 -31.700  217.000 -23.200  220.400 -23.200  220.400 -26.600  219.600 -26.600  219.600 -31.700 ;
            POLYGON 249.400 -31.700  249.400 -23.200  252.800 -23.200  252.800 -26.600  252.000 -26.600  252.000 -31.700 ;
            POLYGON 146.800 -92.000  146.800 -88.600  147.600 -88.600  147.600 -83.500  150.200 -83.500  150.200 -92.000 ;
            POLYGON 179.200 -92.000  179.200 -88.600  180.000 -88.600  180.000 -83.500  182.600 -83.500  182.600 -92.000 ;
            POLYGON 211.600 -92.000  211.600 -88.600  212.400 -88.600  212.400 -83.500  215.000 -83.500  215.000 -92.000 ;
            POLYGON 244.000 -92.000  244.000 -88.600  244.800 -88.600  244.800 -83.500  247.400 -83.500  247.400 -92.000 ;
            POLYGON 276.400 -92.000  276.400 -88.600  277.200 -88.600  277.200 -83.500  279.800 -83.500  279.800 -92.000 ;
            POLYGON 308.800 -92.000  308.800 -88.600  309.600 -88.600  309.600 -83.500  312.200 -83.500  312.200 -92.000 ;
            POLYGON 341.200 -92.000  341.200 -88.600  342.000 -88.600  342.000 -83.500  344.600 -83.500  344.600 -92.000 ;
            POLYGON 373.600 -92.000  373.600 -88.600  374.400 -88.600  374.400 -83.500  377.000 -83.500  377.000 -92.000 ;
            POLYGON 49.600 -92.000  49.600 -88.600  50.400 -88.600  50.400 -83.500  53.000 -83.500  53.000 -92.000 ;
            POLYGON 44.200 -113.500  44.200 -61.700  49.300 -61.700  49.300 -75.100  46.000 -75.100  46.000 -88.600  47.600 -88.600  47.600 -92.000  46.000 -92.000  46.000 -110.100  47.900 -110.100  47.900 -113.500 ;
            POLYGON 22.600 -31.700  22.600 -23.200  26.000 -23.200  26.000 -26.600  25.200 -26.600  25.200 -31.700 ;
            POLYGON 55.000 -31.700  55.000 -23.200  58.400 -23.200  58.400 -26.600  57.600 -26.600  57.600 -31.700 ;
            POLYGON 26.300 -53.500  26.300 -40.100  29.600 -40.100  29.600 -26.600  28.000 -26.600  28.000 -23.200  29.600 -23.200  29.600 -5.100  27.700 -5.100  27.700 -1.700  31.400 -1.700  31.400 -53.500 ;
            POLYGON 58.700 -53.500  58.700 -40.100  62.000 -40.100  62.000 -26.600  60.400 -26.600  60.400 -23.200  62.000 -23.200  62.000 -5.100  60.100 -5.100  60.100 -1.700  63.800 -1.700  63.800 -53.500 ;
            POLYGON 771.500 -53.500  771.500 -40.100  774.800 -40.100  774.800 -26.600  773.200 -26.600  773.200 -23.200  774.800 -23.200  774.800 -5.100  772.900 -5.100  772.900 -1.700  776.600 -1.700  776.600 -53.500 ;
            POLYGON 497.800 -113.500  497.800 -61.700  502.900 -61.700  502.900 -75.100  499.600 -75.100  499.600 -88.600  501.200 -88.600  501.200 -92.000  499.600 -92.000  499.600 -110.100  501.500 -110.100  501.500 -113.500 ;
            POLYGON 530.200 -113.500  530.200 -61.700  535.300 -61.700  535.300 -75.100  532.000 -75.100  532.000 -88.600  533.600 -88.600  533.600 -92.000  532.000 -92.000  532.000 -110.100  533.900 -110.100  533.900 -113.500 ;
            POLYGON 562.600 -113.500  562.600 -61.700  567.700 -61.700  567.700 -75.100  564.400 -75.100  564.400 -88.600  566.000 -88.600  566.000 -92.000  564.400 -92.000  564.400 -110.100  566.300 -110.100  566.300 -113.500 ;
            POLYGON 595.000 -113.500  595.000 -61.700  600.100 -61.700  600.100 -75.100  596.800 -75.100  596.800 -88.600  598.400 -88.600  598.400 -92.000  596.800 -92.000  596.800 -110.100  598.700 -110.100  598.700 -113.500 ;
            POLYGON 627.400 -113.500  627.400 -61.700  632.500 -61.700  632.500 -75.100  629.200 -75.100  629.200 -88.600  630.800 -88.600  630.800 -92.000  629.200 -92.000  629.200 -110.100  631.100 -110.100  631.100 -113.500 ;
            POLYGON 659.800 -113.500  659.800 -61.700  664.900 -61.700  664.900 -75.100  661.600 -75.100  661.600 -88.600  663.200 -88.600  663.200 -92.000  661.600 -92.000  661.600 -110.100  663.500 -110.100  663.500 -113.500 ;
            POLYGON 692.200 -113.500  692.200 -61.700  697.300 -61.700  697.300 -75.100  694.000 -75.100  694.000 -88.600  695.600 -88.600  695.600 -92.000  694.000 -92.000  694.000 -110.100  695.900 -110.100  695.900 -113.500 ;
            POLYGON 724.600 -113.500  724.600 -61.700  729.700 -61.700  729.700 -75.100  726.400 -75.100  726.400 -88.600  728.000 -88.600  728.000 -92.000  726.400 -92.000  726.400 -110.100  728.300 -110.100  728.300 -113.500 ;
            POLYGON 757.000 -113.500  757.000 -61.700  762.100 -61.700  762.100 -75.100  758.800 -75.100  758.800 -88.600  760.400 -88.600  760.400 -92.000  758.800 -92.000  758.800 -110.100  760.700 -110.100  760.700 -113.500 ;
            POLYGON 789.400 -113.500  789.400 -61.700  794.500 -61.700  794.500 -75.100  791.200 -75.100  791.200 -88.600  792.800 -88.600  792.800 -92.000  791.200 -92.000  791.200 -110.100  793.100 -110.100  793.100 -113.500 ;
            POLYGON 735.400 -31.700  735.400 -23.200  738.800 -23.200  738.800 -26.600  738.000 -26.600  738.000 -31.700 ;
            POLYGON 767.800 -31.700  767.800 -23.200  771.200 -23.200  771.200 -26.600  770.400 -26.600  770.400 -31.700 ;
            POLYGON 800.200 -31.700  800.200 -23.200  803.600 -23.200  803.600 -26.600  802.800 -26.600  802.800 -31.700 ;
            POLYGON 411.400 -31.700  411.400 -23.200  414.800 -23.200  414.800 -26.600  414.000 -26.600  414.000 -31.700 ;
            POLYGON 443.800 -31.700  443.800 -23.200  447.200 -23.200  447.200 -26.600  446.400 -26.600  446.400 -31.700 ;
            POLYGON 476.200 -31.700  476.200 -23.200  479.600 -23.200  479.600 -26.600  478.800 -26.600  478.800 -31.700 ;
            POLYGON 508.600 -31.700  508.600 -23.200  512.000 -23.200  512.000 -26.600  511.200 -26.600  511.200 -31.700 ;
            POLYGON 541.000 -31.700  541.000 -23.200  544.400 -23.200  544.400 -26.600  543.600 -26.600  543.600 -31.700 ;
            POLYGON 573.400 -31.700  573.400 -23.200  576.800 -23.200  576.800 -26.600  576.000 -26.600  576.000 -31.700 ;
            POLYGON 605.800 -31.700  605.800 -23.200  609.200 -23.200  609.200 -26.600  608.400 -26.600  608.400 -31.700 ;
            POLYGON 638.200 -31.700  638.200 -23.200  641.600 -23.200  641.600 -26.600  640.800 -26.600  640.800 -31.700 ;
            POLYGON 670.600 -31.700  670.600 -23.200  674.000 -23.200  674.000 -26.600  673.200 -26.600  673.200 -31.700 ;
            POLYGON 703.000 -31.700  703.000 -23.200  706.400 -23.200  706.400 -26.600  705.600 -26.600  705.600 -31.700 ;
            POLYGON 433.000 -113.500  433.000 -61.700  438.100 -61.700  438.100 -75.100  434.800 -75.100  434.800 -88.600  436.400 -88.600  436.400 -92.000  434.800 -92.000  434.800 -110.100  436.700 -110.100  436.700 -113.500 ;
            POLYGON 803.900 -53.500  803.900 -40.100  807.200 -40.100  807.200 -26.600  805.600 -26.600  805.600 -23.200  807.200 -23.200  807.200 -5.100  805.300 -5.100  805.300 -1.700  809.000 -1.700  809.000 -53.500 ;
            POLYGON 465.400 -113.500  465.400 -61.700  470.500 -61.700  470.500 -75.100  467.200 -75.100  467.200 -88.600  468.800 -88.600  468.800 -92.000  467.200 -92.000  467.200 -110.100  469.100 -110.100  469.100 -113.500 ;
            POLYGON 415.100 -53.500  415.100 -40.100  418.400 -40.100  418.400 -26.600  416.800 -26.600  416.800 -23.200  418.400 -23.200  418.400 -5.100  416.500 -5.100  416.500 -1.700  420.200 -1.700  420.200 -53.500 ;
            POLYGON 447.500 -53.500  447.500 -40.100  450.800 -40.100  450.800 -26.600  449.200 -26.600  449.200 -23.200  450.800 -23.200  450.800 -5.100  448.900 -5.100  448.900 -1.700  452.600 -1.700  452.600 -53.500 ;
            POLYGON 479.900 -53.500  479.900 -40.100  483.200 -40.100  483.200 -26.600  481.600 -26.600  481.600 -23.200  483.200 -23.200  483.200 -5.100  481.300 -5.100  481.300 -1.700  485.000 -1.700  485.000 -53.500 ;
            POLYGON 512.300 -53.500  512.300 -40.100  515.600 -40.100  515.600 -26.600  514.000 -26.600  514.000 -23.200  515.600 -23.200  515.600 -5.100  513.700 -5.100  513.700 -1.700  517.400 -1.700  517.400 -53.500 ;
            POLYGON 544.700 -53.500  544.700 -40.100  548.000 -40.100  548.000 -26.600  546.400 -26.600  546.400 -23.200  548.000 -23.200  548.000 -5.100  546.100 -5.100  546.100 -1.700  549.800 -1.700  549.800 -53.500 ;
            POLYGON 406.000 -92.000  406.000 -88.600  406.800 -88.600  406.800 -83.500  409.400 -83.500  409.400 -92.000 ;
            POLYGON 438.400 -92.000  438.400 -88.600  439.200 -88.600  439.200 -83.500  441.800 -83.500  441.800 -92.000 ;
            POLYGON 470.800 -92.000  470.800 -88.600  471.600 -88.600  471.600 -83.500  474.200 -83.500  474.200 -92.000 ;
            POLYGON 503.200 -92.000  503.200 -88.600  504.000 -88.600  504.000 -83.500  506.600 -83.500  506.600 -92.000 ;
            POLYGON 535.600 -92.000  535.600 -88.600  536.400 -88.600  536.400 -83.500  539.000 -83.500  539.000 -92.000 ;
            POLYGON 568.000 -92.000  568.000 -88.600  568.800 -88.600  568.800 -83.500  571.400 -83.500  571.400 -92.000 ;
            POLYGON 600.400 -92.000  600.400 -88.600  601.200 -88.600  601.200 -83.500  603.800 -83.500  603.800 -92.000 ;
            POLYGON 632.800 -92.000  632.800 -88.600  633.600 -88.600  633.600 -83.500  636.200 -83.500  636.200 -92.000 ;
            POLYGON 665.200 -92.000  665.200 -88.600  666.000 -88.600  666.000 -83.500  668.600 -83.500  668.600 -92.000 ;
            POLYGON 697.600 -92.000  697.600 -88.600  698.400 -88.600  698.400 -83.500  701.000 -83.500  701.000 -92.000 ;
            POLYGON 730.000 -92.000  730.000 -88.600  730.800 -88.600  730.800 -83.500  733.400 -83.500  733.400 -92.000 ;
            POLYGON 762.400 -92.000  762.400 -88.600  763.200 -88.600  763.200 -83.500  765.800 -83.500  765.800 -92.000 ;
            POLYGON 794.800 -92.000  794.800 -88.600  795.600 -88.600  795.600 -83.500  798.200 -83.500  798.200 -92.000 ;
            POLYGON 577.100 -53.500  577.100 -40.100  580.400 -40.100  580.400 -26.600  578.800 -26.600  578.800 -23.200  580.400 -23.200  580.400 -5.100  578.500 -5.100  578.500 -1.700  582.200 -1.700  582.200 -53.500 ;
            POLYGON 609.500 -53.500  609.500 -40.100  612.800 -40.100  612.800 -26.600  611.200 -26.600  611.200 -23.200  612.800 -23.200  612.800 -5.100  610.900 -5.100  610.900 -1.700  614.600 -1.700  614.600 -53.500 ;
            POLYGON 641.900 -53.500  641.900 -40.100  645.200 -40.100  645.200 -26.600  643.600 -26.600  643.600 -23.200  645.200 -23.200  645.200 -5.100  643.300 -5.100  643.300 -1.700  647.000 -1.700  647.000 -53.500 ;
            POLYGON 674.300 -53.500  674.300 -40.100  677.600 -40.100  677.600 -26.600  676.000 -26.600  676.000 -23.200  677.600 -23.200  677.600 -5.100  675.700 -5.100  675.700 -1.700  679.400 -1.700  679.400 -53.500 ;
            POLYGON 706.700 -53.500  706.700 -40.100  710.000 -40.100  710.000 -26.600  708.400 -26.600  708.400 -23.200  710.000 -23.200  710.000 -5.100  708.100 -5.100  708.100 -1.700  711.800 -1.700  711.800 -53.500 ;
            POLYGON 739.100 -53.500  739.100 -40.100  742.400 -40.100  742.400 -26.600  740.800 -26.600  740.800 -23.200  742.400 -23.200  742.400 -5.100  740.500 -5.100  740.500 -1.700  744.200 -1.700  744.200 -53.500 ;
        LAYER M2 ;
            POLYGON 794.800 -92.000  794.800 -88.600  825.200 -88.600  825.200 -92.000 ;
            POLYGON 805.600 -26.600  805.600 -23.200  836.000 -23.200  836.000 -26.600 ;
            POLYGON 805.600 28.000  805.600 31.400  836.000 31.400  836.000 28.000 ;
            POLYGON 11.800 -115.500  11.800 4.200  1518.400 4.200  1518.400 31.400  1521.800 31.400  1521.800 -26.600  1518.400 -26.600  1518.400 0.800  15.200 0.800  15.200 -115.500 ;
            POLYGON 794.800 93.400  794.800 96.800  825.200 96.800  825.200 93.400 ;
            POLYGON 956.800 -92.000  956.800 -88.600  987.200 -88.600  987.200 -92.000 ;
            POLYGON 989.200 -92.000  989.200 -88.600  1019.600 -88.600  1019.600 -92.000 ;
            POLYGON 1021.600 -92.000  1021.600 -88.600  1052.000 -88.600  1052.000 -92.000 ;
            POLYGON 1054.000 -92.000  1054.000 -88.600  1084.400 -88.600  1084.400 -92.000 ;
            POLYGON 1086.400 -92.000  1086.400 -88.600  1116.800 -88.600  1116.800 -92.000 ;
            POLYGON 1118.800 -92.000  1118.800 -88.600  1149.200 -88.600  1149.200 -92.000 ;
            POLYGON 1151.200 -92.000  1151.200 -88.600  1181.600 -88.600  1181.600 -92.000 ;
            POLYGON 1183.600 -92.000  1183.600 -88.600  1214.000 -88.600  1214.000 -92.000 ;
            POLYGON 1216.000 -92.000  1216.000 -88.600  1246.400 -88.600  1246.400 -92.000 ;
            POLYGON 1248.400 -92.000  1248.400 -88.600  1278.800 -88.600  1278.800 -92.000 ;
            POLYGON 1280.800 -92.000  1280.800 -88.600  1311.200 -88.600  1311.200 -92.000 ;
            POLYGON 1313.200 -92.000  1313.200 -88.600  1343.600 -88.600  1343.600 -92.000 ;
            POLYGON 1345.600 -92.000  1345.600 -88.600  1376.000 -88.600  1376.000 -92.000 ;
            POLYGON 1378.000 -92.000  1378.000 -88.600  1408.400 -88.600  1408.400 -92.000 ;
            POLYGON 1410.400 -92.000  1410.400 -88.600  1440.800 -88.600  1440.800 -92.000 ;
            POLYGON 1442.800 -92.000  1442.800 -88.600  1473.200 -88.600  1473.200 -92.000 ;
            POLYGON 1475.200 -92.000  1475.200 -88.600  1505.600 -88.600  1505.600 -92.000 ;
            POLYGON 1507.600 -92.000  1507.600 -88.600  1538.000 -88.600  1538.000 -92.000 ;
            POLYGON 1540.000 -92.000  1540.000 -88.600  1570.400 -88.600  1570.400 -92.000 ;
            POLYGON 1572.400 -92.000  1572.400 -88.600  1602.800 -88.600  1602.800 -92.000 ;
            POLYGON 827.200 -92.000  827.200 -88.600  857.600 -88.600  857.600 -92.000 ;
            POLYGON 838.000 -26.600  838.000 -23.200  868.400 -23.200  868.400 -26.600 ;
            POLYGON 870.400 -26.600  870.400 -23.200  900.800 -23.200  900.800 -26.600 ;
            POLYGON 902.800 -26.600  902.800 -23.200  933.200 -23.200  933.200 -26.600 ;
            POLYGON 935.200 -26.600  935.200 -23.200  965.600 -23.200  965.600 -26.600 ;
            POLYGON 967.600 -26.600  967.600 -23.200  998.000 -23.200  998.000 -26.600 ;
            POLYGON 1000.000 -26.600  1000.000 -23.200  1030.400 -23.200  1030.400 -26.600 ;
            POLYGON 1032.400 -26.600  1032.400 -23.200  1062.800 -23.200  1062.800 -26.600 ;
            POLYGON 1064.800 -26.600  1064.800 -23.200  1095.200 -23.200  1095.200 -26.600 ;
            POLYGON 1097.200 -26.600  1097.200 -23.200  1127.600 -23.200  1127.600 -26.600 ;
            POLYGON 1129.600 -26.600  1129.600 -23.200  1160.000 -23.200  1160.000 -26.600 ;
            POLYGON 1162.000 -26.600  1162.000 -23.200  1192.400 -23.200  1192.400 -26.600 ;
            POLYGON 1194.400 -26.600  1194.400 -23.200  1224.800 -23.200  1224.800 -26.600 ;
            POLYGON 1226.800 -26.600  1226.800 -23.200  1257.200 -23.200  1257.200 -26.600 ;
            POLYGON 1259.200 -26.600  1259.200 -23.200  1289.600 -23.200  1289.600 -26.600 ;
            POLYGON 1291.600 -26.600  1291.600 -23.200  1322.000 -23.200  1322.000 -26.600 ;
            POLYGON 1324.000 -26.600  1324.000 -23.200  1354.400 -23.200  1354.400 -26.600 ;
            POLYGON 1356.400 -26.600  1356.400 -23.200  1386.800 -23.200  1386.800 -26.600 ;
            POLYGON 1388.800 -26.600  1388.800 -23.200  1419.200 -23.200  1419.200 -26.600 ;
            POLYGON 1421.200 -26.600  1421.200 -23.200  1451.600 -23.200  1451.600 -26.600 ;
            POLYGON 1453.600 -26.600  1453.600 -23.200  1484.000 -23.200  1484.000 -26.600 ;
            POLYGON 1486.000 -26.600  1486.000 -23.200  1516.400 -23.200  1516.400 -26.600 ;
            POLYGON 1604.800 -92.000  1604.800 -59.300  1599.400 -59.300  1599.400 -26.600  1529.200 -26.600  1529.200 -23.200  1602.800 -23.200  1602.800 -55.900  1608.200 -55.900  1608.200 -92.000 ;
            POLYGON 1604.800 -26.600  1604.800 -23.200  1608.200 -23.200  1608.200 -26.600 ;
            POLYGON 859.600 -92.000  859.600 -88.600  890.000 -88.600  890.000 -92.000 ;
            POLYGON 838.000 28.000  838.000 31.400  868.400 31.400  868.400 28.000 ;
            POLYGON 870.400 28.000  870.400 31.400  900.800 31.400  900.800 28.000 ;
            POLYGON 902.800 28.000  902.800 31.400  933.200 31.400  933.200 28.000 ;
            POLYGON 935.200 28.000  935.200 31.400  965.600 31.400  965.600 28.000 ;
            POLYGON 967.600 28.000  967.600 31.400  998.000 31.400  998.000 28.000 ;
            POLYGON 1000.000 28.000  1000.000 31.400  1030.400 31.400  1030.400 28.000 ;
            POLYGON 1032.400 28.000  1032.400 31.400  1062.800 31.400  1062.800 28.000 ;
            POLYGON 1064.800 28.000  1064.800 31.400  1095.200 31.400  1095.200 28.000 ;
            POLYGON 1097.200 28.000  1097.200 31.400  1127.600 31.400  1127.600 28.000 ;
            POLYGON 1129.600 28.000  1129.600 31.400  1160.000 31.400  1160.000 28.000 ;
            POLYGON 1162.000 28.000  1162.000 31.400  1192.400 31.400  1192.400 28.000 ;
            POLYGON 1194.400 28.000  1194.400 31.400  1224.800 31.400  1224.800 28.000 ;
            POLYGON 1226.800 28.000  1226.800 31.400  1257.200 31.400  1257.200 28.000 ;
            POLYGON 1259.200 28.000  1259.200 31.400  1289.600 31.400  1289.600 28.000 ;
            POLYGON 1291.600 28.000  1291.600 31.400  1322.000 31.400  1322.000 28.000 ;
            POLYGON 1324.000 28.000  1324.000 31.400  1354.400 31.400  1354.400 28.000 ;
            POLYGON 1356.400 28.000  1356.400 31.400  1386.800 31.400  1386.800 28.000 ;
            POLYGON 1388.800 28.000  1388.800 31.400  1419.200 31.400  1419.200 28.000 ;
            POLYGON 1421.200 28.000  1421.200 31.400  1451.600 31.400  1451.600 28.000 ;
            POLYGON 1453.600 28.000  1453.600 31.400  1484.000 31.400  1484.000 28.000 ;
            POLYGON 1486.000 28.000  1486.000 31.400  1516.400 31.400  1516.400 28.000 ;
            POLYGON 892.000 -92.000  892.000 -88.600  922.400 -88.600  922.400 -92.000 ;
            POLYGON 1604.800 28.000  1604.800 31.400  1608.200 31.400  1608.200 28.000 ;
            POLYGON 924.400 -92.000  924.400 -88.600  954.800 -88.600  954.800 -92.000 ;
            POLYGON 827.200 93.400  827.200 96.800  857.600 96.800  857.600 93.400 ;
            POLYGON 859.600 93.400  859.600 96.800  890.000 96.800  890.000 93.400 ;
            POLYGON 892.000 93.400  892.000 96.800  922.400 96.800  922.400 93.400 ;
            POLYGON 924.400 93.400  924.400 96.800  954.800 96.800  954.800 93.400 ;
            POLYGON 956.800 93.400  956.800 96.800  987.200 96.800  987.200 93.400 ;
            POLYGON 989.200 93.400  989.200 96.800  1019.600 96.800  1019.600 93.400 ;
            POLYGON 1021.600 93.400  1021.600 96.800  1052.000 96.800  1052.000 93.400 ;
            POLYGON 1054.000 93.400  1054.000 96.800  1084.400 96.800  1084.400 93.400 ;
            POLYGON 1086.400 93.400  1086.400 96.800  1116.800 96.800  1116.800 93.400 ;
            POLYGON 1118.800 93.400  1118.800 96.800  1149.200 96.800  1149.200 93.400 ;
            POLYGON 1151.200 93.400  1151.200 96.800  1181.600 96.800  1181.600 93.400 ;
            POLYGON 1183.600 93.400  1183.600 96.800  1214.000 96.800  1214.000 93.400 ;
            POLYGON 1216.000 93.400  1216.000 96.800  1246.400 96.800  1246.400 93.400 ;
            POLYGON 1248.400 93.400  1248.400 96.800  1278.800 96.800  1278.800 93.400 ;
            POLYGON 1280.800 93.400  1280.800 96.800  1311.200 96.800  1311.200 93.400 ;
            POLYGON 1313.200 93.400  1313.200 96.800  1343.600 96.800  1343.600 93.400 ;
            POLYGON 1345.600 93.400  1345.600 96.800  1376.000 96.800  1376.000 93.400 ;
            POLYGON 1378.000 93.400  1378.000 96.800  1408.400 96.800  1408.400 93.400 ;
            POLYGON 1410.400 93.400  1410.400 96.800  1440.800 96.800  1440.800 93.400 ;
            POLYGON 1442.800 93.400  1442.800 96.800  1473.200 96.800  1473.200 93.400 ;
            POLYGON 1475.200 93.400  1475.200 96.800  1505.600 96.800  1505.600 93.400 ;
            POLYGON 1507.600 93.400  1507.600 96.800  1538.000 96.800  1538.000 93.400 ;
            POLYGON 1540.000 93.400  1540.000 96.800  1570.400 96.800  1570.400 93.400 ;
            POLYGON 1572.400 93.400  1572.400 96.800  1602.800 96.800  1602.800 93.400 ;
            POLYGON 1529.200 28.000  1529.200 31.400  1599.400 31.400  1599.400 64.100  1604.800 64.100  1604.800 96.800  1608.200 96.800  1608.200 60.700  1602.800 60.700  1602.800 28.000 ;
            POLYGON 1610.200 -118.900  1610.200 123.700  1613.600 123.700  1613.600 -118.900 ;
            POLYGON 1615.600 -118.900  1615.600 123.700  1619.000 123.700  1619.000 -118.900 ;
            POLYGON 157.600 28.000  157.600 31.400  188.000 31.400  188.000 28.000 ;
            POLYGON 190.000 28.000  190.000 31.400  220.400 31.400  220.400 28.000 ;
            POLYGON 222.400 28.000  222.400 31.400  252.800 31.400  252.800 28.000 ;
            POLYGON 254.800 28.000  254.800 31.400  285.200 31.400  285.200 28.000 ;
            POLYGON 287.200 28.000  287.200 31.400  317.600 31.400  317.600 28.000 ;
            POLYGON 319.600 28.000  319.600 31.400  350.000 31.400  350.000 28.000 ;
            POLYGON 352.000 28.000  352.000 31.400  382.400 31.400  382.400 28.000 ;
            POLYGON 384.400 28.000  384.400 31.400  414.800 31.400  414.800 28.000 ;
            POLYGON 416.800 28.000  416.800 31.400  447.200 31.400  447.200 28.000 ;
            POLYGON 449.200 28.000  449.200 31.400  479.600 31.400  479.600 28.000 ;
            POLYGON 481.600 28.000  481.600 31.400  512.000 31.400  512.000 28.000 ;
            POLYGON 514.000 28.000  514.000 31.400  544.400 31.400  544.400 28.000 ;
            POLYGON 546.400 28.000  546.400 31.400  576.800 31.400  576.800 28.000 ;
            POLYGON 578.800 28.000  578.800 31.400  609.200 31.400  609.200 28.000 ;
            POLYGON 611.200 28.000  611.200 31.400  641.600 31.400  641.600 28.000 ;
            POLYGON 643.600 28.000  643.600 31.400  674.000 31.400  674.000 28.000 ;
            POLYGON 676.000 28.000  676.000 31.400  706.400 31.400  706.400 28.000 ;
            POLYGON 708.400 28.000  708.400 31.400  738.800 31.400  738.800 28.000 ;
            POLYGON 740.800 28.000  740.800 31.400  771.200 31.400  771.200 28.000 ;
            POLYGON 773.200 28.000  773.200 31.400  803.600 31.400  803.600 28.000 ;
            POLYGON 28.000 -26.600  28.000 -23.200  58.400 -23.200  58.400 -26.600 ;
            POLYGON 60.400 -26.600  60.400 -23.200  90.800 -23.200  90.800 -26.600 ;
            POLYGON 92.800 -26.600  92.800 -23.200  123.200 -23.200  123.200 -26.600 ;
            POLYGON 125.200 -26.600  125.200 -23.200  155.600 -23.200  155.600 -26.600 ;
            POLYGON 157.600 -26.600  157.600 -23.200  188.000 -23.200  188.000 -26.600 ;
            POLYGON 190.000 -26.600  190.000 -23.200  220.400 -23.200  220.400 -26.600 ;
            POLYGON 222.400 -26.600  222.400 -23.200  252.800 -23.200  252.800 -26.600 ;
            POLYGON 254.800 -26.600  254.800 -23.200  285.200 -23.200  285.200 -26.600 ;
            POLYGON 287.200 -26.600  287.200 -23.200  317.600 -23.200  317.600 -26.600 ;
            POLYGON 319.600 -26.600  319.600 -23.200  350.000 -23.200  350.000 -26.600 ;
            POLYGON 352.000 -26.600  352.000 -23.200  382.400 -23.200  382.400 -26.600 ;
            POLYGON 384.400 -26.600  384.400 -23.200  414.800 -23.200  414.800 -26.600 ;
            POLYGON 416.800 -26.600  416.800 -23.200  447.200 -23.200  447.200 -26.600 ;
            POLYGON 449.200 -26.600  449.200 -23.200  479.600 -23.200  479.600 -26.600 ;
            POLYGON 481.600 -26.600  481.600 -23.200  512.000 -23.200  512.000 -26.600 ;
            POLYGON 514.000 -26.600  514.000 -23.200  544.400 -23.200  544.400 -26.600 ;
            POLYGON 546.400 -26.600  546.400 -23.200  576.800 -23.200  576.800 -26.600 ;
            POLYGON 578.800 -26.600  578.800 -23.200  609.200 -23.200  609.200 -26.600 ;
            POLYGON 611.200 -26.600  611.200 -23.200  641.600 -23.200  641.600 -26.600 ;
            POLYGON 643.600 -26.600  643.600 -23.200  674.000 -23.200  674.000 -26.600 ;
            POLYGON 676.000 -26.600  676.000 -23.200  706.400 -23.200  706.400 -26.600 ;
            POLYGON 708.400 -26.600  708.400 -23.200  738.800 -23.200  738.800 -26.600 ;
            POLYGON 740.800 -26.600  740.800 -23.200  771.200 -23.200  771.200 -26.600 ;
            POLYGON 773.200 -26.600  773.200 -23.200  803.600 -23.200  803.600 -26.600 ;
            POLYGON 22.600 28.000  22.600 93.400  20.600 93.400  20.600 96.800  47.600 96.800  47.600 93.400  26.000 93.400  26.000 28.000 ;
            POLYGON 49.600 93.400  49.600 96.800  80.000 96.800  80.000 93.400 ;
            POLYGON 82.000 93.400  82.000 96.800  112.400 96.800  112.400 93.400 ;
            POLYGON 114.400 93.400  114.400 96.800  144.800 96.800  144.800 93.400 ;
            POLYGON 146.800 93.400  146.800 96.800  177.200 96.800  177.200 93.400 ;
            POLYGON 179.200 93.400  179.200 96.800  209.600 96.800  209.600 93.400 ;
            POLYGON 211.600 93.400  211.600 96.800  242.000 96.800  242.000 93.400 ;
            POLYGON 244.000 93.400  244.000 96.800  274.400 96.800  274.400 93.400 ;
            POLYGON 276.400 93.400  276.400 96.800  306.800 96.800  306.800 93.400 ;
            POLYGON 308.800 93.400  308.800 96.800  339.200 96.800  339.200 93.400 ;
            POLYGON 341.200 93.400  341.200 96.800  371.600 96.800  371.600 93.400 ;
            POLYGON 373.600 93.400  373.600 96.800  404.000 96.800  404.000 93.400 ;
            POLYGON 406.000 93.400  406.000 96.800  436.400 96.800  436.400 93.400 ;
            POLYGON 438.400 93.400  438.400 96.800  468.800 96.800  468.800 93.400 ;
            POLYGON 470.800 93.400  470.800 96.800  501.200 96.800  501.200 93.400 ;
            POLYGON 503.200 93.400  503.200 96.800  533.600 96.800  533.600 93.400 ;
            POLYGON 535.600 93.400  535.600 96.800  566.000 96.800  566.000 93.400 ;
            POLYGON 568.000 93.400  568.000 96.800  598.400 96.800  598.400 93.400 ;
            POLYGON 600.400 93.400  600.400 96.800  630.800 96.800  630.800 93.400 ;
            POLYGON 632.800 93.400  632.800 96.800  663.200 96.800  663.200 93.400 ;
            POLYGON 665.200 93.400  665.200 96.800  695.600 96.800  695.600 93.400 ;
            POLYGON 697.600 93.400  697.600 96.800  728.000 96.800  728.000 93.400 ;
            POLYGON 730.000 93.400  730.000 96.800  760.400 96.800  760.400 93.400 ;
            POLYGON 762.400 93.400  762.400 96.800  792.800 96.800  792.800 93.400 ;
            POLYGON 114.400 -92.000  114.400 -88.600  144.800 -88.600  144.800 -92.000 ;
            POLYGON 146.800 -92.000  146.800 -88.600  177.200 -88.600  177.200 -92.000 ;
            POLYGON 179.200 -92.000  179.200 -88.600  209.600 -88.600  209.600 -92.000 ;
            POLYGON 211.600 -92.000  211.600 -88.600  242.000 -88.600  242.000 -92.000 ;
            POLYGON 244.000 -92.000  244.000 -88.600  274.400 -88.600  274.400 -92.000 ;
            POLYGON 276.400 -92.000  276.400 -88.600  306.800 -88.600  306.800 -92.000 ;
            POLYGON 308.800 -92.000  308.800 -88.600  339.200 -88.600  339.200 -92.000 ;
            POLYGON 341.200 -92.000  341.200 -88.600  371.600 -88.600  371.600 -92.000 ;
            POLYGON 373.600 -92.000  373.600 -88.600  404.000 -88.600  404.000 -92.000 ;
            POLYGON 406.000 -92.000  406.000 -88.600  436.400 -88.600  436.400 -92.000 ;
            POLYGON 438.400 -92.000  438.400 -88.600  468.800 -88.600  468.800 -92.000 ;
            POLYGON 470.800 -92.000  470.800 -88.600  501.200 -88.600  501.200 -92.000 ;
            POLYGON 503.200 -92.000  503.200 -88.600  533.600 -88.600  533.600 -92.000 ;
            POLYGON 535.600 -92.000  535.600 -88.600  566.000 -88.600  566.000 -92.000 ;
            POLYGON 568.000 -92.000  568.000 -88.600  598.400 -88.600  598.400 -92.000 ;
            POLYGON 600.400 -92.000  600.400 -88.600  630.800 -88.600  630.800 -92.000 ;
            POLYGON 632.800 -92.000  632.800 -88.600  663.200 -88.600  663.200 -92.000 ;
            POLYGON 665.200 -92.000  665.200 -88.600  695.600 -88.600  695.600 -92.000 ;
            POLYGON 697.600 -92.000  697.600 -88.600  728.000 -88.600  728.000 -92.000 ;
            POLYGON 730.000 -92.000  730.000 -88.600  760.400 -88.600  760.400 -92.000 ;
            POLYGON 762.400 -92.000  762.400 -88.600  792.800 -88.600  792.800 -92.000 ;
            POLYGON 49.600 -92.000  49.600 -88.600  80.000 -88.600  80.000 -92.000 ;
            POLYGON 82.000 -92.000  82.000 -88.600  112.400 -88.600  112.400 -92.000 ;
            POLYGON 20.600 -92.000  20.600 -88.600  22.600 -88.600  22.600 -23.200  26.000 -23.200  26.000 -88.600  47.600 -88.600  47.600 -92.000 ;
            POLYGON 28.000 28.000  28.000 31.400  58.400 31.400  58.400 28.000 ;
            POLYGON 60.400 28.000  60.400 31.400  90.800 31.400  90.800 28.000 ;
            POLYGON 1.000 -118.900  1.000 123.700  4.400 123.700  4.400 -118.900 ;
            POLYGON 6.400 -118.900  6.400 123.700  9.800 123.700  9.800 -118.900 ;
            POLYGON 92.800 28.000  92.800 31.400  123.200 31.400  123.200 28.000 ;
            POLYGON 125.200 28.000  125.200 31.400  155.600 31.400  155.600 28.000 ;
    END

END RING_OSC
END LIBRARY
